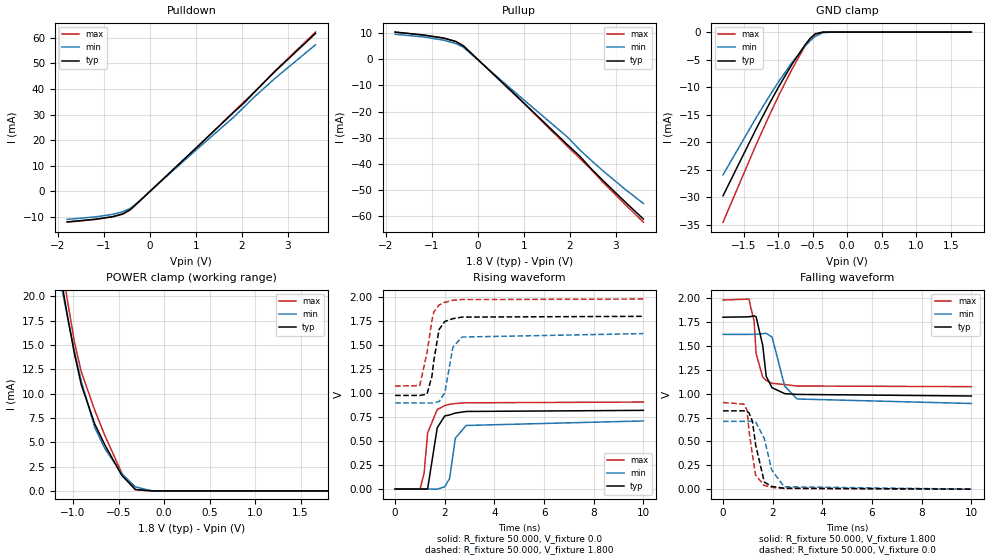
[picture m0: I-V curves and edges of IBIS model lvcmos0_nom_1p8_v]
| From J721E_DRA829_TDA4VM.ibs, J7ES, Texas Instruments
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|   nom_1p8_v
[Model]   lvcmos0_nom_1p8_v
Model_type I/O
Polarity   Non-Inverting
Enable   Active-High
Vinl = 0
Vinh = 0.8
Vmeas = 0.9
Vref = 1.8
Cref = 2pF
Rref = 100000
|   typ   min   max
C_comp   2.559pF   2.311pF   2.804pF
[Voltage Range]   1.8   1.62   1.98
[Temperature Range]   27   150   -40
[Pullup Reference]   1.8   1.62   1.98
[Pulldown Reference]   0   0   0
[Power Clamp Reference]   1.8   1.62   1.98
[GND Clamp Reference]   0   0   0
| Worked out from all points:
|   slope of the pulldown table from 0 to 0.27 V, typ, clamps not added: 59.3 ohm
|   slope of the pullup table from 0 to 0.27 V, typ, clamps not added: 60 ohm
|   GND clamp passes 1 mA (typ) near -0.52 V on its own axis
|   POWER clamp passes 1 mA (typ) near -0.42 V on its own axis
|   rising waveform, R_fixture 50.000, V_fixture 0.0: 20-80 % time 268ps typ, 262ps min, 259ps max; typ from 0 V to 0.82 V
|   rising waveform, R_fixture 50.000, V_fixture 1.800: 20-80 % time 301ps typ, 282ps min, 348ps max; typ from 0.975 V to 1.8 V
|   falling waveform, R_fixture 50.000, V_fixture 1.800: 20-80 % time 298ps typ, 353ps min, 223ps max; typ from 1.8 V to 0.975 V
|   falling waveform, R_fixture 50.000, V_fixture 0.0: 20-80 % time 335ps typ, 434ps min, 272ps max; typ from 0.82 V to 0 V
[Pulldown]
|Voltage   I(typ)   I(min)   I(max)
-1.8V     -11.92mA   -10.93mA   -12.03mA
-1.194V   -10.89mA   -9.969mA   -10.95mA
-808mV    -9.857mA   -8.96mA    -9.935mA
-588mV    -8.778mA   -7.939mA   -8.877mA
-422mV    -7.06mA    -6.521mA   -7.099mA
-257mV    -4.345mA   -4.14mA    -4.333mA
955mV     16.15mA    15.41mA    16.09mA
1.837V    31.15mA    29.26mA    31.44mA
2.057V    34.72mA    33.17mA    35.2mA
2.278V    38.94mA    37.03mA    38.86mA
2.718V    46.83mA    44.15mA    47.05mA
3.6V      61.7mA     57.28mA    62.23mA
[Pullup]
|Voltage   I(typ)   I(min)   I(max)
-1.8V     10.47mA    9.652mA    10.48mA
-1.194V   9.383mA    8.634mA    9.35mA
-753mV    8.204mA    7.418mA    8.202mA
-478mV    6.836mA    6.068mA    6.907mA
-312mV    5.131mA    4.611mA    5.211mA
900mV     -15.03mA   -14.03mA   -15.13mA
1.947V    -32.72mA   -29.76mA   -33.34mA
2.222V    -37.22mA   -34.8mA    -38.07mA
2.443V    -41.56mA   -38.39mA   -41.85mA
2.718V    -46.41mA   -42.7mA    -47.08mA
3.214V    -54.86mA   -50mA      -55.8mA
3.6V      -61.24mA   -55.26mA   -62.44mA
[GND_clamp]
|Voltage   I(typ)   I(min)   I(max)
-1.8V     -29.72mA   -25.92mA   -34.52mA
-1.318V   -17.54mA   -15.51mA   -20.38mA
-1.132V   -13.09mA   -11.7mA    -15.22mA
-984mV    -9.729mA   -8.822mA   -11.3mA
-798mV    -5.797mA   -5.489mA   -6.696mA
-612mV    -2.352mA   -2.576mA   -2.564mA
-538mV    -1.179mA   -1.584mA   -1.166mA
-464mV    -369.8uA   -774.2uA   -275.4uA
-353mV    -16.01uA   -131.2uA   -4.376uA
-241mV    -388.4nA   -11.03uA   -119.1nA
1.8V      0A         0A         0A
[POWER_clamp]
|Voltage   I(typ)   I(min)   I(max)
-1.8V     63.47mA    56.87mA    71.37mA
-1.132V   21.93mA    21.28mA    24mA
-1.095V   19.86mA    19.49mA    21.65mA
-1.058V   17.85mA    17.74mA    19.39mA
-984mV    14.09mA    14.38mA    15.31mA
-909mV    10.91mA    11.3mA     12.26mA
-761mV    6.888mA    6.523mA    8.298mA
-649mV    4.716mA    4.333mA    5.678mA
-464mV    1.593mA    1.774mA    1.827mA
-315mV    150.2uA    416.6uA    111.8uA
-130mV    308.5nA    7.699uA    149nA
1.8V      0A         0A         0A
[Ramp]
| variable   typ   min   max
dV/dt_r   0.492/0.267n   0.426/0.263n   0.544/0.259n
dV/dt_f   0.495/0.298n   0.434/0.353n   0.544/0.223n
R_load = 50.000
[Rising Waveform]
R_fixture= 50.000
V_fixture= 0.0
|time   V(typ)   V(min)   V(max)
0s        815nV      17.91uV    1.383uV
1.005ns   106uV      16.08uV    1.636mV
1.171ns   -1.124mV   24.24uV    170.7mV
1.309ns   855.6uV    18.1uV     584.8mV
1.696ns   637.9mV    -1.709mV   828.1mV
2ns       761.7mV    24.35mV    869.8mV
2.195ns   772.2mV    109.5mV    883.1mV
2.427ns   791.7mV    530mV      891.3mV
2.86ns    808.2mV    662.3mV    898.7mV
10ns      819.8mV    709.6mV    906.4mV
[Rising Waveform]
R_fixture= 50.000
V_fixture= 1.800
V_fixture_min= 1.620
V_fixture_max= 1.980
|time   V(typ)   V(min)   V(max)
0s        975.3mV    896.8mV    1.073V
991ps     975.3mV    896.8mV    1.078V
1.283ns   988.9mV    896.7mV    1.417V
1.482ns   1.174V     896.7mV    1.757V
1.56ns    1.337V     896.7mV    1.845V
1.769ns   1.662V     911.5mV    1.918V
2.001ns   1.746V     1.003V     1.946V
2.328ns   1.776V     1.479V     1.968V
2.694ns   1.792V     1.584V     1.975V
10ns      1.8V       1.62V      1.98V
[Falling Waveform]
R_fixture= 50.000
V_fixture= 1.800
V_fixture_min= 1.620
V_fixture_max= 1.980
|time   V(typ)   V(min)   V(max)
0s        1.8V       1.62V      1.98V
1.041ns   1.804V     1.62V      1.99V
1.253ns   1.814V     1.621V     1.756V
1.331ns   1.805V     1.622V     1.421V
1.599ns   1.505V     1.628V     1.173V
1.738ns   1.182V     1.631V     1.139V
1.975ns   1.062V     1.592V     1.108V
2.483ns   1V         1.079V     1.095V
2.981ns   991.9mV    943.9mV    1.08V
10ns      975.3mV    896.8mV    1.073V
[Falling Waveform]
R_fixture= 50.000
V_fixture= 0.0
V_fixture_min= 0.0
V_fixture_max= 0.0
|time   V(typ)   V(min)   V(max)
0s        819.8mV    709.6mV    906.4mV
837ps     819.8mV    709.6mV    890.7mV
968ps     815.9mV    709.6mV    827.7mV
1.051ns   796.4mV    709.6mV    599.9mV
1.185ns   709.5mV    709.7mV    356.3mV
1.313ns   465.1mV    704.2mV    145.5mV
1.662ns   74.28mV    530.1mV    38.6mV
1.961ns   28.16mV    202.4mV    19.29mV
2.459ns   10.02mV    25.31mV    7.547mV
10ns      42.39uV    105uV      26.07uV
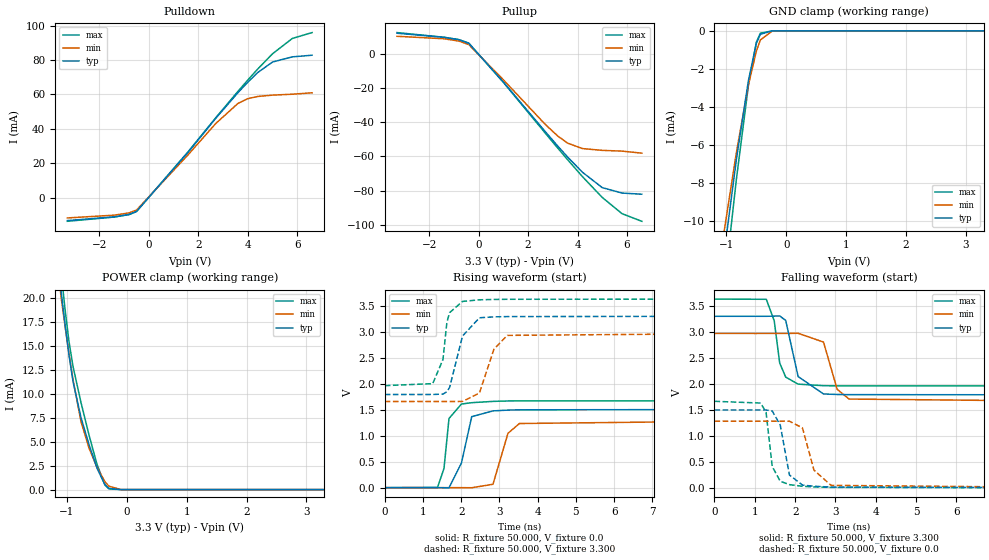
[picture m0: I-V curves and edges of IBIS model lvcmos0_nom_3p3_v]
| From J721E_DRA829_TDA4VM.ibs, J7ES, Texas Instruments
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|   nom_3p3_v
[Model]   lvcmos0_nom_3p3_v
Model_type I/O
Polarity   Non-Inverting
Enable   Active-High
Vinl = 0
Vinh = 0.8
Vmeas = 1.65
Vref = 3.3
Cref = 2pF
Rref = 100000
|   typ   min   max
C_comp   1.372pF   1.338pF   1.409pF
[Voltage Range]   3.3   2.97   3.63
[Temperature Range]   27   150   -40
[Pullup Reference]   3.3   2.97   3.63
[Pulldown Reference]   0   0   0
[Power Clamp Reference]   3.3   2.97   3.63
[GND Clamp Reference]   0   0   0
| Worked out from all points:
|   slope of the pulldown table from 0 to 0.495 V, typ, clamps not added: 59.8 ohm
|   slope of the pullup table from 0 to 0.495 V, typ, clamps not added: 60.7 ohm
|   GND clamp passes 1 mA (typ) near -0.53 V on its own axis
|   POWER clamp passes 1 mA (typ) near -0.41 V on its own axis
|   rising waveform, R_fixture 50.000, V_fixture 0.0: 20-80 % time 204ps typ, 212ps min, 146ps max; typ from 0 V to 1.5 V
|   rising waveform, R_fixture 50.000, V_fixture 3.300: 20-80 % time 256ps typ, 350ps min, 194ps max; typ from 1.79 V to 3.3 V
|   falling waveform, R_fixture 50.000, V_fixture 3.300: 20-80 % time 250ps typ, 265ps min, 213ps max; typ from 3.3 V to 1.79 V
|   falling waveform, R_fixture 50.000, V_fixture 0.0: 20-80 % time 195ps typ, 293ps min, 178ps max; typ from 1.5 V to 0 V
[Pulldown]
|Voltage   I(typ)   I(min)   I(max)
-3.3V     -13.29mA   -11.75mA   -13.7mA
-1.4V     -11.12mA   -10.13mA   -11.23mA
-800mV    -9.721mA   -8.785mA   -9.805mA
-500mV    -7.931mA   -7.165mA   -8.018mA
1.6V      26.66mA    25.2mA     27mA
2.7V      46.1mA     43.08mA    46.41mA
3.6V      61.04mA    54.81mA    61.79mA
4V        67.16mA    57.58mA    68.4mA
4.4V      72.74mA    58.84mA    74.78mA
5V        78.87mA    59.63mA    83.67mA
5.8V      81.87mA    60.16mA    92.56mA
6.6V      82.83mA    60.99mA    95.99mA
[Pullup]
|Voltage   I(typ)   I(min)   I(max)
-3.3V     12mA       10.2mA     12.38mA
-1.4V     9.607mA    8.77mA     9.636mA
-800mV    8.234mA    7.423mA    8.249mA
-400mV    6.133mA    5.372mA    6.247mA
1V        -16.5mA    -15.2mA    -16.69mA
2.7V      -45.57mA   -41.35mA   -46.43mA
3.2V      -53.91mA   -48.06mA   -55.09mA
3.6V      -60.34mA   -52.22mA   -61.89mA
4.2V      -69.22mA   -55.4mA    -71.8mA
5V        -78.21mA   -56.44mA   -83.93mA
5.8V      -81.38mA   -56.87mA   -93.42mA
6.6V      -82.06mA   -58.07mA   -97.88mA
[GND_clamp]
|Voltage   I(typ)   I(min)   I(max)
-3.3V     -91.93mA   -62.08mA   -135.9mA
-1.3V     -18.16mA   -15.85mA   -21.32mA
-1.233V   -16.57mA   -14.51mA   -19.39mA
-1.167V   -14.92mA   -13.18mA   -17.39mA
-1.1V     -13.23mA   -11.81mA   -15.39mA
-1.033V   -11.55mA   -10.42mA   -13.42mA
-833mV    -6.742mA   -6.383mA   -7.774mA
-633mV    -2.616mA   -2.841mA   -2.875mA
-500mV    -654.1uA   -1.067mA   -592.9uA
-433mV    -179.7uA   -478.2uA   -124uA
-233mV    -333.7nA   -8.022uA   -209.7nA
3.3V      0A         0A         0A
[POWER_clamp]
|Voltage   I(typ)   I(min)   I(max)
-3.3V     163.7mA    143.3mA    185.7mA
-1.1V     20.75mA    20.14mA    22.78mA
-1.033V   17.24mA    17.07mA    18.82mA
-967mV    14.04mA    14.16mA    15.45mA
-900mV    11.29mA    11.5mA     12.86mA
-767mV    7.523mA    7.112mA    9.104mA
-633mV    4.713mA    4.344mA    5.707mA
-500mV    2.255mA    2.334mA    2.657mA
-367mV    510.2uA    822.4uA    470.8uA
-300mV    125.7uA    354.2uA    72.09uA
-100mV    199nA      4.751uA    105.3nA
3.3V      0A         0A         0A
[Ramp]
| variable   typ   min   max
dV/dt_r   0.903/0.203n   0.772/0.212n   1.003/0.146n
dV/dt_f   0.907/0.249n   0.787/0.264n   1.002/0.210n
R_load = 50.000
[Rising Waveform]
R_fixture= 50.000
V_fixture= 0.0
|time   V(typ)   V(min)   V(max)
0s        1.895uV    19.8uV     2.572uV
1.38ns    -155.4uV   24.41uV    4.525mV
1.549ns   -1.989mV   -115.2uV   369.3mV
1.68ns    -4.024mV   -24.52uV   1.332V
2.006ns   475.5mV    -280.6uV   1.61V
2.274ns   1.367V     -1.817mV   1.636V
2.831ns   1.478V     65.01mV    1.661V
3.222ns   1.493V     1.046V     1.669V
3.522ns   1.499V     1.235V     1.67V
10ns      1.504V     1.287V     1.672V
[Rising Waveform]
R_fixture= 50.000
V_fixture= 3.300
V_fixture_min= 2.970
V_fixture_max= 3.630
|time   V(typ)   V(min)   V(max)
0s        1.794V     1.659V     1.964V
1.254ns   1.794V     1.659V     2.003V
1.522ns   1.802V     1.659V     2.467V
1.624ns   1.847V     1.659V     3.178V
1.695ns   1.928V     1.659V     3.369V
2.034ns   2.92V      1.66V      3.586V
2.477ns   3.271V     1.824V     3.617V
2.857ns   3.288V     2.669V     3.624V
3.207ns   3.294V     2.932V     3.627V
10ns      3.3V       2.97V      3.63V
[Falling Waveform]
R_fixture= 50.000
V_fixture= 3.300
V_fixture_min= 2.970
V_fixture_max= 3.630
|time   V(typ)   V(min)   V(max)
0s        3.3V       2.97V      3.63V
1.284ns   3.3V       2.97V      3.627V
1.481ns   3.303V     2.97V      3.214V
1.617ns   3.307V     2.97V      2.4V
1.766ns   3.22V      2.97V      2.13V
2.074ns   2.14V      2.973V     1.995V
2.703ns   1.806V     2.804V     1.965V
3.041ns   1.796V     1.896V     1.962V
3.338ns   1.793V     1.708V     1.961V
10ns      1.789V     1.658V     1.96V
[Falling Waveform]
R_fixture= 50.000
V_fixture= 0.0
V_fixture_min= 0.0
V_fixture_max= 0.0
|time   V(typ)   V(min)   V(max)
0s        1.498V     1.283V     1.665V
1.144ns   1.498V     1.283V     1.631V
1.278ns   1.498V     1.283V     1.456V
1.432ns   1.479V     1.283V     410.2mV
1.63ns    1.209V     1.283V     127.7mV
1.858ns   247.9mV    1.282V     61.71mV
2.181ns   53.72mV    1.153V     30.18mV
2.467ns   30.54mV    339.9mV    17.76mV
2.89ns    15.12mV    48.25mV    9.097mV
10ns      66.8uV     145.2uV    36.97uV
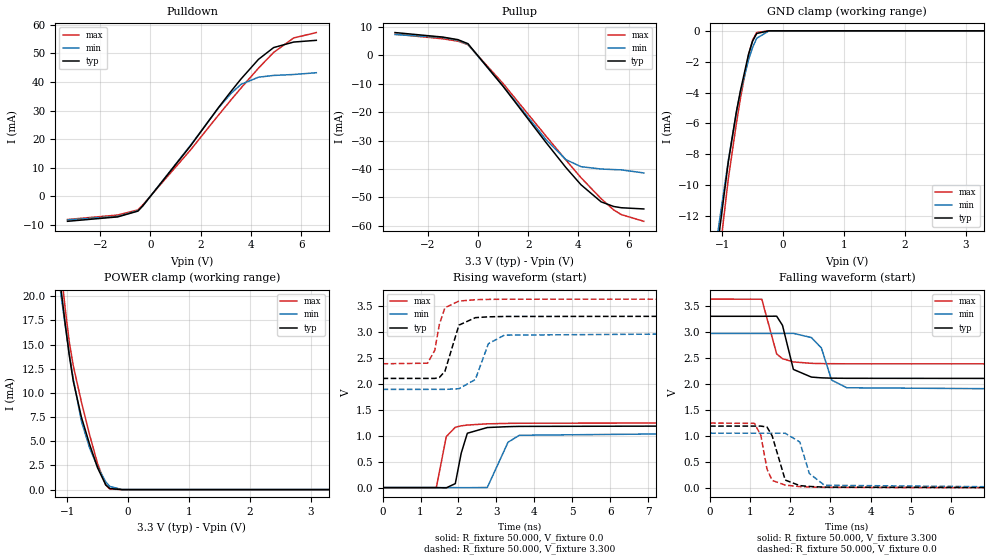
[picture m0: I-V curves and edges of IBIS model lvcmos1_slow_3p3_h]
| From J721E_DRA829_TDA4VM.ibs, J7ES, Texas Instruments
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|   slow_3p3_h
[Model]   lvcmos1_slow_3p3_h
Model_type I/O
Polarity   Non-Inverting
Enable   Active-High
Vinl = 0
Vinh = 0.8
Vmeas = 1.65
Vref = 3.3
Cref = 2pF
Rref = 100000
|   typ   min   max
C_comp   1.414pF   1.380pF   1.447pF
[Voltage Range]   3.3   2.97   3.63
[Temperature Range]   27   150   -40
[Pullup Reference]   3.3   2.97   3.63
[Pulldown Reference]   0   0   0
[Power Clamp Reference]   3.3   2.97   3.63
[GND Clamp Reference]   0   0   0
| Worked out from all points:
|   slope of the pulldown table from 0 to 0.495 V, typ, clamps not added: 90.3 ohm
|   slope of the pullup table from 0 to 0.495 V, typ, clamps not added: 91.7 ohm
|   GND clamp passes 1 mA (typ) near -0.53 V on its own axis
|   POWER clamp passes 1 mA (typ) near -0.41 V on its own axis
|   rising waveform, R_fixture 50.000, V_fixture 0.0: 20-80 % time 183ps typ, 292ps min, 182ps max; typ from 0 V to 1.19 V
|   rising waveform, R_fixture 50.000, V_fixture 3.300: 20-80 % time 266ps typ, 306ps min, 208ps max; typ from 2.1 V to 3.3 V
|   falling waveform, R_fixture 50.000, V_fixture 3.300: 20-80 % time 198ps typ, 329ps min, 206ps max; typ from 3.3 V to 2.1 V
|   falling waveform, R_fixture 50.000, V_fixture 0.0: 20-80 % time 245ps typ, 257ps min, 194ps max; typ from 1.19 V to 0 V
[Pulldown]
|Voltage   I(typ)   I(min)   I(max)
-3.3V     -8.786mA   -8.326mA   -8.158mA
-1.3V     -7.238mA   -7.068mA   -6.584mA
-500mV    -5.218mA   -5.082mA   -4.783mA
-300mV    -3.329mA   -3.373mA   -2.999mA
1.6V      17.7mA     17.93mA    16.27mA
2.7V      30.97mA    30.86mA    28.33mA
3.2V      36.66mA    35.95mA    33.67mA
3.6V      41.04mA    39.17mA    37.86mA
4.3V      47.96mA    41.7mA     44.88mA
4.9V      52.07mA    42.31mA    50.35mA
5.7V      54.01mA    42.64mA    55.45mA
6.6V      54.61mA    43.26mA    57.33mA
[Pullup]
|Voltage   I(typ)   I(min)   I(max)
-3.3V     7.94mA     7.245mA    7.375mA
-1.4V     6.356mA    6.223mA    5.749mA
-800mV    5.458mA    5.239mA    4.924mA
-400mV    4.045mA    3.827mA    3.712mA
1V        -10.95mA   -10.84mA   -9.98mA
2.7V      -30.6mA    -29.63mA   -28.35mA
3.5V      -39.5mA    -36.72mA   -36.87mA
4.1V      -45.55mA   -39.2mA    -43.06mA
4.9V      -51.56mA   -40.02mA   -50.44mA
5.4V      -53.19mA   -40.22mA   -54.38mA
5.7V      -53.63mA   -40.32mA   -56.03mA
6.6V      -54.06mA   -41.4mA    -58.4mA
[GND_clamp]
|Voltage   I(typ)   I(min)   I(max)
-3.3V     -113.8mA   -82.24mA   -159mA
-1.167V   -17.01mA   -15.72mA   -19.19mA
-1.1V     -14.77mA   -13.85mA   -16.62mA
-1.033V   -12.58mA   -11.98mA   -14.1mA
-900mV    -8.5mA     -8.403mA   -9.586mA
-767mV    -5.246mA   -5.262mA   -5.996mA
-700mV    -3.866mA   -3.96mA    -4.363mA
-567mV    -1.506mA   -1.869mA   -1.555mA
-500mV    -657.8uA   -1.066mA   -589.2uA
-433mV    -173.4uA   -482uA     -106.1uA
-233mV    -388.4nA   -7.967uA   -203.5nA
3.3V      0A         0A         0A
[POWER_clamp]
|Voltage   I(typ)   I(min)   I(max)
-3.3V     168.5mA    143.2mA    197.8mA
-1.1V     20.63mA    20.01mA    22.62mA
-1.033V   17.13mA    16.96mA    18.7mA
-967mV    13.91mA    14.09mA    15.3mA
-900mV    11.2mA     11.42mA    12.8mA
-767mV    7.499mA    7.079mA    9.068mA
-633mV    4.696mA    4.33mA     5.685mA
-500mV    2.241mA    2.319mA    2.654mA
-367mV    495uA      804.4uA    468.5uA
-300mV    111.9uA    329.7uA    65.22uA
-100mV    170.1nA    4.018uA    96.08nA
3.3V      0A         0A         0A
[Ramp]
| variable   typ   min   max
dV/dt_r   0.713/0.182n   0.631/0.292n   0.747/0.181n
dV/dt_f   0.718/0.197n   0.647/0.329n   0.747/0.207n
R_load = 50.000
[Rising Waveform]
R_fixture= 50.000
V_fixture= 0.0
V_fixture_min= 0.0
V_fixture_max= 0.0
|time   V(typ)   V(min)   V(max)
0s        2.269uV    23.11uV    3.249uV
1.417ns   -521.6uV   104.5uV    1.015mV
1.679ns   -4.773mV   -51.5uV    981.7mV
1.917ns   77.09mV    -332.5uV   1.163V
2.073ns   664mV      -1.539mV   1.19V
2.234ns   1.047V     -1.716mV   1.205V
2.761ns   1.157V     3.043mV    1.228V
3.307ns   1.174V     874.2mV    1.237V
3.607ns   1.179V     1.008V     1.24V
10ns      1.188V     1.052V     1.246V
[Rising Waveform]
R_fixture= 50.000
V_fixture= 3.300
V_fixture_min= 2.970
V_fixture_max= 3.630
|time   V(typ)   V(min)   V(max)
0s        2.103V     1.892V     2.385V
1.184ns   2.103V     1.892V     2.396V
1.376ns   2.103V     1.893V     2.644V
1.497ns   2.121V     1.892V     3.143V
1.644ns   2.24V      1.892V     3.465V
2.012ns   3.129V     1.904V     3.592V
2.445ns   3.273V     2.081V     3.619V
2.79ns    3.289V     2.772V     3.625V
3.21ns    3.296V     2.936V     3.628V
10ns      3.3V       2.97V      3.63V
[Falling Waveform]
R_fixture= 50.000
V_fixture= 3.300
V_fixture_min= 2.970
V_fixture_max= 3.630
|time   V(typ)   V(min)   V(max)
0s        3.3V       2.97V      3.63V
1.289ns   3.3V       2.97V      3.629V
1.66ns    3.302V     2.97V      2.576V
1.805ns   3.126V     2.97V      2.485V
2.077ns   2.278V     2.972V     2.422V
2.524ns   2.131V     2.891V     2.395V
2.774ns   2.116V     2.692V     2.39V
3.029ns   2.11V      2.073V     2.388V
3.411ns   2.107V     1.925V     2.386V
10ns      2.103V     1.892V     2.385V
[Falling Waveform]
R_fixture= 50.000
V_fixture= 0.0
V_fixture_min= 0.0
V_fixture_max= 0.0
|time   V(typ)   V(min)   V(max)
0s        1.188V     1.052V     1.246V
1.106ns   1.188V     1.052V     1.241V
1.265ns   1.188V     1.052V     1.011V
1.418ns   1.171V     1.052V     364.5mV
1.547ns   1.002V     1.052V     143.1mV
1.873ns   150.2mV    1.05V      52.67mV
2.237ns   43.23mV    881.6mV    24.44mV
2.474ns   26.95mV    277.4mV    16.29mV
2.851ns   14.17mV    50.22mV    9.394mV
10ns      63.6uV     132.8uV    38.55uV
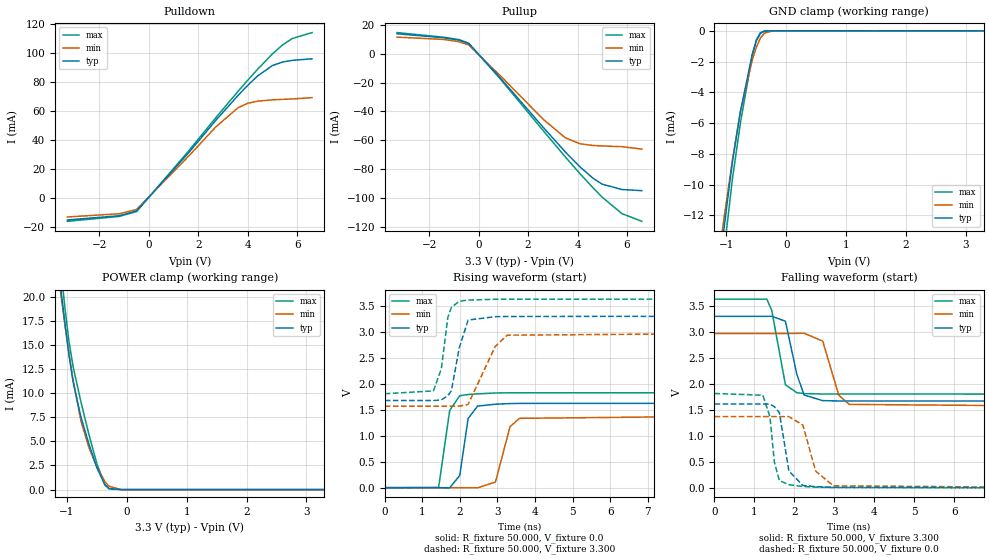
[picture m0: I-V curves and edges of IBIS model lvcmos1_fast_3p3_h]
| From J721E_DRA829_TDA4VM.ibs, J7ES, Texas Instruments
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|   fast_3p3_h
[Model]   lvcmos1_fast_3p3_h
Model_type I/O
Polarity   Non-Inverting
Enable   Active-High
Vinl = 0
Vinh = 0.8
Vmeas = 1.65
Vref = 3.3
Cref = 2pF
Rref = 100000
|   typ   min   max
C_comp   1.362pF   1.327pF   1.397pF
[Voltage Range]   3.3   2.97   3.63
[Temperature Range]   27   150   -40
[Pullup Reference]   3.3   2.97   3.63
[Pulldown Reference]   0   0   0
[Power Clamp Reference]   3.3   2.97   3.63
[GND Clamp Reference]   0   0   0
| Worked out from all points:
|   slope of the pulldown table from 0 to 0.495 V, typ, clamps not added: 51.6 ohm
|   slope of the pullup table from 0 to 0.495 V, typ, clamps not added: 52.3 ohm
|   GND clamp passes 1 mA (typ) near -0.53 V on its own axis
|   POWER clamp passes 1 mA (typ) near -0.41 V on its own axis
|   rising waveform, R_fixture 50.000, V_fixture 0.0: 20-80 % time 158ps typ, 269ps min, 184ps max; typ from 0 V to 1.62 V
|   rising waveform, R_fixture 50.000, V_fixture 3.300: 20-80 % time 255ps typ, 375ps min, 216ps max; typ from 1.68 V to 3.3 V
|   falling waveform, R_fixture 50.000, V_fixture 3.300: 20-80 % time 211ps typ, 294ps min, 223ps max; typ from 3.3 V to 1.67 V
|   falling waveform, R_fixture 50.000, V_fixture 0.0: 20-80 % time 189ps typ, 291ps min, 171ps max; typ from 1.61 V to 0 V
[Pulldown]
|Voltage   I(typ)   I(min)   I(max)
-3.3V     -15.39mA   -13.32mA   -16.31mA
-1.2V     -12.47mA   -11.1mA    -12.94mA
-500mV    -9.172mA   -8.138mA   -9.6mA
1.6V      30.91mA    28.58mA    32.15mA
2.7V      53.34mA    48.8mA     55.15mA
3.6V      70.58mA    62.12mA    73.39mA
4V        77.71mA    65.27mA    81.22mA
4.4V      84.18mA    66.7mA     88.81mA
5V        91.35mA    67.61mA    99.41mA
5.4V      93.72mA    67.94mA    105.5mA
5.8V      94.91mA    68.22mA    110mA
6.6V      95.98mA    69.15mA    114.1mA
[Pullup]
|Voltage   I(typ)   I(min)   I(max)
-3.3V     13.92mA    11.59mA    14.75mA
-1.4V     11.14mA    9.957mA    11.49mA
-800mV    9.572mA    8.415mA    9.866mA
-400mV    7.09mA     6.102mA    7.413mA
900mV     -17.21mA   -15.55mA   -17.88mA
2.6V      -50.75mA   -45.22mA   -53.02mA
3.5V      -67.96mA   -58.18mA   -71.41mA
4.1V      -78.42mA   -62.41mA   -83.18mA
4.6V      -85.96mA   -63.54mA   -92.45mA
5V        -90.46mA   -63.93mA   -99.52mA
5.8V      -94.17mA   -64.43mA   -110.9mA
6.6V      -94.93mA   -66.09mA   -116.2mA
[GND_clamp]
|Voltage   I(typ)   I(min)   I(max)
-3.3V     -113.8mA   -82.24mA   -159mA
-1.167V   -17.01mA   -15.72mA   -19.2mA
-1.1V     -14.77mA   -13.85mA   -16.61mA
-1.033V   -12.58mA   -11.98mA   -14.1mA
-900mV    -8.5mA     -8.402mA   -9.615mA
-767mV    -5.246mA   -5.261mA   -6.001mA
-567mV    -1.506mA   -1.867mA   -1.552mA
-500mV    -657.8uA   -1.062mA   -588.9uA
-433mV    -173.4uA   -477.6uA   -123.4uA
-367mV    -24.15uA   -156.5uA   -9.386uA
-233mV    -388.4nA   -8.093uA   -215nA
3.3V      0A         0A         0A
[POWER_clamp]
|Voltage   I(typ)   I(min)   I(max)
-3.3V     168.5mA    143.2mA    197.8mA
-1.1V     20.63mA    20.02mA    22.62mA
-1.033V   17.13mA    16.97mA    18.69mA
-967mV    13.91mA    14.07mA    15.32mA
-900mV    11.2mA     11.41mA    12.78mA
-767mV    7.499mA    7.086mA    9.065mA
-633mV    4.696mA    4.33mA     5.68mA
-500mV    2.241mA    2.328mA    2.652mA
-367mV    494.4uA    819.9uA    490.6uA
-300mV    111.5uA    353.3uA    87.6uA
-100mV    169.5nA    4.694uA    107.5nA
3.3V      0A         0A         0A
[Ramp]
| variable   typ   min   max
dV/dt_r   0.975/0.158n   0.829/0.269n   1.096/0.184n
dV/dt_f   0.978/0.210n   0.843/0.294n   1.095/0.223n
R_load = 50.000
[Rising Waveform]
R_fixture= 50.000
V_fixture= 0.0
V_fixture_min= 0.0
V_fixture_max= 0.0
|time   V(typ)   V(min)   V(max)
0s        1.789uV    19uV       2.438uV
1.433ns   -523.6uV   87.95uV    3.462mV
1.729ns   -3.136mV   35.56uV    1.487V
1.997ns   237.2mV    -208.9uV   1.771V
2.219ns   1.331V     -1.478mV   1.794V
2.469ns   1.57V      -3.455mV   1.806V
2.947ns   1.607V     108.6mV    1.823V
3.335ns   1.619V     1.174V     1.827V
3.585ns   1.622V     1.335V     1.827V
10ns      1.625V     1.381V     1.827V
[Rising Waveform]
R_fixture= 50.000
V_fixture= 3.300
V_fixture_min= 2.970
V_fixture_max= 3.630
|time   V(typ)   V(min)   V(max)
0s        1.678V     1.57V      1.809V
1.296ns   1.678V     1.57V      1.863V
1.506ns   1.69V      1.57V      2.29V
1.679ns   1.773V     1.57V      3.277V
1.773ns   1.863V     1.57V      3.469V
1.983ns   2.692V     1.57V      3.589V
2.22ns    3.228V     1.604V     3.612V
2.94ns    3.292V     2.718V     3.627V
3.26ns    3.296V     2.936V     3.628V
10ns      3.3V       2.97V      3.63V
[Falling Waveform]
R_fixture= 50.000
V_fixture= 3.300
V_fixture_min= 2.970
V_fixture_max= 3.630
|time   V(typ)   V(min)   V(max)
0s        3.3V       2.97V      3.63V
1.31ns    3.3V       2.97V      3.631V
1.433ns   3.302V     2.97V      3.416V
1.776ns   3.206V     2.97V      1.984V
2.061ns   2.186V     2.972V     1.831V
2.244ns   1.786V     2.975V     1.813V
2.71ns    1.678V     2.823V     1.806V
3.111ns   1.672V     1.785V     1.805V
3.371ns   1.671V     1.606V     1.805V
10ns      1.669V     1.565V     1.804V
[Falling Waveform]
R_fixture= 50.000
V_fixture= 0.0
V_fixture_min= 0.0
V_fixture_max= 0.0
|time   V(typ)   V(min)   V(max)
0s        1.614V     1.371V     1.816V
1.211ns   1.614V     1.371V     1.782V
1.389ns   1.612V     1.371V     1.367V
1.499ns   1.562V     1.371V     496.9mV
1.625ns   1.447V     1.371V     140mV
1.863ns   327.4mV    1.371V     61.18mV
2.212ns   45.58mV    1.209V     25.89mV
2.533ns   23.69mV    322.1mV    13.2mV
2.977ns   10.39mV    39.21mV    6.392mV
10ns      58.09uV    126.4uV    35.71uV
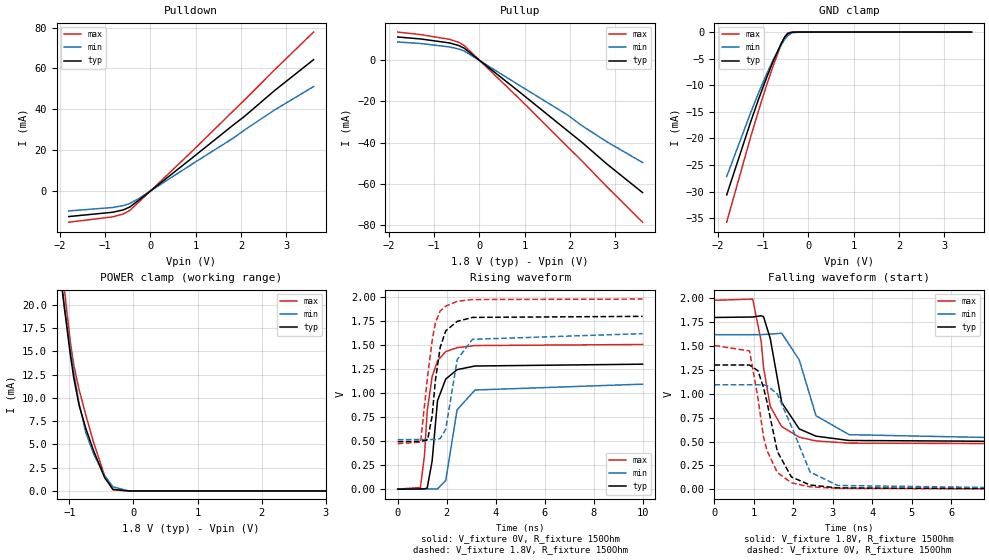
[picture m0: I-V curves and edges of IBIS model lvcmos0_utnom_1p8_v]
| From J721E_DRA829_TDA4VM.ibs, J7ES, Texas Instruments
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|   utnom_1p8_v
[Model]   lvcmos0_utnom_1p8_v
Model_type   I/O
Polarity   Non-Inverting
Enable   Active-High
Vinl = 0
Vinh = 0.8
Vmeas = 0.9
Vref = 1.8
Cref = 2pF
Rref = 100000
|   typ   min   max
C_comp   2.521pF   2.296pF   2.733pF
[Voltage Range]   1.8   1.62   1.98
[Temperature Range]   27   150   -40
[Pullup Reference]   1.8   1.62   1.98
[Pulldown Reference]   0   0   0
[Power Clamp Reference]   1.8   1.62   1.98
[GND Clamp Reference]   0   0   0
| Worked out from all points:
|   slope of the pulldown table from 0 to 0.27 V, typ, clamps not added: 57 ohm
|   slope of the pullup table from 0 to 0.27 V, typ, clamps not added: 57.3 ohm
|   GND clamp passes 1 mA (typ) near -0.52 V on its own axis
|   POWER clamp passes 1 mA (typ) near -0.42 V on its own axis
|   falling waveform, V_fixture 1.8V, R_fixture 150Ohm: 20-80 % time 418ps typ, 526ps min, 366ps max; typ from 1.8 V to 0.495 V
|   rising waveform, V_fixture 0V, R_fixture 150Ohm: 20-80 % time 359ps typ, 442ps min, 372ps max; typ from 0.001 V to 1.3 V
|   rising waveform, V_fixture 1.8V, R_fixture 150Ohm: 20-80 % time 391ps typ, 439ps min, 401ps max; typ from 0.495 V to 1.8 V
|   falling waveform, V_fixture 0V, R_fixture 150Ohm: 20-80 % time 470ps typ, 639ps min, 417ps max; typ from 1.3 V to 0.001 V
[Pulldown]
|   Voltage   I(typ)   I(min)   I(max)
-1.8V     -12.49mA   -9.745mA   -15.24mA
-833.4mV  -10.38mA   -8.049mA   -12.64mA
-595.8mV  -9.207mA   -7.098mA   -11.24mA
-450mV    -7.754mA   -6.062mA   -9.423mA
-271.8mV  -4.773mA   -3.875mA   -5.749mA
921.6mV   16.2mA     13.2mA     19.49mA
1.834V    32.42mA    25.98mA    39.34mA
2.066V    36.36mA    29.7mA     44.31mA
2.736V    49.1mA     39.62mA    59.22mA
3.6V      64.28mA    51.14mA    77.77mA
[GND Clamp]
|   Voltage   I(typ)   I(min)   I(max)
-1.8V     -30.61mA   -27.15mA   -35.74mA
-1.271V   -16.88mA   -15.15mA   -19.71mA
-1.109V   -12.91mA   -11.68mA   -15.1mA
-930.6mV  -8.806mA   -8.105mA   -10.26mA
-774mV    -5.456mA   -5.214mA   -6.322mA
-595.8mV  -2.105mA   -2.381mA   -2.266mA
-520.2mV  -945.6uA   -1.379mA   -889uA
-450mV    -262.5uA   -649.2uA   -165.7uA
-358.2mV  -16.82uA   -139.3uA   -4.154uA
-223.2mV  -201.3nA   -6.783uA   -97.92nA
3.6V      0A         0A         0A
[Pullup]
|   Voltage   I(typ)   I(min)   I(max)
-1.8V     11.11mA    8.694mA    13.49mA
-1.292V   10.16mA    7.95mA     12.28mA
-660.6mV  8.244mA    6.316mA    10mA
-450mV    6.96mA     5.257mA    8.528mA
-336.6mV  5.734mA    4.366mA    7.041mA
900mV     -15.74mA   -12.52mA   -19.14mA
1.958V    -34.51mA   -26.82mA   -42.3mA
2.266V    -39.94mA   -31.86mA   -48.95mA
2.812V    -50.35mA   -39.58mA   -61.37mA
3.6V      -64.22mA   -49.66mA   -78.55mA
[POWER Clamp]
|   Voltage   I(typ)   I(min)   I(max)
-1.8V     66.46mA    62.68mA    76.48mA
-1.114V   21.78mA    21.94mA    24.12mA
-1.082V   19.91mA    20.21mA    21.93mA
-984.6mV  14.65mA    15.28mA    16.02mA
-930.6mV  12.13mA    12.76mA    13.52mA
-849.6mV  9.251mA    9.447mA    10.93mA
-741.6mV  6.689mA    6.229mA    8.125mA
-622.8mV  4.34mA     3.998mA    5.244mA
-450mV    1.426mA    1.638mA    1.617mA
-320.4mV  169.4uA    443uA      117uA
-72mV     66.15nA    1.802uA    96.53nA
3.6V      0A         0A         0A
[Ramp]
R_load = 150
|   typ   min   max
dV/dt_r   0.781005/3.54248e-10   0.655956/4.34779e-10   0.903654/3.69784e-10
dV/dt_f   0.782737/4.17005e-10   0.66237/5.22162e-10   0.903303/3.66596e-10
[Falling Waveform]
V_fixture = 1.8V
V_fixture_min = 1.62V
V_fixture_max = 1.98V
R_fixture = 150Ohm
C_fixture = 0F
|   Time   V(typ)   V(min)   V(max)
0s        1.8V       1.62V      1.98V
970ps     1.805V     1.62V      1.993V
1.185ns   1.818V     1.62V      1.55V
1.245ns   1.808V     1.622V     1.275V
1.415ns   1.58V      1.626V     867.5mV
1.705ns   909.6mV    1.635V     656.3mV
2.15ns    632.2mV    1.356V     545.6mV
2.575ns   556.1mV    770.9mV    506.1mV
3.415ns   510.9mV    571.7mV    483.1mV
10ns      495.4mV    516mV      474.5mV
[Rising Waveform]
V_fixture = 0V
V_fixture_min = 0V
V_fixture_max = 0V
R_fixture = 150Ohm
C_fixture = 0F
|   Time   V(typ)   V(min)   V(max)
0s        663.7uV    667.6uV    1.226mV
925ps     2.89mV     1.96mV     18.09mV
1.09ns    4.316mV    2.382mV    346mV
1.205ns   12.78mV    2.384mV    815.9mV
1.405ns   293.8mV    2.137mV    1.172V
1.625ns   921.6mV    2.461mV    1.338V
1.96ns    1.147V     90.55mV    1.433V
2.425ns   1.245V     826.5mV    1.474V
3.155ns   1.283V     1.033V     1.496V
10ns      1.302V     1.094V     1.507V
[Rising Waveform]
V_fixture = 1.8V
V_fixture_min = 1.62V
V_fixture_max = 1.98V
R_fixture = 150Ohm
C_fixture = 0F
|   Time   V(typ)   V(min)   V(max)
0s        495.4mV    516mV      474.5mV
935ps     497.6mV    517.4mV    490.3mV
1.22ns    513.6mV    518.1mV    1.174V
1.405ns   761.8mV    517.7mV    1.545V
1.54ns    1.137V     518.1mV    1.736V
1.735ns   1.478V     527.4mV    1.855V
1.96ns    1.649V     625.1mV    1.906V
2.43ns    1.748V     1.35V      1.957V
3.055ns   1.789V     1.561V     1.975V
10ns      1.8V       1.62V      1.98V
[Falling Waveform]
|Gnd
V_fixture = 0V
V_fixture_min = 0V
V_fixture_max = 0V
R_fixture = 150Ohm
C_fixture = 0F
|   Time   V(typ)   V(min)   V(max)
0s        1.302V     1.094V     1.507V
890ps     1.302V     1.094V     1.449V
1.105ns   1.241V     1.094V     951.2mV
1.245ns   1.063V     1.093V     547.9mV
1.33ns    919mV      1.087V     407.3mV
1.595ns   395.7mV    998.2mV    175.5mV
1.95ns    129.1mV    660.7mV    67.52mV
2.425ns   44.38mV    180.4mV    25.47mV
3.125ns   13.82mV    39.45mV    9.369mV
10ns      663.6uV    667.5uV    1.226mV
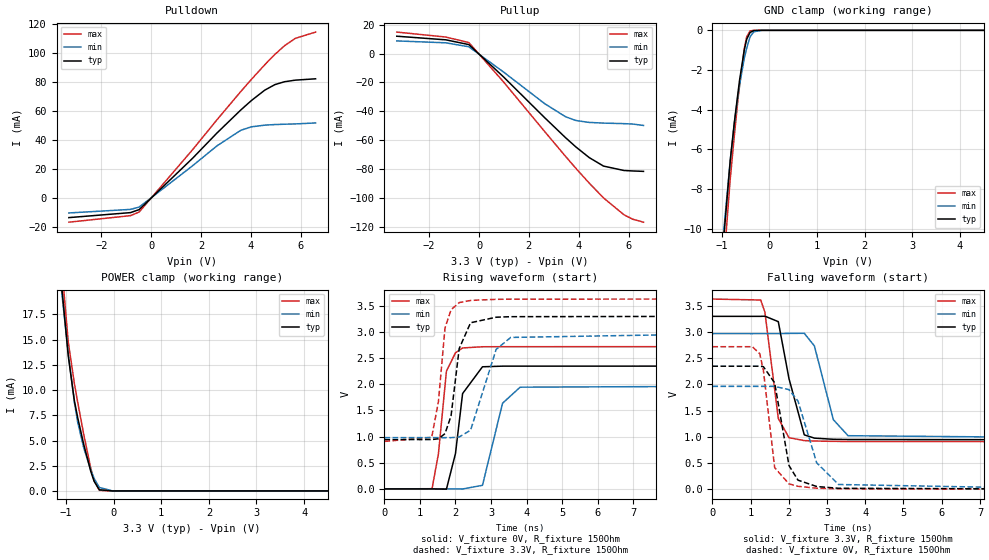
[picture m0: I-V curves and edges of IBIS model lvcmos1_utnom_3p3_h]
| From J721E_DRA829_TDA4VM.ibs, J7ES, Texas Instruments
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|   utnom_3p3_h
[Model]   lvcmos1_utnom_3p3_h
Model_type   I/O
Polarity   Non-Inverting
Enable   Active-High
Vinl = 0
Vinh = 0.8
Vmeas = 1.65
Vref = 3.3
Cref = 2pF
Rref = 100000
|   typ   min   max
C_comp   1.381pF   1.346pF   1.415pF
[Voltage Range]   3.3   2.97   3.63
[Temperature Range]   27   150   -40
[Pullup Reference]   3.3   2.97   3.63
[Pulldown Reference]   0   0   0
[Power Clamp Reference]   3.3   2.97   3.63
[GND Clamp Reference]   0   0   0
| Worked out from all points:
|   slope of the pulldown table from 0 to 0.495 V, typ, clamps not added: 60 ohm
|   slope of the pullup table from 0 to 0.495 V, typ, clamps not added: 60.9 ohm
|   GND clamp passes 1 mA (typ) near -0.53 V on its own axis
|   POWER clamp passes 1 mA (typ) near -0.41 V on its own axis
|   falling waveform, V_fixture 3.3V, R_fixture 150Ohm: 20-80 % time 312ps typ, 397ps min, 265ps max; typ from 3.3 V to 0.943 V
|   rising waveform, V_fixture 0V, R_fixture 150Ohm: 20-80 % time 278ps typ, 375ps min, 236ps max; typ from 0 V to 2.35 V
|   rising waveform, V_fixture 3.3V, R_fixture 150Ohm: 20-80 % time 269ps typ, 452ps min, 241ps max; typ from 0.943 V to 3.3 V
|   falling waveform, V_fixture 0V, R_fixture 150Ohm: 20-80 % time 331ps typ, 550ps min, 246ps max; typ from 2.35 V to 0 V
[Pulldown]
|   Voltage   I(typ)   I(min)   I(max)
-3.3V     -13.22mA   -10.01mA   -16.37mA
-825mV    -9.773mA   -7.569mA   -11.86mA
-478.5mV  -7.701mA   -5.952mA   -9.364mA
1.67V     27.73mA    22.55mA    33.64mA
2.64V     44.98mA    36.14mA    54.07mA
3.6V      60.89mA    46.9mA     73.61mA
4.026V    67.4mA     49.29mA    81.96mA
4.561V    74.53mA    50.44mA    92.01mA
4.966V    78.33mA    50.84mA    99.12mA
5.353V    80.32mA    51.08mA    105.1mA
5.788V    81.42mA    51.27mA    110.2mA
6.6V      82.34mA    51.96mA    114.5mA
[GND Clamp]
|   Voltage   I(typ)   I(min)   I(max)
-3.3V     -115mA     -82.92mA   -162mA
-1.013V   -11.97mA   -11.46mA   -13.42mA
-825mV    -6.58mA    -6.573mA   -7.512mA
-735.9mV  -4.599mA   -4.642mA   -5.244mA
-656.7mV  -3.049mA   -3.217mA   -3.363mA
-627mV    -2.488mA   -2.737mA   -2.772mA
-528mV    -971.8uA   -1.387mA   -897uA
-478.5mV  -448.1uA   -900.5uA   -330.2uA
-409.2mV  -110.7uA   -334.4uA   -32.93uA
-330mV    -9.798uA   -70.26uA   -1.753uA
-161.7mV  -77.56nA   -2.012uA   -109nA
6.6V      0A         0A         0A
[Pullup]
|   Voltage   I(typ)   I(min)   I(max)
-3.3V     11.96mA    8.712mA    14.81mA
-1.33V    9.454mA    7.39mA     11.38mA
-409.2mV  6.171mA    4.659mA    7.568mA
976.8mV   -16.07mA   -12.71mA   -19.5mA
2.64V     -44.46mA   -34.72mA   -54.05mA
3.472V    -58.18mA   -43.72mA   -71.1mA
3.887V    -64.59mA   -46.3mA    -79.38mA
4.422V    -71.95mA   -47.63mA   -89.58mA
4.996V    -77.82mA   -48.1mA    -99.82mA
5.818V    -80.87mA   -48.48mA   -111.5mA
6.164V    -81.18mA   -48.75mA   -114.5mA
6.6V      -81.48mA   -49.72mA   -116.6mA
[POWER Clamp]
|   Voltage   I(typ)   I(min)   I(max)
-3.3V     170.4mA    144.6mA    202.9mA
-1.132V   22.5mA     21.65mA    24.88mA
-1.092V   20.32mA    19.77mA    22.37mA
-953.7mV  13.39mA    13.61mA    14.77mA
-825mV    8.945mA    8.794mA    10.65mA
-755.7mV  7.268mA    6.816mA    8.801mA
-627mV    4.579mA    4.228mA    5.562mA
-478.5mV  1.903mA    2.067mA    2.21mA
-409.2mV  950.9uA    1.225mA    996.3uA
-300.3mV  113.4uA    342.8uA    57.15uA
-23.1mV   24.51nA    848.7nA    21nA
6.6V      0A         0A         0A
[Ramp]
R_load = 150
|   typ   min   max
dV/dt_r   1.40871/2.77196e-10   1.17787/3.72528e-10   1.63214/2.36862e-10
dV/dt_f   1.41415/3.11832e-10   1.19365/3.97592e-10   1.63335/2.64705e-10
[Falling Waveform]
V_fixture = 3.3V
V_fixture_min = 2.97V
V_fixture_max = 3.63V
R_fixture = 150Ohm
C_fixture = 0F
|   Time   V(typ)   V(min)   V(max)
0s        3.3V       2.97V      3.63V
1.265ns   3.3V       2.97V      3.612V
1.375ns   3.303V     2.97V      3.378V
1.725ns   3.199V     2.97V      1.35V
2.005ns   2.109V     2.974V     982.9mV
2.405ns   1.037V     2.976V     927.6mV
2.67ns    974.5mV    2.734V     919.5mV
3.165ns   952.5mV    1.327V     912.7mV
3.55ns    948.2mV    1.021V     910.6mV
10ns      942.9mV    980.3mV    907.7mV
[Rising Waveform]
V_fixture = 0V
V_fixture_min = 0V
V_fixture_max = 0V
R_fixture = 150Ohm
C_fixture = 0F
|   Time   V(typ)   V(min)   V(max)
0s        99.74uV    253uV      47.62uV
1.34ns    -12.15uV   221.8uV    3.353mV
1.52ns    -2.386mV   90.88uV    671.5mV
1.745ns   -5.323mV   157uV      2.253V
2ns       677mV      -474.8uV   2.602V
2.2ns     1.823V     -2.025mV   2.695V
2.76ns    2.335V     68.71mV    2.718V
3.325ns   2.347V     1.638V     2.719V
3.82ns    2.347V     1.945V     2.719V
10ns      2.348V     1.963V     2.72V
[Rising Waveform]
V_fixture = 3.3V
V_fixture_min = 2.97V
V_fixture_max = 3.63V
R_fixture = 150Ohm
C_fixture = 0F
|   Time   V(typ)   V(min)   V(max)
0s        942.9mV    980.3mV    907.7mV
1.33ns    942.9mV    980.3mV    986.2mV
1.52ns    958.1mV    980.2mV    1.67V
1.705ns   1.057V     980.2mV    3.078V
1.875ns   1.396V     980.1mV    3.427V
2.105ns   2.685V     992.8mV    3.562V
2.425ns   3.177V     1.122V     3.604V
3.145ns   3.283V     2.668V     3.625V
3.555ns   3.293V     2.896V     3.628V
10ns      3.3V       2.97V      3.63V
[Falling Waveform]
|Gnd
V_fixture = 0V
V_fixture_min = 0V
V_fixture_max = 0V
R_fixture = 150Ohm
C_fixture = 0F
|   Time   V(typ)   V(min)   V(max)
0s        2.348V     1.963V     2.72V
1.045ns   2.348V     1.963V     2.72V
1.24ns    2.348V     1.963V     2.587V
1.335ns   2.339V     1.963V     2.267V
1.63ns    2.03V      1.963V     411mV
2.005ns   451.2mV    1.9V       100.5mV
2.24ns    172mV      1.683V     54.23mV
2.73ns    50.76mV    503.5mV    18.24mV
3.3ns     17.02mV    89.24mV    7.295mV
10ns      99.77uV    253uV      47.64uV
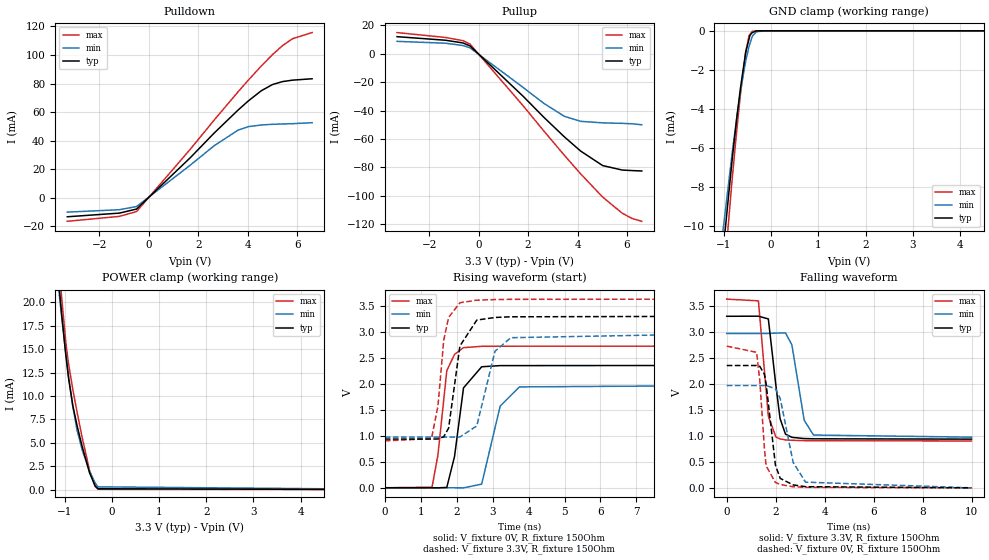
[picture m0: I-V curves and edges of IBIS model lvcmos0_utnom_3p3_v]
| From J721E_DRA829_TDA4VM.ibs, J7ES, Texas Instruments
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|   utnom_3p3_v
[Model]   lvcmos0_utnom_3p3_v
Model_type   I/O
Polarity   Non-Inverting
Enable   Active-High
Vinl = 0
Vinh = 0.8
Vmeas = 1.65
Vref = 3.3
Cref = 2pF
Rref = 100000
|   typ   min   max
C_comp   1.372pF   1.338pF   1.409pF
[Voltage Range]   3.3   2.97   3.63
[Temperature Range]   27   150   -40
[Pullup Reference]   3.3   2.97   3.63
[Pulldown Reference]   0   0   0
[Power Clamp Reference]   3.3   2.97   3.63
[GND Clamp Reference]   0   0   0
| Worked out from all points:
|   slope of the pulldown table from 0 to 0.495 V, typ, clamps not added: 59.5 ohm
|   slope of the pullup table from 0 to 0.495 V, typ, clamps not added: 60.4 ohm
|   GND clamp passes 1 mA (typ) near -0.53 V on its own axis
|   POWER clamp passes 1 mA (typ) near -0.41 V on its own axis
|   falling waveform, V_fixture 3.3V, R_fixture 150Ohm: 20-80 % time 302ps typ, 385ps min, 255ps max; typ from 3.3 V to 0.937 V
|   rising waveform, V_fixture 0V, R_fixture 150Ohm: 20-80 % time 272ps typ, 363ps min, 246ps max; typ from 0 V to 2.35 V
|   rising waveform, V_fixture 3.3V, R_fixture 150Ohm: 20-80 % time 265ps typ, 392ps min, 246ps max; typ from 0.937 V to 3.3 V
|   falling waveform, V_fixture 0V, R_fixture 150Ohm: 20-80 % time 336ps typ, 550ps min, 250ps max; typ from 2.35 V to 0 V
[Pulldown]
|   Voltage   I(typ)   I(min)   I(max)
-3.3V     -13.37mA   -10.11mA   -16.54mA
-1.191V   -10.8mA    -8.417mA   -13.08mA
-498.3mV  -7.942mA   -6.185mA   -9.7mA
1.67V     27.96mA    22.75mA    33.88mA
2.64V     45.3mA     36.41mA    54.42mA
3.61V     61.47mA    47.39mA    74.26mA
4.026V    67.88mA    49.78mA    82.46mA
4.541V    74.88mA    50.96mA    92.2mA
4.996V    79.27mA    51.42mA    100.2mA
5.402V    81.34mA    51.66mA    106.5mA
5.808V    82.36mA    51.85mA    111.4mA
6.6V      83.33mA    52.54mA    115.7mA
[GND Clamp]
|   Voltage   I(typ)   I(min)   I(max)
-3.3V     -92.62mA   -62.37mA   -137.3mA
-1.558V   -24.44mA   -21.27mA   -28.6mA
-825mV    -6.576mA   -6.239mA   -7.571mA
-726mV    -4.419mA   -4.397mA   -5.03mA
-646.8mV  -2.873mA   -3.062mA   -3.168mA
-537.9mV  -1.081mA   -1.53mA    -1.069mA
-468.6mV  -411.5uA   -799.9uA   -249.5uA
-448.8mV  -222uA     -649.4uA   -177.8uA
-399.3mV  -88.26uA   -273.2uA   -22.86uA
-310.2mV  -2.831uA   -44.92uA   -952.2nA
-132mV    -55.98nA   -1.517uA   -88.26nA
6.6V      0A         0A         0A
[Pullup]
|   Voltage   I(typ)   I(min)   I(max)
-3.3V     12.08mA    8.775mA    14.97mA
-1.34V    9.56mA     7.468mA    11.51mA
-636.9mV  7.668mA    5.851mA    9.274mA
-349.8mV  5.581mA    4.223mA    6.858mA
1.808V    -30.08mA   -23.85mA   -36.8mA
2.64V     -44.8mA    -34.98mA   -54.47mA
3.472V    -58.63mA   -44.09mA   -71.64mA
4.125V    -68.55mA   -47.61mA   -84.62mA
5.016V    -78.81mA   -48.69mA   -101mA
5.808V    -81.96mA   -49.05mA   -112.4mA
6.204V    -82.33mA   -49.33mA   -116.1mA
6.6V      -82.63mA   -50.05mA   -118.1mA
[POWER Clamp]
|   Voltage   I(typ)   I(min)   I(max)
-3.3V     165.9mA    145.4mA    188.3mA
-1.112V   21.57mA    20.89mA    23.69mA
-1.063V   18.87mA    18.55mA    20.64mA
-973.5mV  14.41mA    14.56mA    15.79mA
-914.1mV  11.87mA    12.11mA    13.39mA
-825mV    8.991mA    8.884mA    10.71mA
-735.9mV  6.868mA    6.368mA    8.325mA
-627mV    4.603mA    4.244mA    5.577mA
-468.6mV  1.77mA     1.94mA     2.021mA
-349.8mV  384.3uA    698.9uA    308.4uA
-290.4mV  90.02uA    296uA      37.21uA
6.6V      0A         0A         0A
[Ramp]
R_load = 150
|   typ   min   max
dV/dt_r   1.4119/2.71592e-10   1.18081/3.62845e-10   1.63544/2.46128e-10
dV/dt_f   1.41742/3.03093e-10   1.19685/3.86158e-10   1.63641/2.55541e-10
[Falling Waveform]
V_fixture = 3.3V
V_fixture_min = 2.97V
V_fixture_max = 3.63V
R_fixture = 150Ohm
C_fixture = 0F
|   Time   V(typ)   V(min)   V(max)
0s        3.3V       2.97V      3.63V
1.295ns   3.302V     2.97V      3.597V
1.7ns     3.249V     2.97V      1.377V
2.01ns    1.962V     2.976V     976.2mV
2.18ns    1.33V      2.979V     941.7mV
2.4ns     1.034V     2.98V      922.7mV
2.66ns    972.3mV    2.754V     915.2mV
3.165ns   948.1mV    1.3V       908.4mV
3.545ns   943.5mV    1.016V     906.1mV
10ns      937.5mV    974.9mV    902.6mV
[Rising Waveform]
V_fixture = 0V
V_fixture_min = 0V
V_fixture_max = 0V
R_fixture = 150Ohm
C_fixture = 0F
|   Time   V(typ)   V(min)   V(max)
0s        111.7uV    272.2uV    57.55uV
1.315ns   68.75uV    249.6uV    11.1mV
1.48ns    -1.26mV    114.4uV    638.9mV
1.725ns   6.096mV    161.1uV    2.254V
1.94ns    601.3mV    -6.586uV   2.567V
2.19ns    1.922V     -1.898mV   2.696V
2.695ns   2.328V     70.07mV    2.722V
3.21ns    2.351V     1.572V     2.723V
3.745ns   2.351V     1.941V     2.724V
10ns      2.353V     1.968V     2.726V
[Rising Waveform]
V_fixture = 3.3V
V_fixture_min = 2.97V
V_fixture_max = 3.63V
R_fixture = 150Ohm
C_fixture = 0F
|   Time   V(typ)   V(min)   V(max)
0s        937.5mV    974.9mV    902.6mV
1.3ns     937.5mV    974.9mV    945.1mV
1.48ns    938.6mV    974.8mV    1.578V
1.64ns    982mV      974.8mV    2.839V
1.775ns   1.147V     974.9mV    3.279V
2.09ns    2.729V     976.8mV    3.56V
2.56ns    3.227V     1.191V     3.61V
3.065ns   3.277V     2.626V     3.622V
3.505ns   3.29V      2.888V     3.626V
10ns      3.3V       2.97V      3.63V
[Falling Waveform]
|Gnd
V_fixture = 0V
V_fixture_min = 0V
V_fixture_max = 0V
R_fixture = 150Ohm
C_fixture = 0F
|   Time   V(typ)   V(min)   V(max)
0s        2.353V     1.968V     2.726V
1.22ns    2.353V     1.968V     2.607V
1.35ns    2.339V     1.968V     2.07V
1.54ns    2.183V     1.968V     755.8mV
1.61ns    1.995V     1.968V     421.8mV
1.99ns    435.2mV    1.908V     103.8mV
2.185ns   182.3mV    1.719V     64.4mV
2.715ns   56.82mV    488mV      21.45mV
3.22ns    22.64mV    110mV      9.56mV
10ns      111.6uV    272.2uV    57.54uV
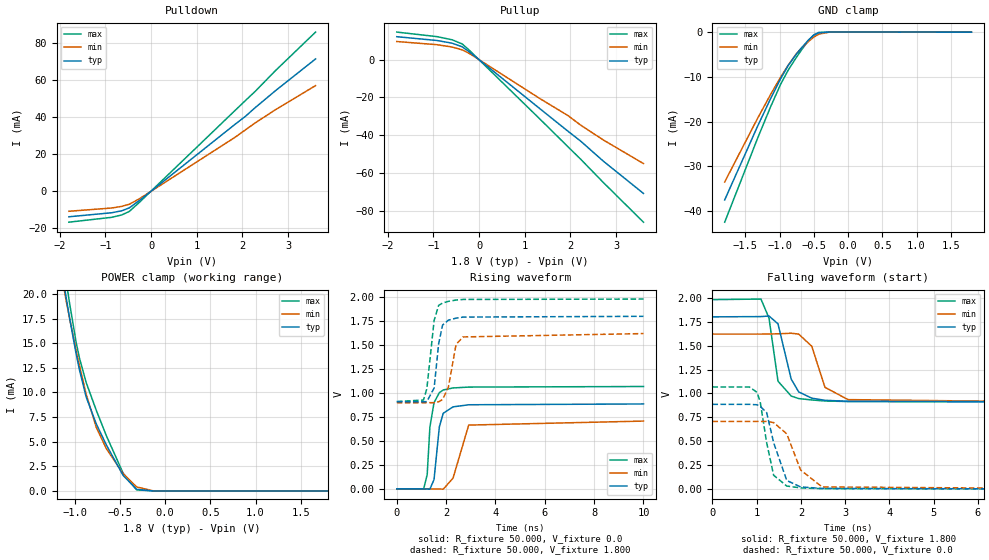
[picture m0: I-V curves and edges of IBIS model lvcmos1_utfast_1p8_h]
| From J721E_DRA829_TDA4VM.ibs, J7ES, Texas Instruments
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|   utfast_1p8_h
[Model]   lvcmos1_utfast_1p8_h
Model_type I/O
Polarity   Non-Inverting
Enable   Active-High
Vinl = 0
Vinh = 0.8
Vmeas = 0.9
Vref = 1.8
Cref = 2pF
Rref = 100000
|   typ   min   max
C_comp   2.386pF   2.296pF   2.449pF
[Voltage Range]   1.8   1.62   1.98
[Temperature Range]   27   150   -40
[Pullup Reference]   1.8   1.62   1.98
[Pulldown Reference]   0   0   0
[Power Clamp Reference]   1.8   1.62   1.98
[GND Clamp Reference]   0   0   0
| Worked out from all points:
|   slope of the pulldown table from 0 to 0.27 V, typ, clamps not added: 51.1 ohm
|   slope of the pullup table from 0 to 0.27 V, typ, clamps not added: 51.6 ohm
|   GND clamp passes 1 mA (typ) near -0.52 V on its own axis
|   POWER clamp passes 1 mA (typ) near -0.42 V on its own axis
|   rising waveform, R_fixture 50.000, V_fixture 0.0: 20-80 % time 186ps typ, 244ps min, 230ps max; typ from 0 V to 0.886 V
|   rising waveform, R_fixture 50.000, V_fixture 1.800: 20-80 % time 219ps typ, 299ps min, 272ps max; typ from 0.909 V to 1.8 V
|   falling waveform, R_fixture 50.000, V_fixture 1.800: 20-80 % time 237ps typ, 316ps min, 200ps max; typ from 1.8 V to 0.909 V
|   falling waveform, R_fixture 50.000, V_fixture 0.0: 20-80 % time 320ps typ, 399ps min, 247ps max; typ from 0.886 V to 0 V
[Pulldown]
|Voltage   I(typ)   I(min)   I(max)
-1.8V     -13.81mA   -10.84mA   -16.73mA
-863mV    -11.64mA   -9.074mA   -14.1mA
-643mV    -10.58mA   -8.195mA   -12.83mA
-478mV    -9.019mA   -7.058mA   -10.94mA
-257mV    -5.042mA   -4.115mA   -6.035mA
1.837V    36.09mA    29.08mA    43.55mA
2.057V    40.24mA    32.96mA    48.74mA
2.278V    45.07mA    36.83mA    53.85mA
2.718V    54.15mA    43.91mA    64.96mA
3.6V      71.37mA    56.98mA    85.85mA
[Pullup]
|Voltage   I(typ)   I(min)   I(max)
-1.8V     12.14mA    9.589mA    14.58mA
-918mV    10.13mA    7.907mA    12.17mA
-588mV    8.699mA    6.67mA     10.49mA
-367mV    6.789mA    5.164mA    8.295mA
-202mV    3.919mA    3.122mA    4.735mA
1.341V    -26.13mA   -20.74mA   -31.64mA
1.947V    -37.88mA   -29.6mA    -46.11mA
2.222V    -43.07mA   -34.61mA   -52.61mA
2.718V    -53.66mA   -42.47mA   -64.94mA
3.6V      -70.82mA   -55.01mA   -86.02mA
[GND_clamp]
|Voltage   I(typ)   I(min)   I(max)
-1.8V     -37.5mA    -33.49mA   -42.48mA
-1.318V   -20.97mA   -19.21mA   -23.65mA
-1.132V   -14.92mA   -13.99mA   -16.76mA
-984mV    -10.42mA   -10.06mA   -11.66mA
-872mV    -7.442mA   -7.36mA    -8.464mA
-761mV    -5.052mA   -4.998mA   -5.817mA
-687mV    -3.663mA   -3.691mA   -4.162mA
-575mV    -1.728mA   -2.058mA   -1.807mA
-501mV    -716.8uA   -1.141mA   -632.9uA
-427mV    -157.5uA   -468.3uA   -83.58uA
-278mV    -1.328uA   -23.76uA   -249.6nA
1.8V      0A         0A         0A
[POWER_clamp]
|Voltage   I(typ)   I(min)   I(max)
-1.8V     63.27mA    56.65mA    71.18mA
-1.095V   19.71mA    19.39mA    21.45mA
-1.058V   17.7mA     17.64mA    19.19mA
-984mV    13.96mA    14.29mA    15.13mA
-946mV    12.28mA    12.71mA    13.48mA
-872mV    9.531mA    9.825mA    11mA
-761mV    6.815mA    6.464mA    8.201mA
-649mV    4.665mA    4.293mA    5.607mA
-464mV    1.58mA     1.753mA    1.805mA
-315mV    158.8uA    405.7uA    109uA
-130mV    309.5nA    7.673uA    148.4nA
1.8V      0A         0A         0A
[Ramp]
| variable   typ   min   max
dV/dt_r   0.532/0.186n   0.424/0.242n   0.641/0.229n
dV/dt_f   0.535/0.237n   0.432/0.315n   0.641/0.199n
R_load = 50.000
[Rising Waveform]
R_fixture= 50.000
V_fixture= 0.0
V_fixture_min= 0.0
V_fixture_max= 0.0
|time   V(typ)   V(min)   V(max)
0s        765.5nV    18.05uV    1.182uV
1.09ns    99.63uV    18.63uV    -285.8uV
1.233ns   -1.772mV   21.21uV    150mV
1.342ns   -2.702mV   -49.38uV   644.2mV
1.51ns    97.37mV    -109.5uV   899.9mV
1.726ns   648.3mV    -1.615mV   1.004V
1.884ns   789.1mV    -2.425mV   1.032V
2.28ns    855.6mV    111.9mV    1.053V
2.914ns   877.6mV    665.6mV    1.062V
10ns      886mV      707.4mV    1.068V
[Rising Waveform]
R_fixture= 50.000
V_fixture= 1.800
V_fixture_min= 1.620
V_fixture_max= 1.980
|time   V(typ)   V(min)   V(max)
0s        909.1mV    899.3mV    911.4mV
1.083ns   909.2mV    899.3mV    926.9mV
1.219ns   911.1mV    899.3mV    1.045V
1.514ns   1.052V     899.3mV    1.758V
1.697ns   1.514V     908.8mV    1.914V
1.856ns   1.709V     932.1mV    1.938V
2.091ns   1.76V      1.06V      1.956V
2.403ns   1.781V     1.507V     1.97V
2.686ns   1.792V     1.585V     1.976V
10ns      1.8V       1.62V      1.98V
[Falling Waveform]
R_fixture= 50.000
V_fixture= 1.800
V_fixture_min= 1.620
V_fixture_max= 1.980
|time   V(typ)   V(min)   V(max)
0s        1.8V       1.62V      1.98V
1.098ns   1.803V     1.62V      1.986V
1.28ns    1.809V     1.621V     1.787V
1.483ns   1.727V     1.623V     1.128V
1.781ns   1.15V      1.629V     972.9mV
1.951ns   1.016V     1.62V      946.5mV
2.246ns   950.6mV    1.493V     931.9mV
2.544ns   928.6mV    1.064V     921.2mV
3.066ns   917.7mV    935.6mV    915.5mV
10ns      909.1mV    899.4mV    911.4mV
[Falling Waveform]
R_fixture= 50.000
V_fixture= 0.0
V_fixture_min= 0.0
V_fixture_max= 0.0
|time   V(typ)   V(min)   V(max)
0s        886mV      707.5mV    1.068V
834ps     885.9mV    707.5mV    1.068V
1.008ns   881.9mV    707.4mV    1.012V
1.08ns    866.4mV    707.5mV    914.5mV
1.227ns   799.9mV    707.6mV    485.9mV
1.384ns   486.9mV    695.9mV    145.8mV
1.681ns   90.56mV    578.4mV    32.75mV
1.994ns   23.53mV    200.2mV    13.2mV
2.479ns   7.554mV    23.44mV    5.148mV
10ns      30.93uV    87.62uV    13.05uV
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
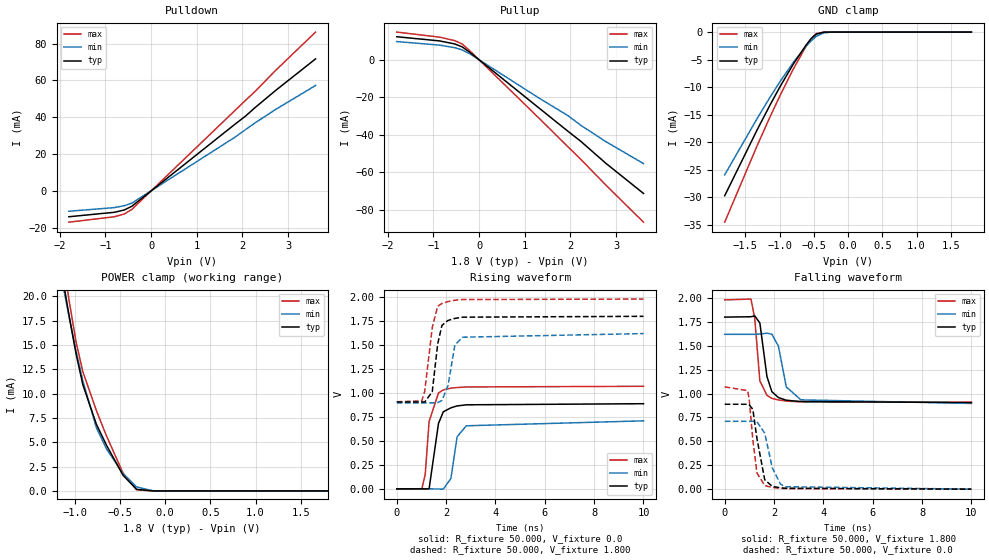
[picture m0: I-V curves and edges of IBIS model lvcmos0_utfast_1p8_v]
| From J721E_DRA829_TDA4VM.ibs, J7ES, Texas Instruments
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|   utfast_1p8_v
[Model]   lvcmos0_utfast_1p8_v
Model_type I/O
Polarity   Non-Inverting
Enable   Active-High
Vinl = 0
Vinh = 0.8
Vmeas = 0.9
Vref = 1.8
Cref = 2pF
Rref = 100000
|   typ   min   max
C_comp   2.420pF   2.311pF   2.500pF
[Voltage Range]   1.8   1.62   1.98
[Temperature Range]   27   150   -40
[Pullup Reference]   1.8   1.62   1.98
[Pulldown Reference]   0   0   0
[Power Clamp Reference]   1.8   1.62   1.98
[GND Clamp Reference]   0   0   0
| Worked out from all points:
|   slope of the pulldown table from 0 to 0.27 V, typ, clamps not added: 50.8 ohm
|   slope of the pullup table from 0 to 0.27 V, typ, clamps not added: 51.4 ohm
|   GND clamp passes 1 mA (typ) near -0.52 V on its own axis
|   POWER clamp passes 1 mA (typ) near -0.42 V on its own axis
|   rising waveform, R_fixture 50.000, V_fixture 0.0: 20-80 % time 214ps typ, 265ps min, 264ps max; typ from 0 V to 0.888 V
|   rising waveform, R_fixture 50.000, V_fixture 1.800: 20-80 % time 251ps typ, 282ps min, 317ps max; typ from 0.906 V to 1.8 V
|   falling waveform, R_fixture 50.000, V_fixture 1.800: 20-80 % time 258ps typ, 353ps min, 209ps max; typ from 1.8 V to 0.906 V
|   falling waveform, R_fixture 50.000, V_fixture 0.0: 20-80 % time 332ps typ, 435ps min, 260ps max; typ from 0.888 V to 0 V
[Pulldown]
|Voltage   I(typ)   I(min)   I(max)
-1.8V     -13.91mA   -10.93mA   -16.86mA
-808mV    -11.5mA    -8.96mA    -13.92mA
-588mV    -10.25mA   -7.939mA   -12.44mA
-422mV    -8.232mA   -6.523mA   -9.936mA
1.837V    36.29mA    29.26mA    43.77mA
2.057V    40.47mA    33.16mA    48.98mA
2.278V    45.32mA    37.03mA    54.11mA
2.718V    54.42mA    44.15mA    65.27mA
3.6V      71.7mA     57.28mA    86.22mA
[Pullup]
|Voltage   I(typ)   I(min)   I(max)
-1.8V     12.22mA    9.652mA    14.69mA
-863mV    9.996mA    7.764mA    12mA
-533mV    8.393mA    6.408mA    10.16mA
-367mV    6.813mA    5.187mA    8.342mA
-202mV    3.939mA    3.136mA    4.761mA
1.286V    -25.18mA   -20.01mA   -30.47mA
1.947V    -38.08mA   -29.76mA   -46.35mA
2.222V    -43.3mA    -34.8mA    -52.88mA
2.773V    -55.04mA   -43.54mA   -66.62mA
3.6V      -71.15mA   -55.26mA   -86.44mA
[GND_clamp]
|Voltage   I(typ)   I(min)   I(max)
-1.8V     -29.72mA   -25.92mA   -34.52mA
-1.318V   -17.54mA   -15.51mA   -20.38mA
-1.132V   -13.09mA   -11.7mA    -15.22mA
-984mV    -9.729mA   -8.821mA   -11.3mA
-798mV    -5.796mA   -5.487mA   -6.696mA
-612mV    -2.352mA   -2.574mA   -2.564mA
-538mV    -1.178mA   -1.583mA   -1.166mA
-464mV    -371.7uA   -772.4uA   -275.5uA
-353mV    -16.33uA   -130uA     -4.379uA
-241mV    -394.3nA   -10.93uA   -119.1nA
1.8V      0A         0A         0A
[POWER_clamp]
|Voltage   I(typ)   I(min)   I(max)
-1.8V     63.47mA    56.87mA    71.37mA
-1.132V   21.93mA    21.29mA    24mA
-1.095V   19.85mA    19.49mA    21.65mA
-1.058V   17.84mA    17.74mA    19.39mA
-984mV    14.08mA    14.39mA    15.3mA
-909mV    10.91mA    11.31mA    12.25mA
-761mV    6.887mA    6.531mA    8.298mA
-649mV    4.716mA    4.334mA    5.678mA
-464mV    1.599mA    1.771mA    1.827mA
-315mV    160.9uA    409.8uA    112.2uA
-130mV    304.4nA    7.74uA     148.3nA
1.8V      0A         0A         0A
[Ramp]
| variable   typ   min   max
dV/dt_r   0.533/0.214n   0.426/0.263n   0.642/0.265n
dV/dt_f   0.536/0.258n   0.434/0.353n   0.643/0.210n
R_load = 50.000
[Rising Waveform]
R_fixture= 50.000
V_fixture= 0.0
|time   V(typ)   V(min)   V(max)
0s        757nV      17.91uV    1.169uV
1.016ns   121.7uV    15.26uV    1.026mV
1.152ns   -787.7uV   31.01uV    147.7mV
1.31ns    855uV      19.68uV    703.1mV
1.691ns   682.7mV    -1.648mV   1.001V
1.886ns   803.8mV    -3.215mV   1.032V
2.195ns   845.7mV    109.5mV    1.051V
2.445ns   865.1mV    544.3mV    1.057V
2.82ns    876.8mV    658mV      1.063V
10ns      888.3mV    709.6mV    1.07V
[Rising Waveform]
R_fixture= 50.000
V_fixture= 1.800
V_fixture_min= 1.620
V_fixture_max= 1.980
|time   V(typ)   V(min)   V(max)
0s        906.5mV    896.8mV    908.6mV
1.016ns   906.5mV    896.8mV    917.9mV
1.134ns   906.2mV    896.8mV    1.021V
1.438ns   1.013V     896.8mV    1.682V
1.658ns   1.512V     899.5mV    1.906V
1.831ns   1.706V     921.9mV    1.934V
2.075ns   1.757V     1.074V     1.954V
2.354ns   1.778V     1.5V       1.968V
2.665ns   1.791V     1.582V     1.975V
10ns      1.8V       1.62V      1.98V
[Falling Waveform]
R_fixture= 50.000
V_fixture= 1.800
V_fixture_min= 1.620
V_fixture_max= 1.980
|time   V(typ)   V(min)   V(max)
0s        1.8V       1.62V      1.98V
1.065ns   1.804V     1.62V      1.989V
1.218ns   1.813V     1.62V      1.787V
1.425ns   1.739V     1.623V     1.133V
1.713ns   1.178V     1.632V     982.2mV
1.912ns   1.02V      1.621V     949.3mV
2.177ns   958.6mV    1.497V     934mV
2.496ns   930.6mV    1.07V      921.8mV
3.088ns   916.5mV    934.5mV    913.3mV
10ns      906.5mV    896.8mV    908.6mV
[Falling Waveform]
R_fixture= 50.000
V_fixture= 0.0
V_fixture_min= 0.0
V_fixture_max= 0.0
|time   V(typ)   V(min)   V(max)
0s        888.3mV    709.6mV    1.07V
929ps     888.3mV    709.6mV    1.031V
990ps     882.2mV    709.6mV    949.6mV
1.141ns   835.3mV    709.6mV    515.7mV
1.307ns   530.3mV    704.8mV    169.6mV
1.622ns   98.61mV    587.1mV    37.62mV
1.928ns   29.32mV    224.5mV    18.31mV
2.265ns   13.93mV    52.29mV    8.618mV
2.452ns   9.649mV    25.77mV    6.263mV
10ns      39.84uV    105uV      22.22uV
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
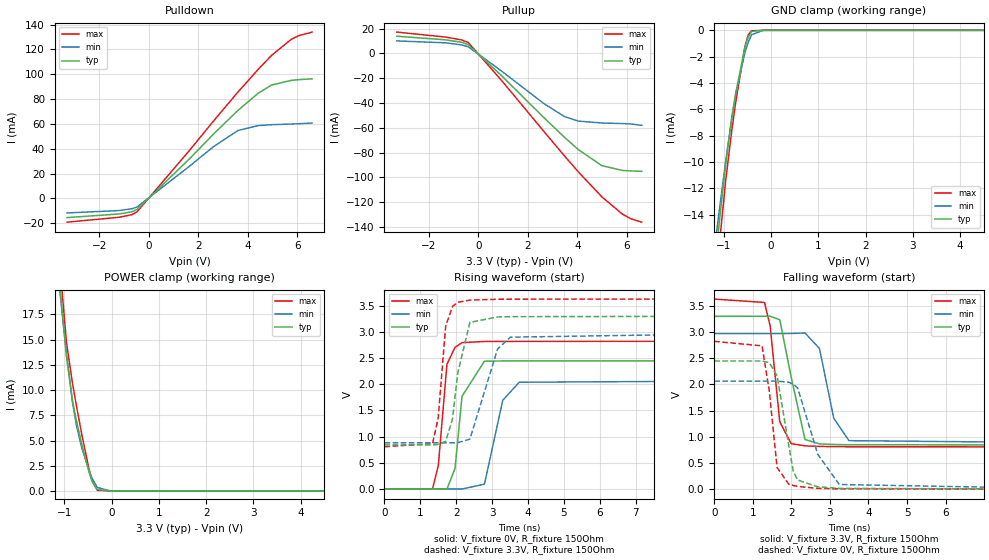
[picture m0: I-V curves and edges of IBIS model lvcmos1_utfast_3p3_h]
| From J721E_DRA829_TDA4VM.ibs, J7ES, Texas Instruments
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|   utfast_3p3_h
[Model]   lvcmos1_utfast_3p3_h
Model_type   I/O
Polarity   Non-Inverting
Enable   Active-High
Vinl = 0
Vinh = 0.8
Vmeas = 1.65
Vref = 3.3
Cref = 2pF
Rref = 100000
|   typ   min   max
C_comp   1.362pF	1.327pF   1.397pF
[Voltage Range]   3.3   2.97   3.63
[Temperature Range]   27   150   -40
[Pullup Reference]   3.3   2.97   3.63
[Pulldown Reference]   0   0   0
[Power Clamp Reference]   3.3   2.97   3.63
[GND Clamp Reference]   0   0   0
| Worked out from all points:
|   slope of the pulldown table from 0 to 0.495 V, typ, clamps not added: 51.4 ohm
|   slope of the pullup table from 0 to 0.495 V, typ, clamps not added: 52.2 ohm
|   GND clamp passes 1 mA (typ) near -0.53 V on its own axis
|   POWER clamp passes 1 mA (typ) near -0.42 V on its own axis
|   falling waveform, V_fixture 3.3V, R_fixture 150Ohm: 20-80 % time 261ps typ, 335ps min, 222ps max; typ from 3.3 V to 0.843 V
|   rising waveform, V_fixture 0V, R_fixture 150Ohm: 20-80 % time 221ps typ, 294ps min, 192ps max; typ from 0 V to 2.45 V
|   rising waveform, V_fixture 3.3V, R_fixture 150Ohm: 20-80 % time 250ps typ, 432ps min, 196ps max; typ from 0.843 V to 3.3 V
|   falling waveform, V_fixture 0V, R_fixture 150Ohm: 20-80 % time 325ps typ, 525ps min, 238ps max; typ from 2.45 V to 0 V
[Pulldown]
|   Voltage   I(typ)   I(min)   I(max)
-3.3V     -15.43mA   -11.68mA   -19.11mA
-1.191V   -12.48mA   -9.724mA   -15.13mA
-686.4mV  -10.75mA   -8.303mA   -13.07mA
-478.5mV  -8.949mA   -6.944mA   -10.93mA
1.67V     32.33mA    26.29mA    39.19mA
2.64V     52.28mA    42.02mA    62.85mA
3.61V     70.93mA    54.7mA     85.74mA
4.422V    84.72mA    58.64mA    103.9mA
4.966V    91.3mA     59.36mA    115.2mA
5.768V    95.08mA    59.89mA    128.2mA
6.056V    95.6mA     60.14mA    131mA
6.6V      96.27mA    60.7mA     133.9mA
[GND Clamp]
|   Voltage   I(typ)   I(min)   I(max)
-3.3V     -115mA     -82.92mA   -162mA
-1.439V   -26.2mA    -23.54mA   -29.78mA
-1.073V   -13.92mA   -13.13mA   -15.6mA
-1.023V   -12.29mA   -11.74mA   -13.78mA
-953.7mV  -10.1mA    -9.845mA   -11.3mA
-825mV    -6.567mA   -6.573mA   -7.512mA
-745.8mV  -4.803mA   -4.841mA   -5.48mA
-547.8mV  -1.238mA   -1.641mA   -1.201mA
-478.5mV  -500.7uA   -900.6uA   -330.8uA
-409.2mV  -82.91uA   -334.6uA   -33.01uA
-161.7mV  -81.29nA   -2.013uA   -109nA
6.6V      0A         0A         0A
[Pullup]
|   Voltage   I(typ)   I(min)   I(max)
-3.3V     13.97mA    10.17mA    17.3mA
-1.33V    11.04mA    8.628mA    13.29mA
-686.4mV  9.112mA    6.981mA    11mA
-409.2mV  7.224mA    5.438mA    8.837mA
937.2mV   -17.98mA   -14.22mA   -21.82mA
2.64V     -51.69mA   -40.39mA   -62.84mA
3.472V    -67.63mA   -50.91mA   -82.63mA
4.036V    -77.61mA   -54.63mA   -95.6mA
4.986V    -90.61mA   -56.15mA   -115.8mA
5.818V    -94.48mA   -56.6mA    -129.8mA
6.154V    -94.85mA   -56.93mA   -133.5mA
6.6V      -95.23mA   -58.04mA   -136.3mA
[POWER Clamp]
|   Voltage   I(typ)   I(min)   I(max)
-3.3V     170.4mA    144.6mA    202.9mA
-1.132V   22.5mA     21.65mA    24.88mA
-1.092V   20.32mA    19.77mA    22.37mA
-953.7mV  13.38mA    13.61mA    14.77mA
-825mV    8.921mA    8.794mA    10.65mA
-745.8mV  7.05mA     6.572mA    8.54mA
-627mV    4.601mA    4.228mA    5.562mA
-478.5mV  1.923mA    2.067mA    2.21mA
-409.2mV  923.3uA    1.226mA    996.6uA
-300.3mV  125.6uA    342.8uA    56.71uA
-23.1mV   2.367nA    847.8nA    21nA
6.6V      0A         0A         0A
[Ramp]
R_load = 150
|   typ   min   max
dV/dt_r   1.46891/2.19993e-10   1.23783/2.9256e-10   1.69297/1.91724e-10
dV/dt_f   1.47406/2.60386e-10   1.25249/3.32414e-10   1.69406/2.21517e-10
[Falling Waveform]
V_fixture = 3.3V
V_fixture_min = 2.97V
V_fixture_max = 3.63V
R_fixture = 150Ohm
C_fixture = 0F
|   Time   V(typ)   V(min)   V(max)
0s        3.3V       2.97V      3.63V
1.305ns   3.301V     2.97V      3.565V
1.45ns    3.304V     2.97V      3.12V
1.7ns     3.236V     2.97V      1.288V
1.995ns   2.144V     2.973V     869.6mV
2.355ns   948.4mV    2.982V     826.3mV
2.73ns    864.5mV    2.686V     816.5mV
3.1ns     853.1mV    1.357V     811.9mV
3.495ns   848.4mV    926.3mV    809.7mV
10ns      843.1mV    882.3mV    806.5mV
[Rising Waveform]
V_fixture = 0V
V_fixture_min = 0V
V_fixture_max = 0V
R_fixture = 150Ohm
C_fixture = 0F
|   Time   V(typ)   V(min)   V(max)
0s        87.27uV    239uV      42.26uV
1.34ns    -6.131uV   207uV      3.124mV
1.5ns     -1.91mV    94.45uV    450.6mV
1.74ns    -4.595mV   145.4uV    2.383V
1.965ns   393mV      -201.9uV   2.707V
2.16ns    1.771V     -1.713mV   2.797V
2.785ns   2.442V     90.94mV    2.819V
3.295ns   2.447V     1.694V     2.82V
3.755ns   2.447V     2.04V      2.821V
10ns      2.448V     2.063V     2.822V
[Rising Waveform]
V_fixture = 3.3V
V_fixture_min = 2.97V
V_fixture_max = 3.63V
R_fixture = 150Ohm
C_fixture = 0F
|   Time   V(typ)   V(min)   V(max)
0s        843.1mV    882.3mV    806.5mV
1.34ns    843mV      882.2mV    867.5mV
1.495ns   850.1mV    882.1mV    1.35V
1.705ns   911.4mV    882.1mV    3.112V
1.895ns   1.336V     882mV      3.489V
2.04ns    2.213V     883.9mV    3.568V
2.38ns    3.185V     951.6mV    3.61V
3.15ns    3.287V     2.673V     3.626V
3.505ns   3.294V     2.901V     3.628V
10ns      3.3V       2.97V      3.63V
[Falling Waveform]
|Gnd
V_fixture = 0V
V_fixture_min = 0V
V_fixture_max = 0V
R_fixture = 150Ohm
C_fixture = 0F
|   Time   V(typ)   V(min)   V(max)
0s        2.448V     2.063V     2.822V
1.24ns    2.448V     2.063V     2.737V
1.43ns    2.414V     2.063V     1.87V
1.63ns    2.165V     2.063V     414.2mV
1.93ns    852.8mV    2.042V     97.87mV
2.05ns    341.3mV    2.006V     70.95mV
2.165ns   175.1mV    1.932V     52.24mV
2.685ns   45.91mV    664.9mV    15.12mV
3.245ns   14.73mV    89mV       5.958mV
10ns      87.64uV    239uV      42.25uV
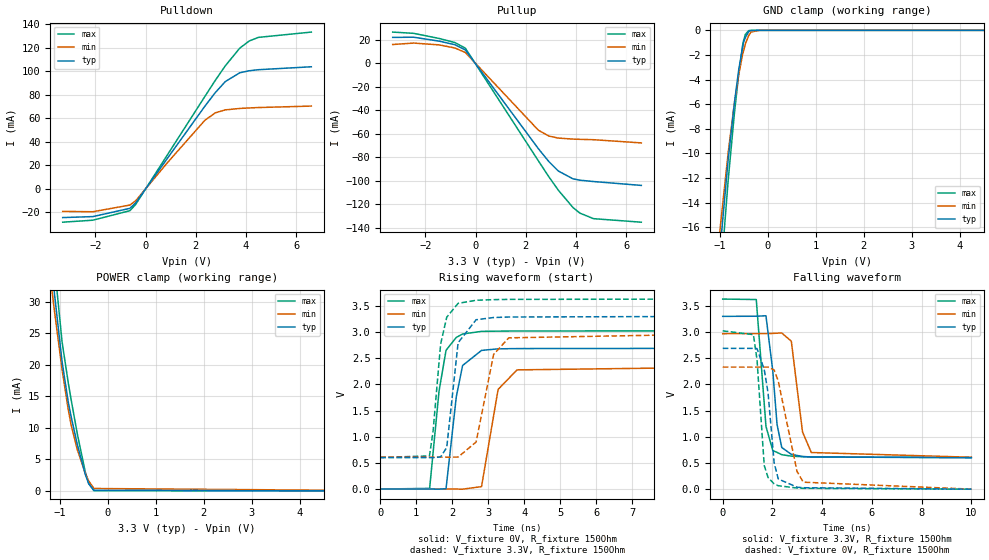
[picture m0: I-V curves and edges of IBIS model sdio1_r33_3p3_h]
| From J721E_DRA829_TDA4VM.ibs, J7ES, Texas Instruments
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|   r33_3p3_h
[Model]   sdio1_r33_3p3_h
Model_type   I/O
Polarity   Non-Inverting
Enable   Active-High
Vinl = 0
Vinh = 0.8
Vmeas = 1.65
Vref = 3.3
Cref = 2pF
Rref = 100000
|   typ   min   max
C_comp   2.627pF   2.35pF   2.844pF
[Voltage Range]   3.3   2.97   3.63
[Temperature Range]   27   150   -40
[Pullup Reference]   3.3   2.97   3.63
[Pulldown Reference]   0   0   0
[Power Clamp Reference]   3.3   2.97   3.63
[GND Clamp Reference]   0   0   0
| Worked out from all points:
|   slope of the pulldown table from 0 to 0.495 V, typ, clamps not added: 33.3 ohm
|   slope of the pullup table from 0 to 0.495 V, typ, clamps not added: 34 ohm
|   GND clamp passes 1 mA (typ) near -0.51 V on its own axis
|   POWER clamp passes 1 mA (typ) near -0.39 V on its own axis
|   falling waveform, V_fixture 3.3V, R_fixture 150Ohm: 20-80 % time 275ps typ, 339ps min, 246ps max; typ from 3.3 V to 0.6 V
|   rising waveform, V_fixture 0V, R_fixture 150Ohm: 20-80 % time 240ps typ, 308ps min, 254ps max; typ from 0 V to 2.69 V
|   rising waveform, V_fixture 3.3V, R_fixture 150Ohm: 20-80 % time 238ps typ, 360ps min, 252ps max; typ from 0.6 V to 3.3 V
|   falling waveform, V_fixture 0V, R_fixture 150Ohm: 20-80 % time 336ps typ, 593ps min, 245ps max; typ from 2.69 V to 0 V
[Pulldown]
|   Voltage   I(typ)   I(min)   I(max)
-3.3V     -24.38mA   -19.12mA   -28.31mA
-2.102V   -23.55mA   -19.43mA   -26.62mA
-627mV    -16.54mA   -13.74mA   -18.54mA
-399.3mV  -12.02mA   -10.22mA   -13.37mA
838.2mV   25.12mA    21.55mA    27.93mA
2.363V    70.39mA    58.42mA    78.7mA
2.779V    82mA       64.74mA    92.43mA
3.175V    91.31mA    67.23mA    104.7mA
3.749V    98.78mA    68.44mA    119.7mA
4.125V    100.5mA    68.87mA    125.8mA
4.491V    101.4mA    69.21mA    128.9mA
6.6V      103.9mA    70.46mA    133.4mA
[GND Clamp]
|   Voltage   I(typ)   I(min)   I(max)
-3.3V     -160mA     -119.4mA   -217mA
-1.043V   -19.85mA   -17.9mA    -22.95mA
-825mV    -10.42mA   -9.877mA   -12.11mA
-696.3mV  -5.885mA   -5.888mA   -6.718mA
-607.2mV  -3.208mA   -3.602mA   -3.571mA
-528mV    -1.443mA   -2.001mA   -1.27mA
-508.2mV  -1.005mA   -1.701mA   -874.2uA
-468.6mV  -582.9uA   -1.101mA   -330.4uA
-399.3mV  -98.27uA   -431.3uA   -25.92uA
-349.8mV  -13.17uA   -132.1uA   -5.149uA
-171.6mV  -86.92nA   -2.806uA   -107.4nA
6.6V      0A         0A         0A
[Pullup]
|   Voltage   I(typ)   I(min)   I(max)
-3.3V     21.97mA    15.92mA    26.49mA
-2.468V   22.13mA    17.15mA    25.43mA
-1.449V   18.78mA    15.59mA    21.05mA
-825mV    15.76mA    12.98mA    17.59mA
-409.2mV  11.34mA    9.13mA     12.85mA
2.501V    -72.75mA   -57.03mA   -83.11mA
2.917V    -83.68mA   -61.97mA   -96.61mA
3.293V    -91.72mA   -63.71mA   -108mA
3.877V    -98.38mA   -64.58mA   -122.8mA
4.155V    -99.56mA   -64.79mA   -127.6mA
4.699V    -100.7mA   -65.1mA    -132.3mA
6.6V      -104mA     -67.83mA   -135.3mA
[POWER Clamp]
|   Voltage   I(typ)   I(min)   I(max)
-3.3V     224.5mA    191.3mA    262.6mA
-1.211V   38.57mA    34.7mA     44.22mA
-1.191V   37.06mA    33.44mA    42.47mA
-1.122V   31.9mA     29.08mA    36.46mA
-953.7mV  20.46mA    19.22mA    23.62mA
-825mV    14.07mA    12.89mA    17.14mA
-765.6mV  11.79mA    10.49mA    14.49mA
-636.9mV  7.377mA    6.549mA    9.056mA
-468.6mV  2.574mA    2.754mA    2.952mA
-399.3mV  1.162mA    1.587mA    1.17mA
-290.4mV  101.1uA    385.8uA    43.49uA
6.6V      0A         0A         0A
[Ramp]
R_load = 150
|   typ   min   max
dV/dt_r   1.61316/2.39024e-10   1.39818/3.0659e-10   1.81343/2.53741e-10
dV/dt_f   1.61988/2.74389e-10   1.41587/3.38839e-10   1.81501/2.45626e-10
[Falling Waveform]
V_fixture = 3.3V
V_fixture_min = 2.97V
V_fixture_max = 3.63V
R_fixture = 150Ohm
C_fixture = 0F
|   Time   V(typ)   V(min)   V(max)
0s        3.3V       2.969V     3.63V
1.35ns    3.302V     2.97V      3.621V
1.74ns    3.311V     2.97V      1.199V
2.015ns   2.254V     2.974V     736.5mV
2.185ns   1.239V     2.979V     702.4mV
2.375ns   795.7mV    2.982V     658.5mV
2.76ns    664.8mV    2.825V     630.8mV
3.21ns    624mV      1.093V     620.1mV
3.565ns   615.5mV    700mV      615.5mV
10ns      599.9mV    609.6mV    604.7mV
[Rising Waveform]
V_fixture = 0V
V_fixture_min = 0V
V_fixture_max = 0V
R_fixture = 150Ohm
C_fixture = 0F
|   Time   V(typ)   V(min)   V(max)
0s        356.1uV    864.9uV    228.3uV
1.37ns    221.6uV    569.7uV    13.01mV
1.63ns    -2.024mV   413.3uV    1.866V
1.825ns   6.295mV    450.6uV    2.651V
2.11ns    1.763V     -322.6uV   2.897V
2.285ns   2.361V     -1.532mV   2.963V
2.81ns    2.649V     46.35mV    3.013V
3.27ns    2.679V     1.903V     3.017V
3.795ns   2.684V     2.277V     3.02V
10ns      2.689V     2.331V     3.023V
[Rising Waveform]
V_fixture = 3.3V
V_fixture_min = 2.97V
V_fixture_max = 3.63V
R_fixture = 150Ohm
C_fixture = 0F
|   Time   V(typ)   V(min)   V(max)
0s        599.9mV    609.6mV    604.7mV
1.365ns   599.8mV    609.4mV    632.8mV
1.465ns   599.7mV    609.3mV    1.101V
1.675ns   613.9mV    609.2mV    2.772V
1.845ns   795.6mV    609.3mV    3.284V
2.16ns    2.796V     610.7mV    3.548V
2.66ns    3.235V     899.2mV    3.607V
3.145ns   3.277V     2.571V     3.619V
3.565ns   3.287V     2.889V     3.624V
10ns      3.3V       2.969V     3.63V
[Falling Waveform]
|Gnd
V_fixture = 0V
V_fixture_min = 0V
V_fixture_max = 0V
R_fixture = 150Ohm
C_fixture = 0F
|   Time   V(typ)   V(min)   V(max)
0s        2.689V     2.331V     3.023V
1.235ns   2.689V     2.331V     2.951V
1.38ns    2.685V     2.331V     2.474V
1.67ns    2.285V     2.331V     452mV
1.825ns   1.835V     2.331V     222mV
2.07ns    500mV      2.275V     100.1mV
2.235ns   195.5mV    2.065V     65.98mV
2.99ns    37.64mV    339.2mV    21.84mV
3.24ns    27.71mV    133.4mV    16.44mV
10ns      353.7uV    865uV      228.7uV
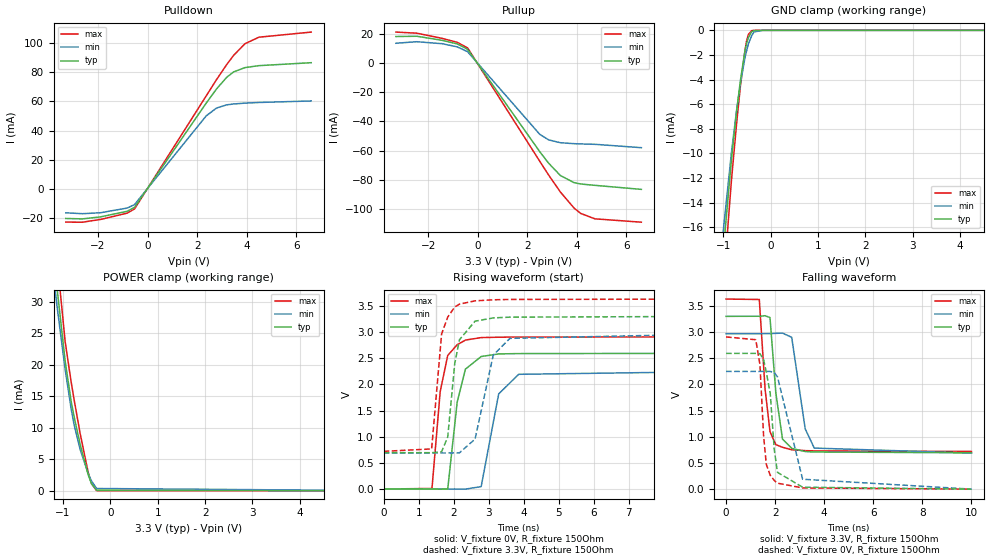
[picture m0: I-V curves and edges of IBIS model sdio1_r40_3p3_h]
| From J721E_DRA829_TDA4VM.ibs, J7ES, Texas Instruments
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|   r40_3p3_h
[Model]   sdio1_r40_3p3_h
Model_type   I/O
Polarity   Non-Inverting
Enable   Active-High
Vinl = 0
Vinh = 0.8
Vmeas = 1.65
Vref = 3.3
Cref = 2pF
Rref = 100000
|   typ   min   max
C_comp   2.766pF   2.508pF   2.963pF
[Voltage Range]   3.3   2.97   3.63
[Temperature Range]   27   150   -40
[Pullup Reference]   3.3   2.97   3.63
[Pulldown Reference]   0   0   0
[Power Clamp Reference]   3.3   2.97   3.63
[GND Clamp Reference]   0   0   0
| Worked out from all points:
|   slope of the pulldown table from 0 to 0.495 V, typ, clamps not added: 39.9 ohm
|   slope of the pullup table from 0 to 0.495 V, typ, clamps not added: 40.8 ohm
|   GND clamp passes 1 mA (typ) near -0.50 V on its own axis
|   POWER clamp passes 1 mA (typ) near -0.39 V on its own axis
|   falling waveform, V_fixture 3.3V, R_fixture 150Ohm: 20-80 % time 284ps typ, 374ps min, 260ps max; typ from 3.3 V to 0.694 V
|   rising waveform, V_fixture 0V, R_fixture 150Ohm: 20-80 % time 267ps typ, 339ps min, 247ps max; typ from 0 V to 2.59 V
|   rising waveform, V_fixture 3.3V, R_fixture 150Ohm: 20-80 % time 252ps typ, 399ps min, 234ps max; typ from 0.694 V to 3.3 V
|   falling waveform, V_fixture 0V, R_fixture 150Ohm: 20-80 % time 309ps typ, 599ps min, 219ps max; typ from 2.59 V to 0 V
[Pulldown]
|   Voltage   I(typ)   I(min)   I(max)
-3.3V     -20.24mA   -16.35mA   -22.74mA
-2.627V   -20.51mA   -16.96mA   -22.78mA
-1.904V   -19.15mA   -16.31mA   -20.92mA
-825mV    -15.32mA   -13.09mA   -16.58mA
-528mV    -12.6mA    -10.73mA   -13.68mA
2.363V    58.81mA    50.06mA    63.75mA
2.779V    68.52mA    55.45mA    74.91mA
3.194V    76.56mA    57.64mA    85.33mA
3.472V    80.24mA    58.25mA    91.59mA
3.927V    83.16mA    58.8mA     99.52mA
4.491V    84.51mA    59.27mA    104mA
6.6V      86.52mA    60.3mA     107.5mA
[GND Clamp]
|   Voltage   I(typ)   I(min)   I(max)
-3.3V     -160mA     -119.4mA   -217mA
-1.033V   -19.39mA   -17.52mA   -22.42mA
-825mV    -10.43mA   -9.877mA   -12.11mA
-716.1mV  -6.541mA   -6.437mA   -7.501mA
-636.9mV  -4.054mA   -4.313mA   -4.508mA
-537.9mV  -1.566mA   -2.15mA    -1.56mA
-508.2mV  -1.102mA   -1.701mA   -874.9uA
-468.6mV  -579.2uA   -1.102mA   -331.5uA
-399.3mV  -111.6uA   -431.1uA   -25.79uA
-349.8mV  -18.86uA   -131.8uA   -5.146uA
-171.6mV  -88.3nA    -2.804uA   -107.4nA
6.6V      0A         0A         0A
[Pullup]
|   Voltage   I(typ)   I(min)   I(max)
-3.3V     18.22mA    13.61mA    21.27mA
-2.458V   18.42mA    14.67mA    20.52mA
-1.429V   15.6mA     13.29mA    16.94mA
-825mV    13.14mA    11.11mA    14.22mA
-409.2mV  9.448mA    7.817mA    10.39mA
2.501V    -60.79mA   -48.88mA   -67.37mA
2.858V    -68.68mA   -52.68mA   -76.8mA
3.333V    -77.15mA   -54.66mA   -88.46mA
3.887V    -82.07mA   -55.31mA   -99.54mA
4.155V    -82.98mA   -55.48mA   -103.2mA
4.729V    -83.92mA   -55.76mA   -106.9mA
6.6V      -86.67mA   -58.06mA   -109.2mA
[POWER Clamp]
|   Voltage   I(typ)   I(min)   I(max)
-3.3V     224.5mA    191.3mA    262.6mA
-1.211V   38.57mA    34.7mA     44.22mA
-1.132V   32.63mA    29.7mA     37.31mA
-1.122V   31.9mA     29.08mA    36.46mA
-953.7mV  20.54mA    19.22mA    23.62mA
-825mV    14.09mA    12.89mA    17.14mA
-765.6mV  11.78mA    10.49mA    14.49mA
-636.9mV  7.357mA    6.549mA    9.056mA
-468.6mV  2.565mA    2.754mA    2.952mA
-399.3mV  1.162mA    1.587mA    1.169mA
-290.4mV  108.4uA    386uA      43.42uA
6.6V      0A         0A         0A
[Ramp]
R_load = 150
|   typ   min   max
dV/dt_r   1.55545/2.66804e-10   1.3484/3.38592e-10   1.74402/2.46044e-10
dV/dt_f   1.56311/2.81324e-10   1.36817/3.74112e-10   1.74583/2.59491e-10
[Falling Waveform]
V_fixture = 3.3V
V_fixture_min = 2.97V
V_fixture_max = 3.63V
R_fixture = 150Ohm
C_fixture = 0F
|   Time   V(typ)   V(min)   V(max)
0s        3.3V       2.969V     3.63V
1.355ns   3.302V     2.969V     3.622V
1.59ns    3.312V     2.97V      1.915V
1.79ns    3.277V     2.971V     1.099V
2.03ns    1.832V     2.975V     849.7mV
2.3ns     957.7mV    2.98V      799.9mV
2.675ns   779.8mV    2.9V       752.4mV
3.225ns   719mV      1.152V     735.9mV
3.595ns   709.7mV    784.6mV    731.3mV
10ns      694.5mV    689mV      720mV
[Rising Waveform]
V_fixture = 0V
V_fixture_min = 0V
V_fixture_max = 0V
R_fixture = 150Ohm
C_fixture = 0F
|   Time   V(typ)   V(min)   V(max)
0s        414.8uV    957.9uV    279.3uV
1.38ns    231.3uV    629.3uV    10.69mV
1.615ns   -2.694mV   458.4uV    1.862V
1.83ns    1.683mV    493.2uV    2.553V
2.1ns     1.66V      -393.4uV   2.757V
2.335ns   2.291V     -2.229mV   2.846V
2.785ns   2.532V     46.6mV     2.894V
3.285ns   2.582V     1.817V     2.901V
3.855ns   2.588V     2.192V     2.904V
10ns      2.593V     2.248V     2.907V
[Rising Waveform]
V_fixture = 3.3V
V_fixture_min = 2.97V
V_fixture_max = 3.63V
R_fixture = 150Ohm
C_fixture = 0F
|   Time   V(typ)   V(min)   V(max)
0s        694.5mV    689mV      720mV
1.37ns    694.3mV    688.8mV    766.3mV
1.655ns   711.6mV    688.7mV    2.963V
1.83ns    995.3mV    688.7mV    3.285V
2.03ns    2.396V     688.8mV    3.479V
2.165ns   2.853V     692mV      3.533V
2.61ns    3.207V     954.1mV    3.596V
3.13ns    3.27V      2.559V     3.616V
3.605ns   3.284V     2.879V     3.623V
10ns      3.3V       2.969V     3.63V
[Falling Waveform]
|Gnd
V_fixture = 0V
V_fixture_min = 0V
V_fixture_max = 0V
R_fixture = 150Ohm
C_fixture = 0F
|   Time   V(typ)   V(min)   V(max)
0s        2.593V     2.248V     2.907V
1.21ns    2.593V     2.248V     2.854V
1.38ns    2.588V     2.248V     2.386V
1.53ns    2.474V     2.248V     1.017V
1.64ns    2.233V     2.248V     472.8mV
1.8ns     1.829V     2.248V     265.6mV
1.965ns   754.5mV    2.228V     166.2mV
2.095ns   321.3mV    2.145V     114.8mV
3.12ns    37.93mV    189.8mV    23.51mV
10ns      412.9uV    958uV      279.6uV
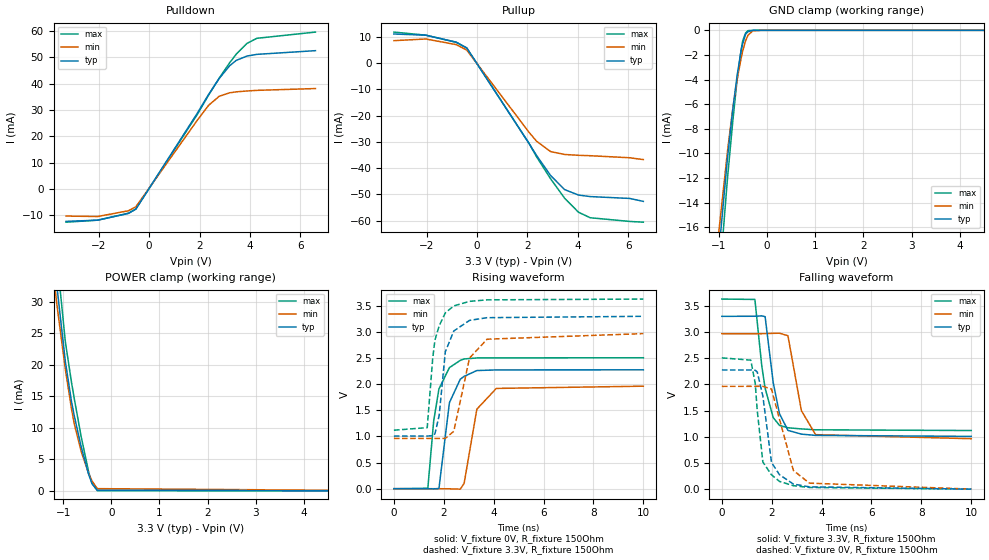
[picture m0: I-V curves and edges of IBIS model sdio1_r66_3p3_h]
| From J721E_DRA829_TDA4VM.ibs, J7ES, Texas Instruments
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|   r66_3p3_h
[Model]   sdio1_r66_3p3_h
Model_type   I/O
Polarity   Non-Inverting
Enable   Active-High
Vinl = 0
Vinh = 0.8
Vmeas = 1.65
Vref = 3.3
Cref = 2pF
Rref = 100000
|   typ   min   max
C_comp   3.072pF   2.784pF   3.276pF
[Voltage Range]   3.3   2.97   3.63
[Temperature Range]   27   150   -40
[Pullup Reference]   3.3   2.97   3.63
[Pulldown Reference]   0   0   0
[Power Clamp Reference]   3.3   2.97   3.63
[GND Clamp Reference]   0   0   0
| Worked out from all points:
|   slope of the pulldown table from 0 to 0.495 V, typ, clamps not added: 65.6 ohm
|   slope of the pullup table from 0 to 0.495 V, typ, clamps not added: 67.1 ohm
|   GND clamp passes 1 mA (typ) near -0.50 V on its own axis
|   POWER clamp passes 1 mA (typ) near -0.39 V on its own axis
|   falling waveform, V_fixture 3.3V, R_fixture 150Ohm: 20-80 % time 422ps typ, 482ps min, 425ps max; typ from 3.3 V to 1.01 V
|   rising waveform, V_fixture 0V, R_fixture 150Ohm: 20-80 % time 400ps typ, 463ps min, 402ps max; typ from 0.001 V to 2.28 V
|   rising waveform, V_fixture 3.3V, R_fixture 150Ohm: 20-80 % time 387ps typ, 572ps min, 392ps max; typ from 1.01 V to 3.3 V
|   falling waveform, V_fixture 0V, R_fixture 150Ohm: 20-80 % time 392ps typ, 646ps min, 317ps max; typ from 2.28 V to 0.001 V
[Pulldown]
|   Voltage   I(typ)   I(min)   I(max)
-3.3V     -12.31mA   -10.29mA   -12.62mA
-2.043V   -11.85mA   -10.47mA   -11.85mA
-825mV    -9.307mA   -8.287mA   -9.206mA
-528mV    -7.654mA   -6.783mA   -7.589mA
1.907V    28.69mA    26.04mA    28.23mA
2.363V    35.95mA    31.79mA    35.7mA
2.779V    41.93mA    35.18mA    42.05mA
3.194V    46.78mA    36.52mA    47.91mA
3.462V    48.86mA    36.88mA    51.25mA
3.887V    50.48mA    37.21mA    55.29mA
4.274V    51.11mA    37.44mA    57.21mA
6.6V      52.52mA    38.13mA    59.57mA
[GND Clamp]
|   Voltage   I(typ)   I(min)   I(max)
-3.3V     -160mA     -119.4mA   -217mA
-1.013V   -18.47mA   -16.75mA   -21.37mA
-825mV    -10.43mA   -9.89mA    -12.11mA
-716.1mV  -6.532mA   -6.434mA   -7.501mA
-627mV    -3.775mA   -4.073mA   -4.142mA
-537.9mV  -1.565mA   -2.22mA    -1.565mA
-508.2mV  -1.103mA   -1.688mA   -876.2uA
-448.8mV  -317.7uA   -866.7uA   -227.1uA
-399.3mV  -111.5uA   -410.6uA   -25.47uA
-300.3mV  -2.826uA   -47.28uA   -741.7nA
-132mV    -44.77nA   -1.775uA   -83.62nA
6.6V      0A         0A         0A
[Pullup]
|   Voltage   I(typ)   I(min)   I(max)
-3.3V     11.09mA    8.547mA    11.81mA
-2.033V   10.62mA    9.184mA    10.64mA
-825mV    7.986mA    7.034mA    7.893mA
-409.2mV  5.742mA    4.952mA    5.767mA
2.056V    -30.5mA    -26.26mA   -30.44mA
2.363V    -35.19mA   -29.75mA   -35.68mA
2.917V    -42.78mA   -33.67mA   -44.01mA
3.472V    -48.14mA   -34.78mA   -51.39mA
4.026V    -50.23mA   -35.1mA    -56.77mA
4.491V    -50.81mA   -35.25mA   -58.87mA
6.056V    -51.52mA   -36.03mA   -60.27mA
6.6V      -52.64mA   -36.73mA   -60.56mA
[POWER Clamp]
|   Voltage   I(typ)   I(min)   I(max)
-3.3V     224.5mA    191.3mA    262.6mA
-1.191V   37.07mA    33.44mA    42.47mA
-1.132V   32.63mA    29.7mA     37.31mA
-1.122V   31.9mA     29.08mA    36.46mA
-953.7mV  20.48mA    19.24mA    23.62mA
-825mV    14.08mA    12.93mA    17.14mA
-765.6mV  11.79mA    10.51mA    14.49mA
-627mV    7.039mA    6.292mA    8.648mA
-468.6mV  2.565mA    2.728mA    2.954mA
-399.3mV  1.162mA    1.563mA    1.166mA
-290.4mV  108.6uA    361.9uA    43.24uA
6.6V      0A         0A         0A
[Ramp]
R_load = 150
|   typ   min   max
dV/dt_r   1.36524/3.98873e-10   1.17722/4.62538e-10   1.50402/4.01319e-10
dV/dt_f   1.37491/4.21688e-10   1.20325/4.81427e-10   1.50573/4.25408e-10
[Falling Waveform]
V_fixture = 3.3V
V_fixture_min = 2.97V
V_fixture_max = 3.63V
R_fixture = 150Ohm
C_fixture = 0F
|   Time   V(typ)   V(min)   V(max)
0s        3.3V       2.969V     3.63V
1.325ns   3.302V     2.969V     3.623V
1.6ns     3.309V     2.969V     2.359V
1.735ns   3.295V     2.97V      1.929V
2.06ns    2.033V     2.976V     1.367V
2.31ns    1.443V     2.978V     1.218V
2.65ns    1.123V     2.931V     1.173V
3.19ns    1.051V     1.499V     1.151V
3.76ns    1.027V     1.041V     1.134V
10ns      1.008V     963.6mV    1.12V
[Rising Waveform]
V_fixture = 0V
V_fixture_min = 0V
V_fixture_max = 0V
R_fixture = 150Ohm
C_fixture = 0F
|   Time   V(typ)   V(min)   V(max)
0s        610.1uV    1.364mV    475.9uV
1.36ns    317.2uV    852uV      8.857mV
1.595ns   -2.069mV   655.3uV    1.3V
1.805ns   3.817mV    647.5uV    1.91V
2.225ns   1.648V     -1.559mV   2.318V
2.66ns    2.096V     -7.904mV   2.457V
2.815ns   2.151V     104.6mV    2.484V
3.325ns   2.262V     1.523V     2.503V
4.105ns   2.274V     1.92V      2.505V
10ns      2.276V     1.963V     2.507V
[Rising Waveform]
V_fixture = 3.3V
V_fixture_min = 2.97V
V_fixture_max = 3.63V
R_fixture = 150Ohm
C_fixture = 0F
|   Time   V(typ)   V(min)   V(max)
0s        1.008V     963.6mV    1.12V
1.335ns   1.008V     963.4mV    1.17V
1.555ns   1.017V     963.2mV    2.493V
1.645ns   1.052V     963.2mV    2.848V
1.815ns   1.404V     963.2mV    3.119V
2.06ns    2.62V      964.1mV    3.365V
2.4ns     3.019V     1.099V     3.499V
3.03ns    3.222V     2.5V       3.586V
3.735ns   3.274V     2.862V     3.615V
10ns      3.3V       2.969V     3.63V
[Falling Waveform]
|Gnd
V_fixture = 0V
V_fixture_min = 0V
V_fixture_max = 0V
R_fixture = 150Ohm
C_fixture = 0F
|   Time   V(typ)   V(min)   V(max)
0s        2.276V     1.963V     2.507V
1.16ns    2.276V     1.964V     2.464V
1.34ns    2.27V      1.964V     2.017V
1.42ns    2.238V     1.964V     1.5V
1.645ns   1.777V     1.964V     518.2mV
1.99ns    512.2mV    1.912V     275mV
2.31ns    277.3mV    1.341V     148.5mV
2.87ns    97.54mV    357.4mV    66.65mV
3.51ns    44.83mV    115.4mV    33.36mV
10ns      618.8uV    1.365mV    475.9uV
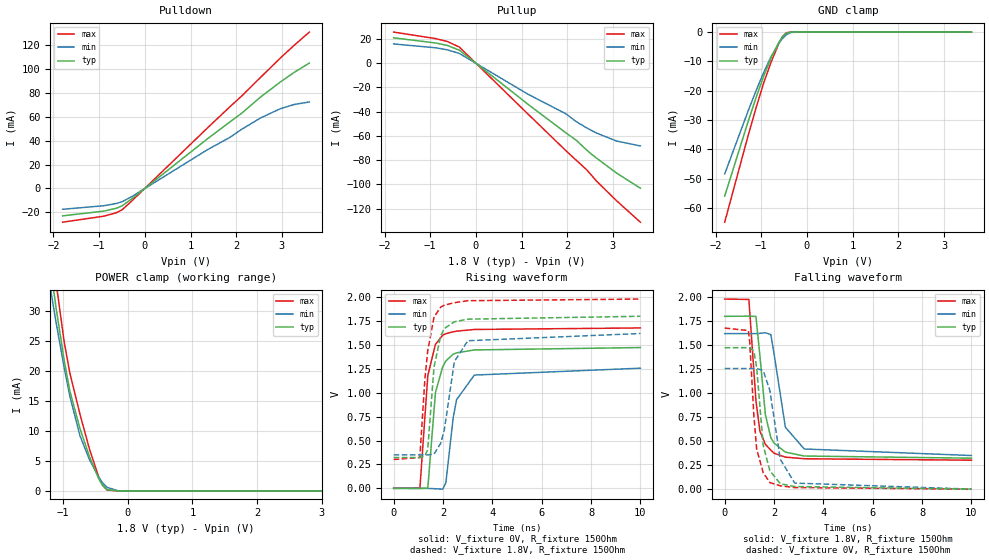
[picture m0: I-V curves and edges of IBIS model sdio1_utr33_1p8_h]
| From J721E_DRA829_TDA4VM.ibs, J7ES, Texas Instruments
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|   utr33_1p8_h
[Model]   sdio1_utr33_1p8_h
Model_type   I/O
Polarity   Non-Inverting
Enable   Active-High
Vinl = 0
Vinh = 0.8
Vmeas = 0.9
Vref = 1.8
Cref = 2pF
Rref = 100000
|   typ   min   max
C_comp   4.069pF   3.743pF   4.31pF
[Voltage Range]   1.8   1.62   1.98
[Temperature Range]   27   150   -40
[Pullup Reference]   1.8   1.62   1.98
[Pulldown Reference]   0   0   0
[Power Clamp Reference]   1.8   1.62   1.98
[GND Clamp Reference]   0   0   0
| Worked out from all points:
|   slope of the pulldown table from 0 to 0.27 V, typ, clamps not added: 32.7 ohm
|   slope of the pullup table from 0 to 0.27 V, typ, clamps not added: 33.3 ohm
|   GND clamp passes 1 mA (typ) near -0.50 V on its own axis
|   POWER clamp passes 1 mA (typ) near -0.39 V on its own axis
|   falling waveform, V_fixture 1.8V, R_fixture 150Ohm: 20-80 % time 378ps typ, 490ps min, 317ps max; typ from 1.8 V to 0.323 V
|   rising waveform, V_fixture 0V, R_fixture 150Ohm: 20-80 % time 336ps typ, 450ps min, 333ps max; typ from 0 V to 1.47 V
|   rising waveform, V_fixture 1.8V, R_fixture 150Ohm: 20-80 % time 354ps typ, 461ps min, 349ps max; typ from 0.323 V to 1.8 V
|   falling waveform, V_fixture 0V, R_fixture 150Ohm: 20-80 % time 357ps typ, 487ps min, 300ps max; typ from 1.47 V to 0 V
[Pulldown]
|   Voltage   I(typ)   I(min)   I(max)
-1.8V     -23.11mA   -17.62mA   -28.44mA
-892.8mV  -19.11mA   -14.59mA   -23.36mA
-622.8mV  -16.73mA   -12.72mA   -20.51mA
-498.6mV  -14.73mA   -11.24mA   -18.04mA
-298.8mV  -9.158mA   -7.264mA   -11.1mA
1.364V    41.41mA    32.3mA     50.49mA
1.856V    55.57mA    42.68mA    68.3mA
2.12V     63.09mA    49.57mA    77.54mA
2.531V    76.61mA    59.06mA    93.1mA
2.968V    89.36mA    66.91mA    109.5mA
3.271V    97.43mA    70.42mA    120.2mA
3.6V      105.2mA    72.5mA     131.2mA
[GND Clamp]
|   Voltage   I(typ)   I(min)   I(max)
-1.8V     -55.9mA    -48.35mA   -64.79mA
-1.287V   -30.48mA   -26.87mA   -35.27mA
-1.109V   -22.12mA   -19.8mA    -25.59mA
-946.8mV  -15.01mA   -13.77mA   -17.35mA
-790.2mV  -8.997mA   -8.533mA   -10.48mA
-622.8mV  -3.762mA   -4.011mA   -4.148mA
-541.8mV  -1.721mA   -2.298mA   -1.693mA
-450mV    -362.9uA   -857.5uA   -221.3uA
-347.4mV  -20.24uA   -138.5uA   -4.051uA
-234mV    -328.9nA   -10.21uA   -105.1nA
3.6V      0A         0A         0A
[Pullup]
|   Voltage   I(typ)   I(min)   I(max)
-1.8V     20.73mA    15.7mA     25.46mA
-887.4mV  16.51mA    12.54mA    20.13mA
-628.2mV  14.5mA     10.87mA    17.75mA
-363.6mV  10.6mA     7.89mA     13.16mA
1.138V    -33.96mA   -25.7mA    -42.01mA
1.969V    -57.56mA   -41.85mA   -72.23mA
2.201V    -63.78mA   -48.44mA   -80.3mA
2.417V    -71.5mA    -53.33mA   -87.73mA
2.542V    -75.51mA   -55.84mA   -93.06mA
2.639V    -78.39mA   -57.69mA   -97.29mA
3.076V    -90.65mA   -64.32mA   -113.4mA
3.6V      -103.2mA   -68.36mA   -131.2mA
[POWER Clamp]
|   Voltage   I(typ)   I(min)   I(max)
-1.8V     86.44mA    75.43mA    99.9mA
-1.287V   44.12mA    39.56mA    50.59mA
-1.109V   30.39mA    27.98mA    34.62mA
-984.6mV  21.72mA    20.51mA    24.79mA
-898.2mV  16.68mA    15.82mA    19.69mA
-741.6mV  10.42mA    9.224mA    12.8mA
-595.8mV  5.776mA    5.267mA    7.057mA
-450mV    2.018mA    2.285mA    2.308mA
-390.6mV  933uA      1.359mA    950uA
-320.4mV  226.3uA    591.6uA    147.1uA
-147.6mV  917.3nA    14.06uA    198nA
3.6V      0A         0A         0A
[Ramp]
R_load = 150
|   typ   min   max
dV/dt_r   0.883531/3.34876e-10   0.753546/4.50218e-10   1.0065/3.32826e-10
dV/dt_f   0.886304/3.77292e-10   0.761434/4.88087e-10   1.00685/3.16778e-10
[Falling Waveform]
V_fixture = 1.8V
V_fixture_min = 1.62V
V_fixture_max = 1.98V
R_fixture = 150Ohm
C_fixture = 0F
|   Time   V(typ)   V(min)   V(max)
0s        1.8V       1.62V      1.98V
980ps     1.802V     1.62V      1.976V
1.265ns   1.799V     1.62V      926.4mV
1.425ns   1.397V     1.623V     606mV
1.65ns    775.2mV    1.629V     466.7mV
1.87ns    535.7mV    1.611V     406.2mV
2.005ns   479mV      1.403V     373.9mV
2.46ns    386mV      644.4mV    333.9mV
3.225ns   345.3mV    418.7mV    316.8mV
10ns      322.7mV    350.5mV    301.8mV
[Rising Waveform]
V_fixture = 0V
V_fixture_min = 0V
V_fixture_max = 0V
R_fixture = 150Ohm
C_fixture = 0F
|   Time   V(typ)   V(min)   V(max)
0s        229.9uV    631.9uV    133.6uV
1.065ns   -1.338mV   446uV      4.301mV
1.385ns   3.598mV    -546.1uV   1.182V
1.695ns   1.004V     -4.041mV   1.506V
1.985ns   1.269V     -8.262mV   1.602V
2.115ns   1.333V     57.56mV    1.618V
2.415ns   1.404V     741.3mV    1.638V
2.55ns    1.417V     927.3mV    1.644V
3.27ns    1.448V     1.185V     1.662V
10ns      1.473V     1.257V     1.678V
[Rising Waveform]
V_fixture = 1.8V
V_fixture_min = 1.62V
V_fixture_max = 1.98V
R_fixture = 150Ohm
C_fixture = 0F
|   Time   V(typ)   V(min)   V(max)
0s        322.7mV    350.5mV    301.8mV
1.06ns    322.1mV    350.3mV    323.3mV
1.265ns   338.5mV    350.2mV    1.138V
1.38ns    405.2mV    349.8mV    1.437V
1.635ns   1.268V     359mV      1.791V
1.905ns   1.594V     469.8mV    1.896V
2.055ns   1.672V     612.2mV    1.916V
2.46ns    1.742V     1.325V     1.942V
3.005ns   1.77V      1.544V     1.963V
10ns      1.8V       1.62V      1.98V
[Falling Waveform]
|Gnd
V_fixture = 0V
V_fixture_min = 0V
V_fixture_max = 0V
R_fixture = 150Ohm
C_fixture = 0F
|   Time   V(typ)   V(min)   V(max)
0s        1.473V     1.257V     1.678V
960ps     1.474V     1.257V     1.652V
1.015ns   1.473V     1.257V     1.531V
1.18ns    1.439V     1.257V     776.1mV
1.295ns   1.269V     1.257V     419.7mV
1.56ns    458.3mV    1.236V     172.3mV
1.83ns    192.2mV    1.028V     68.75mV
2.255ns   56.19mV    309.8mV    35.29mV
2.84ns    27.51mV    63.29mV    16.96mV
10ns      229.9uV    633.8uV    133.6uV
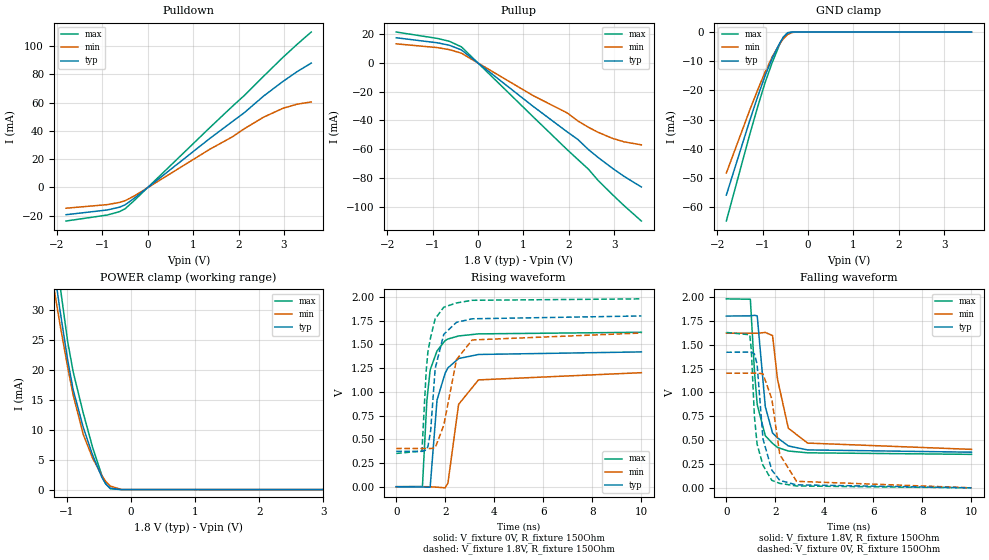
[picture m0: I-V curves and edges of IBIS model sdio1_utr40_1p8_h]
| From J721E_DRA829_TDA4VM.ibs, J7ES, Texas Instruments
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|   utr40_1p8_h
[Model]   sdio1_utr40_1p8_h
Model_type   I/O
Polarity   Non-Inverting
Enable   Active-High
Vinl = 0
Vinh = 0.8
Vmeas = 0.9
Vref = 1.8
Cref = 2pF
Rref = 100000
|   typ   min   max
C_comp   4.211pF   3.873pF   4.46pF
[Voltage Range]   1.8   1.62   1.98
[Temperature Range]   27   150   -40
[Pullup Reference]   1.8   1.62   1.98
[Pulldown Reference]   0   0   0
[Power Clamp Reference]   1.8   1.62   1.98
[GND Clamp Reference]   0   0   0
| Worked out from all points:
|   slope of the pulldown table from 0 to 0.27 V, typ, clamps not added: 39.2 ohm
|   slope of the pullup table from 0 to 0.27 V, typ, clamps not added: 39.9 ohm
|   GND clamp passes 1 mA (typ) near -0.50 V on its own axis
|   POWER clamp passes 1 mA (typ) near -0.39 V on its own axis
|   falling waveform, V_fixture 1.8V, R_fixture 150Ohm: 20-80 % time 380ps typ, 495ps min, 317ps max; typ from 1.8 V to 0.374 V
|   rising waveform, V_fixture 0V, R_fixture 150Ohm: 20-80 % time 394ps typ, 514ps min, 333ps max; typ from 0 V to 1.42 V
|   rising waveform, V_fixture 1.8V, R_fixture 150Ohm: 20-80 % time 390ps typ, 575ps min, 334ps max; typ from 0.374 V to 1.8 V
|   falling waveform, V_fixture 0V, R_fixture 150Ohm: 20-80 % time 395ps typ, 500ps min, 332ps max; typ from 1.42 V to 0 V
[Pulldown]
|   Voltage   I(typ)   I(min)   I(max)
-1.8V     -19.28mA   -14.69mA   -23.74mA
-892.8mV  -15.94mA   -12.16mA   -19.5mA
-622.8mV  -13.96mA   -10.6mA    -17.12mA
-498.6mV  -12.28mA   -9.371mA   -15.06mA
-298.8mV  -7.64mA    -6.056mA   -9.266mA
1.364V    34.57mA    26.94mA    42.19mA
1.861V    46.5mA     35.7mA     57.24mA
2.12V     52.65mA    41.34mA    64.79mA
2.552V    64.58mA    49.66mA    78.59mA
2.974V    74.82mA    55.88mA    91.83mA
3.292V    81.89mA    58.85mA    101.2mA
3.6V      87.86mA    60.4mA     109.8mA
[GND Clamp]
|   Voltage   I(typ)   I(min)   I(max)
-1.8V     -55.9mA    -48.35mA   -64.79mA
-1.287V   -30.48mA   -26.87mA   -35.27mA
-1.109V   -22.12mA   -19.8mA    -25.59mA
-946.8mV  -15.01mA   -13.77mA   -17.35mA
-790.2mV  -8.997mA   -8.533mA   -10.48mA
-622.8mV  -3.762mA   -4.011mA   -4.148mA
-541.8mV  -1.721mA   -2.298mA   -1.693mA
-450mV    -363uA     -857.5uA   -221.5uA
-347.4mV  -20.25uA   -138.5uA   -4.049uA
-234mV    -328.7nA   -10.21uA   -105.1nA
3.6V      0A         0A         0A
[Pullup]
|   Voltage   I(typ)   I(min)   I(max)
-1.8V     17.29mA    13.07mA    21.26mA
-887.4mV  13.77mA    10.45mA    16.8mA
-628.2mV  12.1mA     9.061mA    14.82mA
-363.6mV  8.839mA    6.578mA    10.98mA
1.213V    -30.22mA   -22.79mA   -37.43mA
1.969V    -48.05mA   -34.9mA    -60.41mA
2.201V    -53.23mA   -40.42mA   -67.14mA
2.434V    -60.24mA   -44.79mA   -73.85mA
2.639V    -65.53mA   -48.15mA   -81.41mA
2.963V    -73.24mA   -52.47mA   -91.5mA
3.222V    -78.9mA    -54.91mA   -99.22mA
3.6V      -86.2mA    -56.98mA   -109.8mA
[POWER Clamp]
|   Voltage   I(typ)   I(min)   I(max)
-1.8V     86.44mA    75.43mA    99.9mA
-1.287V   44.12mA    39.56mA    50.59mA
-1.109V   30.39mA    27.98mA    34.62mA
-984.6mV  21.72mA    20.51mA    24.79mA
-898.2mV  16.68mA    15.82mA    19.69mA
-741.6mV  10.42mA    9.224mA    12.8mA
-595.8mV  5.776mA    5.267mA    7.057mA
-450mV    2.018mA    2.285mA    2.308mA
-390.6mV  933uA      1.359mA    950.1uA
-320.4mV  226.3uA    591.6uA    147uA
-147.6mV  917.5nA    14.06uA    197.9nA
3.6V      0A         0A         0A
[Ramp]
R_load = 150
|   typ   min   max
dV/dt_r   0.852598/3.91919e-10   0.720862/5.14112e-10   0.976916/3.32542e-10
dV/dt_f   0.855747/3.79521e-10   0.729752/4.9291e-10   0.977324/3.1533e-10
[Falling Waveform]
V_fixture = 1.8V
V_fixture_min = 1.62V
V_fixture_max = 1.98V
R_fixture = 150Ohm
C_fixture = 0F
|   Time   V(typ)   V(min)   V(max)
0s        1.8V       1.62V      1.98V
980ps     1.802V     1.62V      1.976V
1.15ns    1.808V     1.62V      1.21V
1.26ns    1.802V     1.62V      871.7mV
1.59ns    849.9mV    1.628V     545.6mV
1.885ns   574.8mV    1.596V     466.1mV
2.09ns    523.3mV    1.135V     422.9mV
2.53ns    439mV      624.5mV    386.1mV
3.315ns   397.7mV    469.1mV    367.1mV
10ns      373.6mV    403.3mV    351mV
[Rising Waveform]
V_fixture = 0V
V_fixture_min = 0V
V_fixture_max = 0V
R_fixture = 150Ohm
C_fixture = 0F
|   Time   V(typ)   V(min)   V(max)
0s        269.3uV    727.1uV    156.7uV
1.07ns    -2.049mV   510.6uV    2.702mV
1.25ns    -5.339mV   512.5uV    904.7mV
1.385ns   -4.684mV   -681uV     1.231V
1.665ns   912.9mV    -4.771mV   1.432V
1.995ns   1.196V     -11.63mV   1.54V
2.11ns    1.253V     37.91mV    1.557V
2.545ns   1.351V     868.2mV    1.589V
3.355ns   1.394V     1.126V     1.611V
10ns      1.421V     1.202V     1.628V
[Rising Waveform]
V_fixture = 1.8V
V_fixture_min = 1.62V
V_fixture_max = 1.98V
R_fixture = 150Ohm
C_fixture = 0F
|   Time   V(typ)   V(min)   V(max)
0s        373.6mV    403.3mV    351mV
1.05ns    372.7mV    403mV      375.7mV
1.225ns   386.5mV    403mV      1.229V
1.295ns   425.3mV    402.7mV    1.426V
1.405ns   592mV      402.6mV    1.575V
1.59ns    1.246V     410.3mV    1.771V
1.94ns    1.607V     647.7mV    1.892V
2.46ns    1.733V     1.34V      1.937V
3.1ns     1.77V      1.547V     1.965V
10ns      1.8V       1.62V      1.98V
[Falling Waveform]
|Gnd
V_fixture = 0V
V_fixture_min = 0V
V_fixture_max = 0V
R_fixture = 150Ohm
C_fixture = 0F
|   Time   V(typ)   V(min)   V(max)
0s        1.421V     1.202V     1.628V
955ps     1.422V     1.202V     1.604V
1.02ns    1.422V     1.202V     1.443V
1.145ns   1.403V     1.202V     750.2mV
1.255ns   1.296V     1.203V     458.4mV
1.495ns   513mV      1.194V     236.5mV
1.855ns   186.1mV    932.7mV    78.69mV
2.18ns    77.58mV    349mV      46.9mV
2.865ns   31.64mV    68.41mV    19.87mV
10ns      269.3uV    728.8uV    156.3uV
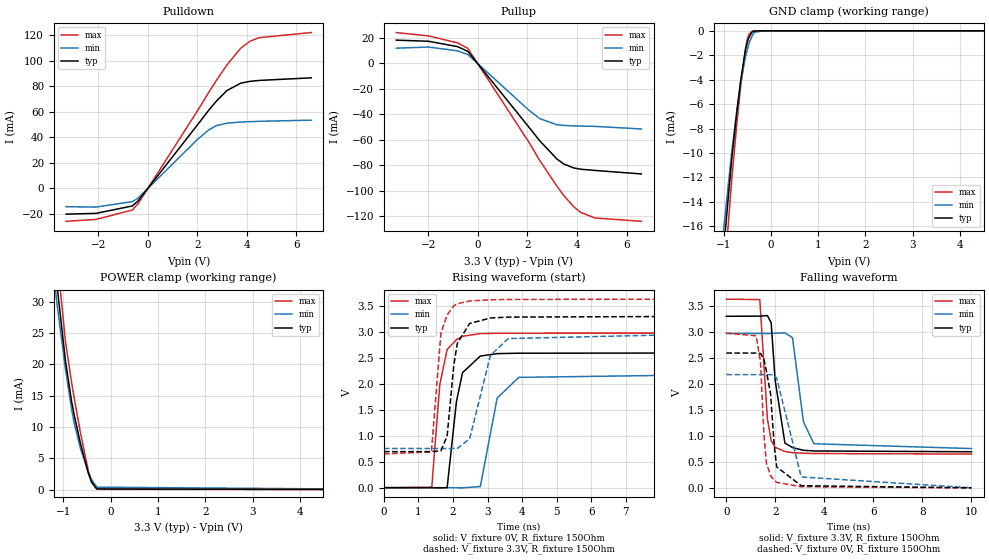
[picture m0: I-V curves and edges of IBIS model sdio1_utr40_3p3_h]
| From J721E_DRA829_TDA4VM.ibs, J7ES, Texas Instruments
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|   utr40_3p3_h
[Model]   sdio1_utr40_3p3_h
Model_type   I/O
Polarity   Non-Inverting
Enable   Active-High
Vinl = 0
Vinh = 0.8
Vmeas = 1.65
Vref = 3.3
Cref = 2pF
Rref = 100000
|   typ   min   max
C_comp   2.766pF   2.579pF   2.89pF
[Voltage Range]   3.3   2.97   3.63
[Temperature Range]   27   150   -40
[Pullup Reference]   3.3   2.97   3.63
[Pulldown Reference]   0   0   0
[Power Clamp Reference]   3.3   2.97   3.63
[GND Clamp Reference]   0   0   0
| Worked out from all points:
|   slope of the pulldown table from 0 to 0.495 V, typ, clamps not added: 39.9 ohm
|   slope of the pullup table from 0 to 0.495 V, typ, clamps not added: 40.8 ohm
|   GND clamp passes 1 mA (typ) near -0.50 V on its own axis
|   POWER clamp passes 1 mA (typ) near -0.39 V on its own axis
|   falling waveform, V_fixture 3.3V, R_fixture 150Ohm: 20-80 % time 284ps typ, 377ps min, 233ps max; typ from 3.3 V to 0.694 V
|   rising waveform, V_fixture 0V, R_fixture 150Ohm: 20-80 % time 267ps typ, 364ps min, 222ps max; typ from 0 V to 2.59 V
|   rising waveform, V_fixture 3.3V, R_fixture 150Ohm: 20-80 % time 251ps typ, 467ps min, 207ps max; typ from 0.694 V to 3.3 V
|   falling waveform, V_fixture 0V, R_fixture 150Ohm: 20-80 % time 309ps typ, 577ps min, 205ps max; typ from 2.59 V to 0 V
[Pulldown]
|   Voltage   I(typ)   I(min)   I(max)
-3.3V     -20.24mA   -14.38mA   -25.83mA
-2.092V   -19.62mA   -14.7mA    -24.36mA
-627mV    -13.81mA   -10.42mA   -16.99mA
-399.3mV  -10.02mA   -7.758mA   -12.25mA
2.006V    49.72mA    38.28mA    60.76mA
2.472V    61.46mA    45.94mA    75.55mA
2.779V    68.52mA    49.14mA    84.8mA
3.194V    76.56mA    51.05mA    96.6mA
3.749V    82.34mA    51.91mA    109.7mA
4.125V    83.78mA    52.24mA    115.2mA
4.491V    84.51mA    52.49mA    118mA
6.6V      86.52mA    53.39mA    122mA
[GND Clamp]
|   Voltage   I(typ)   I(min)   I(max)
-3.3V     -160mA     -119.4mA   -217mA
-1.033V   -19.39mA   -17.52mA   -22.42mA
-825mV    -10.43mA   -9.877mA   -12.11mA
-716.1mV  -6.541mA   -6.437mA   -7.501mA
-636.9mV  -4.054mA   -4.313mA   -4.508mA
-537.9mV  -1.566mA   -2.15mA    -1.558mA
-508.2mV  -1.102mA   -1.701mA   -874.3uA
-468.6mV  -579.2uA   -1.102mA   -330.6uA
-399.3mV  -111.6uA   -431.1uA   -25.9uA
-349.8mV  -18.86uA   -131.8uA   -5.149uA
-171.6mV  -88.3nA    -2.803uA   -107.4nA
6.6V      0A         0A         0A
[Pullup]
|   Voltage   I(typ)   I(min)   I(max)
-3.3V     18.22mA    11.94mA    24.17mA
-1.993V   17.36mA    12.81mA    21.56mA
-825mV    13.14mA    9.846mA    16.12mA
-409.2mV  9.448mA    6.928mA    11.78mA
2.066V    -50.18mA   -36.82mA   -62.04mA
2.501V    -60.79mA   -43.34mA   -76.25mA
3.194V    -75.02mA   -48.12mA   -96.43mA
3.472V    -78.92mA   -48.62mA   -103.7mA
3.868V    -81.98mA   -48.98mA   -112.4mA
4.155V    -82.98mA   -49.15mA   -116.9mA
4.729V    -83.92mA   -49.39mA   -121.2mA
6.6V      -86.67mA   -51.42mA   -123.8mA
[POWER Clamp]
|   Voltage   I(typ)   I(min)   I(max)
-3.3V     224.5mA    191.3mA    262.6mA
-1.211V   38.57mA    34.7mA     44.22mA
-1.132V   32.63mA    29.7mA     37.31mA
-1.122V   31.9mA     29.08mA    36.46mA
-953.7mV  20.54mA    19.22mA    23.62mA
-825mV    14.09mA    12.89mA    17.14mA
-765.6mV  11.78mA    10.49mA    14.49mA
-636.9mV  7.357mA    6.549mA    9.056mA
-468.6mV  2.565mA    2.754mA    2.952mA
-399.3mV  1.162mA    1.587mA    1.169mA
-290.4mV  108.4uA    386.1uA    43.48uA
6.6V      0A         0A         0A
[Ramp]
R_load = 150
|   typ   min   max
dV/dt_r   1.55545/2.66804e-10   1.3067/3.6362e-10   1.78611/2.21306e-10
dV/dt_f   1.56311/2.81324e-10   1.32816/3.75938e-10   1.78778/2.32368e-10
[Falling Waveform]
V_fixture = 3.3V
V_fixture_min = 2.97V
V_fixture_max = 3.63V
R_fixture = 150Ohm
C_fixture = 0F
|   Time   V(typ)   V(min)   V(max)
0s        3.3V       2.969V     3.63V
1.365ns   3.303V     2.969V     3.621V
1.675ns   3.314V     2.969V     1.33V
1.83ns    3.173V     2.971V     909.9mV
1.99ns    2.074V     2.974V     779.7mV
2.39ns    860.7mV    2.981V     699.9mV
2.7ns     775.3mV    2.886V     677.3mV
3.145ns   722.5mV    1.272V     666.3mV
3.57ns    710.1mV    848.3mV    660.7mV
10ns      694.5mV    755.7mV    650.1mV
[Rising Waveform]
V_fixture = 0V
V_fixture_min = 0V
V_fixture_max = 0V
R_fixture = 150Ohm
C_fixture = 0F
|   Time   V(typ)   V(min)   V(max)
0s        414.8uV    1.03mV     246.7uV
1.385ns   209uV      675.2uV    10.15mV
1.615ns   -2.694mV   494.9uV    1.974V
1.83ns    1.683mV    531.2uV    2.663V
2.1ns     1.66V      -459.3uV   2.849V
2.275ns   2.214V     -2.249mV   2.915V
2.79ns    2.534V     21.76mV    2.966V
3.28ns    2.581V     1.726V     2.972V
3.905ns   2.589V     2.124V     2.974V
10ns      2.593V     2.179V     2.977V
[Rising Waveform]
V_fixture = 3.3V
V_fixture_min = 2.97V
V_fixture_max = 3.63V
R_fixture = 150Ohm
C_fixture = 0F
|   Time   V(typ)   V(min)   V(max)
0s        694.5mV    755.7mV    650.1mV
1.375ns   694.3mV    755.5mV    689.8mV
1.65ns    710.2mV    755.4mV    2.981V
1.83ns    995.3mV    755.4mV    3.325V
2.025ns   2.367V     755.4mV    3.502V
2.125ns   2.778V     757mV      3.54V
2.48ns    3.161V     939.7mV    3.595V
3.085ns   3.267V     2.549V     3.617V
3.6ns     3.284V     2.871V     3.624V
10ns      3.3V       2.969V     3.63V
[Falling Waveform]
|Gnd
V_fixture = 0V
V_fixture_min = 0V
V_fixture_max = 0V
R_fixture = 150Ohm
C_fixture = 0F
|   Time   V(typ)   V(min)   V(max)
0s        2.593V     2.179V     2.977V
1.22ns    2.593V     2.179V     2.924V
1.395ns   2.585V     2.179V     2.406V
1.535ns   2.465V     2.179V     1.015V
1.635ns   2.245V     2.179V     474.8mV
1.805ns   1.808V     2.179V     234.4mV
1.955ns   808.7mV    2.162V     144.5mV
2.055ns   403.2mV    2.11V      105.5mV
3.055ns   41.17mV    209.8mV    21.64mV
10ns      412.9uV    1.03mV     246.6uV
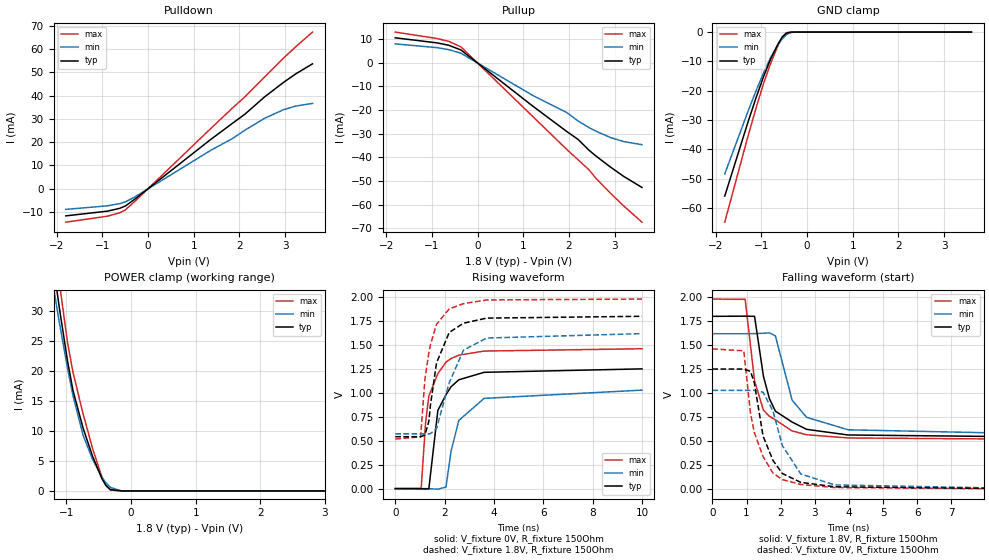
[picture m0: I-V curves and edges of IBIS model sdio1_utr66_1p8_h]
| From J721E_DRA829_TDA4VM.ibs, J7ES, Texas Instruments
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|   utr66_1p8_h
[Model]   sdio1_utr66_1p8_h
Model_type   I/O
Polarity   Non-Inverting
Enable   Active-High
Vinl = 0
Vinh = 0.8
Vmeas = 0.9
Vref = 1.8
Cref = 2pF
Rref = 100000
|   typ   min   max
C_comp   4.536pF   4.161pF   4.805pF
[Voltage Range]   1.8   1.62   1.98
[Temperature Range]   27   150   -40
[Pullup Reference]   1.8   1.62   1.98
[Pulldown Reference]   0   0   0
[Power Clamp Reference]   1.8   1.62   1.98
[GND Clamp Reference]   0   0   0
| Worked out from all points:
|   slope of the pulldown table from 0 to 0.27 V, typ, clamps not added: 64.5 ohm
|   slope of the pullup table from 0 to 0.27 V, typ, clamps not added: 65.6 ohm
|   GND clamp passes 1 mA (typ) near -0.50 V on its own axis
|   POWER clamp passes 1 mA (typ) near -0.39 V on its own axis
|   falling waveform, V_fixture 1.8V, R_fixture 150Ohm: 20-80 % time 535ps typ, 676ps min, 464ps max; typ from 1.8 V to 0.542 V
|   rising waveform, V_fixture 0V, R_fixture 150Ohm: 20-80 % time 634ps typ, 794ps min, 536ps max; typ from 0 V to 1.25 V
|   rising waveform, V_fixture 1.8V, R_fixture 150Ohm: 20-80 % time 576ps typ, 782ps min, 513ps max; typ from 0.542 V to 1.8 V
|   falling waveform, V_fixture 0V, R_fixture 150Ohm: 20-80 % time 581ps typ, 690ps min, 529ps max; typ from 1.25 V to 0 V
[Pulldown]
|   Voltage   I(typ)   I(min)   I(max)
-1.8V     -11.71mA   -8.923mA   -14.43mA
-892.8mV  -9.684mA   -7.39mA    -11.85mA
-622.8mV  -8.481mA   -6.44mA    -10.41mA
-498.6mV  -7.464mA   -5.693mA   -9.153mA
-298.8mV  -4.643mA   -3.679mA   -5.633mA
1.364V    21.07mA    16.4mA     25.73mA
1.85V     28.16mA    21.59mA    34.75mA
2.12V     32.05mA    25.17mA    39.51mA
2.547V    39.43mA    30.24mA    47.98mA
2.968V    45.77mA    34.01mA    56.25mA
3.238V    49.46mA    35.56mA    61.16mA
3.6V      53.72mA    36.68mA    67.37mA
[GND Clamp]
|   Voltage   I(typ)   I(min)   I(max)
-1.8V     -55.9mA    -48.35mA   -64.79mA
-1.287V   -30.48mA   -26.87mA   -35.27mA
-1.109V   -22.12mA   -19.8mA    -25.59mA
-946.8mV  -15.01mA   -13.77mA   -17.35mA
-790.2mV  -8.997mA   -8.533mA   -10.48mA
-622.8mV  -3.762mA   -4.011mA   -4.148mA
-541.8mV  -1.721mA   -2.298mA   -1.693mA
-450mV    -363.1uA   -857.5uA   -221.9uA
-347.4mV  -20.25uA   -138.5uA   -4.044uA
-234mV    -328.4nA   -10.21uA   -105.1nA
3.6V      0A         0A         0A
[Pullup]
|   Voltage   I(typ)   I(min)   I(max)
-1.8V     10.51mA    7.944mA    12.93mA
-887.4mV  8.37mA     6.349mA    10.21mA
-628.2mV  7.35mA     5.504mA    9.006mA
-363.6mV  5.371mA    3.996mA    6.677mA
1.213V    -18.42mA   -13.9mA    -22.82mA
1.958V    -29.16mA   -21.14mA   -36.76mA
2.201V    -32.44mA   -24.66mA   -41.04mA
2.444V    -37.07mA   -27.47mA   -45.35mA
2.585V    -39.33mA   -28.89mA   -48.74mA
2.914V    -44.2mA    -31.67mA   -55.28mA
3.206V    -48.14mA   -33.38mA   -60.65mA
3.6V      -52.75mA   -34.66mA   -67.43mA
[POWER Clamp]
|   Voltage   I(typ)   I(min)   I(max)
-1.8V     86.44mA    75.43mA    99.9mA
-1.287V   44.12mA    39.56mA    50.59mA
-1.109V   30.39mA    27.98mA    34.62mA
-984.6mV  21.72mA    20.51mA    24.79mA
-898.2mV  16.68mA    15.82mA    19.69mA
-741.6mV  10.42mA    9.224mA    12.8mA
-595.8mV  5.776mA    5.267mA    7.057mA
-450mV    2.018mA    2.285mA    2.309mA
-390.6mV  933.2uA    1.359mA    950.1uA
-320.4mV  226.2uA    591.6uA    146.6uA
-147.6mV  918nA      14.06uA    197.7nA
3.6V      0A         0A         0A
[Ramp]
R_load = 150
|   typ   min   max
dV/dt_r   0.750105/6.3357e-10   0.616526/7.95296e-10   0.876246/5.36217e-10
dV/dt_f   0.754398/5.35096e-10   0.627992/6.64894e-10   0.876894/4.62545e-10
[Falling Waveform]
V_fixture = 1.8V
V_fixture_min = 1.62V
V_fixture_max = 1.98V
R_fixture = 150Ohm
C_fixture = 0F
|   Time   V(typ)   V(min)   V(max)
0s        1.8V       1.619V     1.98V
960ps     1.802V     1.619V     1.977V
1.235ns   1.8V       1.62V      1.128V
1.495ns   1.176V     1.624V     822.8mV
1.67ns    943.1mV    1.628V     759.7mV
1.845ns   812.6mV    1.597V     722.5mV
2.335ns   699mV      927.4mV    606.4mV
2.76ns    623.2mV    748.4mV    567.3mV
3.975ns   564.5mV    618.5mV    533.6mV
10ns      542.5mV    572.7mV    518.4mV
[Rising Waveform]
V_fixture = 0V
V_fixture_min = 0V
V_fixture_max = 0V
R_fixture = 150Ohm
C_fixture = 0F
|   Time   V(typ)   V(min)   V(max)
0s        411.4uV    1.032mV    249.5uV
1.05ns    -1.557mV   724.5uV    2.67mV
1.225ns   -3.521mV   758.3uV    680.5mV
1.36ns    -1.362mV   -508.2uV   966.9mV
1.725ns   816.7mV    -5.37mV    1.201V
2.055ns   981.7mV    16.62mV    1.321V
2.26ns    1.064V     391mV      1.359V
2.575ns   1.137V     712.7mV    1.394V
3.6ns     1.215V     942.7mV    1.437V
10ns      1.251V     1.029V     1.461V
[Rising Waveform]
V_fixture = 1.8V
V_fixture_min = 1.62V
V_fixture_max = 1.98V
R_fixture = 150Ohm
C_fixture = 0F
|   Time   V(typ)   V(min)   V(max)
0s        542.5mV    572.7mV    518.4mV
1.025ns   542.2mV    572.3mV    541mV
1.2ns     559.3mV    572.3mV    1.141V
1.36ns    702.9mV    572.2mV    1.42V
1.425ns   873.1mV    573.6mV    1.503V
1.67ns    1.312V     627.7mV    1.716V
2.185ns   1.631V     1.105V     1.877V
2.765ns   1.728V     1.447V     1.932V
3.705ns   1.781V     1.573V     1.971V
10ns      1.8V       1.619V     1.98V
[Falling Waveform]
|Gnd
V_fixture = 0V
V_fixture_min = 0V
V_fixture_max = 0V
R_fixture = 150Ohm
C_fixture = 0F
|   Time   V(typ)   V(min)   V(max)
0s        1.251V     1.029V     1.461V
920ps     1.251V     1.029V     1.441V
1.115ns   1.227V     1.029V     794.6mV
1.225ns   1.113V     1.029V     594.2mV
1.485ns   552.5mV    1.01V      339.6mV
1.775ns   299.4mV    813.6mV    167.8mV
2.05ns    163mV      453mV      100.2mV
2.59ns    70.93mV    158.4mV    48.95mV
3.58ns    25.35mV    44.8mV     16.92mV
10ns      411.4uV    1.026mV    249.6uV
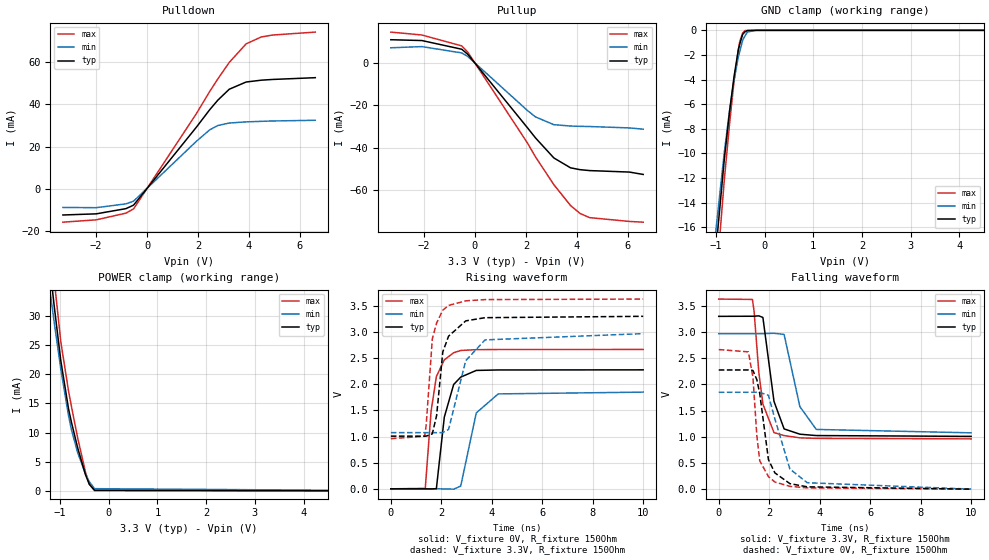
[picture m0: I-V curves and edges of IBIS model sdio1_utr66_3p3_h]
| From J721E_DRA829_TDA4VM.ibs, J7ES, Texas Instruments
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|   utr66_3p3_h
[Model]   sdio1_utr66_3p3_h
Model_type   I/O
Polarity   Non-Inverting
Enable   Active-High
Vinl = 0
Vinh = 0.8
Vmeas = 1.65
Vref = 3.3
Cref = 2pF
Rref = 100000
|   typ   min   max
C_comp   3.072pF   2.849pF   3.217pF
[Voltage Range]   3.3   2.97   3.63
[Temperature Range]   27   150   -40
[Pullup Reference]   3.3   2.97   3.63
[Pulldown Reference]   0   0   0
[Power Clamp Reference]   3.3   2.97   3.63
[GND Clamp Reference]   0   0   0
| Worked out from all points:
|   slope of the pulldown table from 0 to 0.495 V, typ, clamps not added: 65.6 ohm
|   slope of the pullup table from 0 to 0.495 V, typ, clamps not added: 67.1 ohm
|   GND clamp passes 1 mA (typ) near -0.50 V on its own axis
|   POWER clamp passes 1 mA (typ) near -0.39 V on its own axis
|   falling waveform, V_fixture 3.3V, R_fixture 150Ohm: 20-80 % time 422ps typ, 550ps min, 355ps max; typ from 3.3 V to 1.01 V
|   rising waveform, V_fixture 0V, R_fixture 150Ohm: 20-80 % time 400ps typ, 528ps min, 336ps max; typ from 0.001 V to 2.28 V
|   rising waveform, V_fixture 3.3V, R_fixture 150Ohm: 20-80 % time 385ps typ, 644ps min, 335ps max; typ from 1.01 V to 3.3 V
|   falling waveform, V_fixture 0V, R_fixture 150Ohm: 20-80 % time 392ps typ, 680ps min, 272ps max; typ from 2.28 V to 0.001 V
[Pulldown]
|   Voltage   I(typ)   I(min)   I(max)
-3.3V     -12.31mA   -8.754mA   -15.71mA
-1.993V   -11.77mA   -8.858mA   -14.6mA
-825mV    -9.307mA   -7.047mA   -11.43mA
-528mV    -7.654mA   -5.78mA    -9.415mA
1.937V    29.17mA    22.5mA     35.57mA
2.462V    37.45mA    27.93mA    46.08mA
2.779V    41.93mA    29.94mA    51.98mA
3.224V    47.06mA    31.11mA    59.71mA
3.887V    50.48mA    31.65mA    68.49mA
4.481V    51.34mA    31.91mA    71.75mA
4.917V    51.68mA    32.08mA    72.65mA
6.6V      52.52mA    32.41mA    74.05mA
[GND Clamp]
|   Voltage   I(typ)   I(min)   I(max)
-3.3V     -160mA     -119.4mA   -217mA
-1.013V   -18.47mA   -16.75mA   -21.35mA
-825mV    -10.43mA   -9.877mA   -12.11mA
-716.1mV  -6.532mA   -6.437mA   -7.501mA
-627mV    -3.775mA   -4.073mA   -4.152mA
-537.9mV  -1.565mA   -2.148mA   -1.587mA
-508.2mV  -1.103mA   -1.7mA     -880.9uA
-448.8mV  -317.7uA   -803.5uA   -217.3uA
-399.3mV  -111.5uA   -430.8uA   -25.78uA
-349.8mV  -18.89uA   -131.4uA   -5.096uA
-171.6mV  -88.28nA   -2.8uA     -107.4nA
6.6V      0A         0A         0A
[Pullup]
|   Voltage   I(typ)   I(min)   I(max)
-3.3V     11.09mA    7.273mA    14.7mA
-2.082V   10.7mA     7.834mA    13.32mA
-518.1mV  6.593mA    4.847mA    8.166mA
-280.5mV  4.197mA    3.155mA    5.207mA
2.066V    -30.66mA   -22.46mA   -37.89mA
2.373V    -35.33mA   -25.41mA   -44.3mA
3.095V    -44.84mA   -29.11mA   -57.48mA
3.749V    -49.51mA   -29.74mA   -67.35mA
4.125V    -50.39mA   -29.89mA   -71.11mA
4.501V    -50.82mA   -29.98mA   -73.08mA
6.056V    -51.52mA   -30.63mA   -74.87mA
6.6V      -52.64mA   -31.23mA   -75.23mA
[POWER Clamp]
|   Voltage   I(typ)   I(min)   I(max)
-3.3V     224.5mA    191.3mA    262.6mA
-1.211V   38.57mA    34.7mA     44.22mA
-1.191V   37.07mA    33.44mA    42.47mA
-1.122V   31.9mA     29.08mA    36.46mA
-983.4mV  22.31mA    20.87mA    25.55mA
-825mV    14.08mA    12.89mA    17.14mA
-765.6mV  11.79mA    10.49mA    14.5mA
-636.9mV  7.356mA    6.549mA    9.06mA
-478.5mV  2.813mA    2.955mA    3.27mA
-399.3mV  1.162mA    1.587mA    1.159mA
-290.4mV  108.6uA    386.5uA    43.92uA
6.6V      0A         0A         0A
[Ramp]
R_load = 150
|   typ   min   max
dV/dt_r   1.36524/3.98873e-10   1.10938/5.23824e-10   1.59956/3.36172e-10
dV/dt_f   1.37491/4.21688e-10   1.13595/5.45545e-10   1.60155/3.55136e-10
[Falling Waveform]
V_fixture = 3.3V
V_fixture_min = 2.97V
V_fixture_max = 3.63V
R_fixture = 150Ohm
C_fixture = 0F
|   Time   V(typ)   V(min)   V(max)
0s        3.3V       2.969V     3.63V
1.335ns   3.302V     2.969V     3.623V
1.4ns     3.303V     2.969V     3.401V
1.59ns    3.309V     2.969V     2.224V
1.75ns    3.279V     2.97V      1.625V
2.19ns    1.675V     2.977V     1.08V
2.59ns    1.151V     2.955V     1.024V
3.215ns   1.05V      1.576V     980.1mV
3.865ns   1.024V     1.141V     970.3mV
10ns      1.008V     1.076V     960.4mV
[Rising Waveform]
V_fixture = 0V
V_fixture_min = 0V
V_fixture_max = 0V
R_fixture = 150Ohm
C_fixture = 0F
|   Time   V(typ)   V(min)   V(max)
0s        610.1uV    1.526mV    395.7uV
1.365ns   286.4uV    947.5uV    9.089mV
1.595ns   -2.069mV   735.8uV    1.482V
1.805ns   3.817mV    718.7uV    2.148V
2.12ns    1.373V     -778.8uV   2.468V
2.49ns    1.996V     -5.996mV   2.603V
2.77ns    2.137V     52.59mV    2.647V
3.385ns   2.265V     1.452V     2.662V
4.255ns   2.274V     1.816V     2.665V
10ns      2.276V     1.85V      2.666V
[Rising Waveform]
V_fixture = 3.3V
V_fixture_min = 2.97V
V_fixture_max = 3.63V
R_fixture = 150Ohm
C_fixture = 0F
|   Time   V(typ)   V(min)   V(max)
0s        1.008V     1.076V     960.4mV
1.34ns    1.008V     1.075V     1.005V
1.4ns     1.008V     1.075V     1.211V
1.645ns   1.052V     1.075V     2.872V
1.815ns   1.404V     1.075V     3.172V
2.06ns    2.62V      1.077V     3.418V
2.29ns    2.921V     1.138V     3.509V
2.97ns    3.213V     2.453V     3.596V
3.735ns   3.274V     2.849V     3.62V
10ns      3.3V       2.969V     3.63V
[Falling Waveform]
|Gnd
V_fixture = 0V
V_fixture_min = 0V
V_fixture_max = 0V
R_fixture = 150Ohm
C_fixture = 0F
|   Time   V(typ)   V(min)   V(max)
0s        2.276V     1.85V      2.666V
1.175ns   2.276V     1.85V      2.622V
1.355ns   2.267V     1.85V      2.139V
1.51ns    2.091V     1.85V      1.022V
1.625ns   1.824V     1.85V      541.2mV
1.97ns    562.6mV    1.791V     240.1mV
2.225ns   311mV      1.341V     136.7mV
2.82ns    105.4mV    384.3mV    54.22mV
3.51ns    44.83mV    123.2mV    25.35mV
10ns      618.8uV    1.528mV    396uV
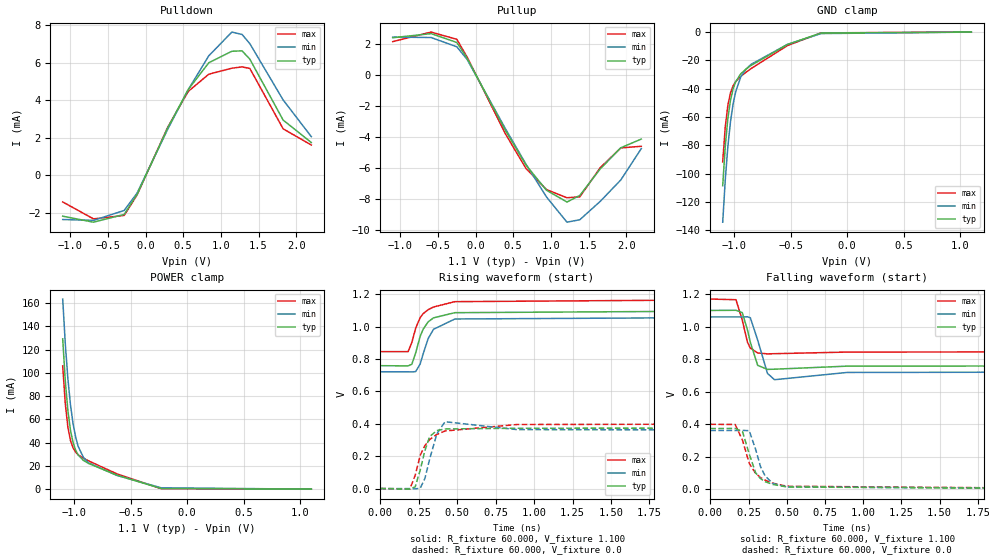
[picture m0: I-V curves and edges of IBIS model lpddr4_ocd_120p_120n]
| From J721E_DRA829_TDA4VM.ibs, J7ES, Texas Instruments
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|   Model lpddr4_ocd_120p_120n
[Model] lpddr4_ocd_120p_120n
Model_type I/O
Polarity   Non-Inverting
Enable   Active-High
Vinl =  0.113V
Vinh =  0.253V
Vmeas =  0.183V
C_comp   2.453pF   2.247pF   2.718pF
[Model Spec]
Vinh   0.253V   0.247V   0.265V
Vinl   0.113V   0.107V   0.125V
Vmeas   0.183V   0.176V   0.195V
[Temperature Range]   25.000   0.125k   -40.000
[Voltage Range]   1.100V   1.060V   1.170V
[Pullup Reference]   1.100V   1.060V   1.170V
[Pulldown Reference]   0.0V   0.0V   0.0V
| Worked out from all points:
|   slope of the pulldown table from 0 to 0.165 V, typ, clamps not added: 114 ohm
|   slope of the pullup table from 0 to 0.165 V, typ, clamps not added: 108 ohm
|   GND clamp passes 1 mA (typ) near -0.25 V on its own axis
|   POWER clamp passes 1 mA (typ) near -0.26 V on its own axis
|   rising waveform, R_fixture 60.000, V_fixture 1.100: 20-80 % time 86.7ps typ, 88.6ps min, 105ps max; typ from 0.759 V to 1.1 V
|   rising waveform, R_fixture 60.000, V_fixture 0.0: 20-80 % time 61.3ps typ, 57.4ps min, 117ps max; typ from 0.001 V to 0.373 V
|   falling waveform, R_fixture 60.000, V_fixture 1.100: 20-80 % time 53.1ps typ, 58ps min, 49.2ps max; typ from 1.1 V to 0.759 V
|   falling waveform, R_fixture 60.000, V_fixture 0.0: 20-80 % time 85.2ps typ, 80.6ps min, 112ps max; typ from 0.373 V to 0.001 V
[Pulldown]
|Voltage   I(typ)   I(min)   I(max)
-1.1V     -2.17mA    -2.347mA   -1.411mA
-692mV    -2.49mA    -2.394mA   -2.312mA
-284mV    -2.076mA   -1.864mA   -2.131mA
-113mV    -1.007mA   -941uA     -1.039mA
295mV     2.536mA    2.469mA    2.579mA
567mV     4.583mA    4.575mA    4.478mA
839mV     6.002mA    6.371mA    5.392mA
1.145V    6.613mA    7.635mA    5.711mA
1.281V    6.636mA    7.507mA    5.781mA
1.384V    6.192mA    7.019mA    5.698mA
1.826V    2.948mA    4.02mA     2.482mA
2.2V      1.753mA    2.066mA    1.621mA
[Pullup]
|Voltage   I(typ)   I(min)   I(max)
-1.1V     2.377mA    2.419mA    2.126mA
-590mV    2.643mA    2.391mA    2.741mA
-249mV    2.071mA    1.793mA    2.275mA
-113mV    1.062mA    984.2uA    1.135mA
397mV     -3.607mA   -3.493mA   -3.825mA
669mV     -5.828mA   -5.774mA   -6.048mA
941mV     -7.453mA   -7.884mA   -7.409mA
1.213V    -8.211mA   -9.512mA   -7.937mA
1.384V    -7.786mA   -9.352mA   -7.876mA
1.656V    -6.07mA    -8.163mA   -5.991mA
1.928V    -4.716mA   -6.787mA   -4.723mA
2.2V      -4.153mA   -4.766mA   -4.62mA
[GND_clamp]
|Voltage   I(typ)   I(min)   I(max)
-1.1V     -108.4mA   -134.2mA   -91.64mA
-1.077V   -80.17mA   -103.9mA   -66.63mA
-1.054V   -60.68mA   -80.47mA   -51.43mA
-1.031V   -48.01mA   -63.16mA   -42.83mA
-1.008V   -40.05mA   -50.75mA   -37.96mA
-985mV    -35.04mA   -42.04mA   -34.98mA
-940mV    -29.42mA   -31.64mA   -31.22mA
-894mV    -26.11mA   -26.16mA   -28.35mA
-848mV    -23.5mA    -22.73mA   -25.7mA
-527mV    -8.739mA   -8.686mA   -9.514mA
-229mV    -630.6uA   -1.042mA   -565.7uA
1.1V      0A         0A         0A
[POWER_clamp]
|Voltage   I(typ)   I(min)   I(max)
-1.1V     129.2mA    163.4mA    105.9mA
-1.077V   92.86mA    124.8mA    73.4mA
-1.054V   67.3mA     94.73mA    53.17mA
-1.031V   50.48mA    72.25mA    41.67mA
-1.008V   39.92mA    56.03mA    35.37mA
-985mV    33.38mA    44.6mA     31.76mA
-963mV    29.31mA    36.69mA    29.53mA
-917mV    24.75mA    27.38mA    26.61mA
-871mV    22.09mA    22.57mA    24.31mA
-619mV    11.98mA    11.76mA    13.12mA
-229mV    602.6uA    1.183mA    400.7uA
1.1V      0A         0A         0A
[Ramp]
| variable   typ   min   max
dV/dt_r   0.224/61.123p   0.216/57.709p   0.239/0.116n
dV/dt_f   0.205/52.506p   0.203/57.226p   0.195/48.592p
R_load = 60.000
[Rising Waveform]
R_fixture= 60.000
V_fixture= 1.100
V_fixture_min= 1.060
V_fixture_max= 1.170
|time   V(typ)   V(min)   V(max)
0s        759mV      721.5mV    845.6mV
181ps     757.7mV    721.3mV    845.7mV
205ps     767.9mV    720.5mV    901.5mV
230ps     837.4mV    722.4mV    989.5mV
259ps     939.3mV    768.7mV    1.055V
279ps     984.4mV    832.4mV    1.08V
311ps     1.029V     925.5mV    1.104V
346ps     1.054V     983.3mV    1.121V
485ps     1.086V     1.047V     1.154V
3ns       1.1V       1.06V      1.17V
[Rising Waveform]
R_fixture= 60.000
V_fixture= 0.0
V_fixture_min= 0.0
V_fixture_max= 0.0
|time   V(typ)   V(min)   V(max)
0s        651.5uV    1.182mV    1.114mV
193ps     -3mV       229.5uV    -1.756mV
227ps     11.36mV    -1.316mV   83.04mV
260ps     116.2mV    3.082mV    206.3mV
290ps     234.4mV    63.08mV    266.3mV
321ps     321.5mV    182.4mV    302.6mV
368ps     358.7mV    338.7mV    334.9mV
421ps     368.4mV    413.1mV    356mV
889ps     373mV      364.4mV    395.9mV
3ns       373.5mV    361.4mV    399.7mV
[Falling Waveform]
R_fixture= 60.000
V_fixture= 1.100
V_fixture_min= 1.060
V_fixture_max= 1.170
|time   V(typ)   V(min)   V(max)
0s        1.1V       1.06V      1.17V
168ps     1.101V     1.06V      1.166V
209ps     1.087V     1.06V      1.041V
243ps     980.5mV    1.061V     905.3mV
262ps     903.8mV    1.055V     868mV
310ps     762.1mV    917.3mV    838.4mV
374ps     737.5mV    712.7mV    832.8mV
420ps     738.6mV    673.9mV    834mV
894ps     757.4mV    718.5mV    843.9mV
3ns       759mV      721.5mV    845.7mV
[Falling Waveform]
R_fixture= 60.000
V_fixture= 0.0
V_fixture_min= 0.0
V_fixture_max= 0.0
|time   V(typ)   V(min)   V(max)
0s        373.5mV    361.4mV    399.7mV
163ps     374.2mV    361.4mV    398.4mV
211ps     354.1mV    362.3mV    300.6mV
255ps     215.5mV    360.2mV    159.1mV
297ps     101mV      243.7mV    96.94mV
329ps     65.19mV    138mV      71.94mV
359ps     46.88mV    81.52mV    55.83mV
409ps     29.76mV    35.68mV    37.49mV
501ps     14.13mV    14.98mV    18.66mV
3ns       650.5uV    1.18mV     1.114mV
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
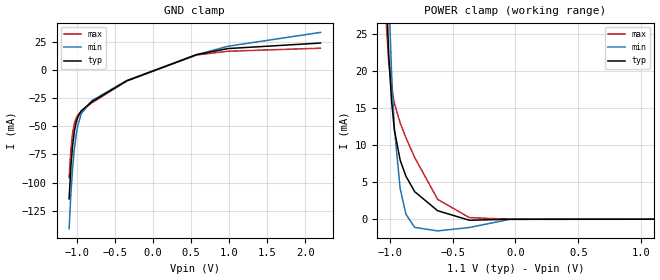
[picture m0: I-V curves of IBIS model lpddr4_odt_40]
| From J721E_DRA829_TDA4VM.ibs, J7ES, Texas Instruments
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|   Model lpddr4_odt_40
[Model] lpddr4_odt_40
Model_type Input
Polarity   Non-Inverting
Enable   Active-High
Vinl =  0.113V
Vinh =  0.253V
C_comp   1.480pF   1.310pF   1.728pF
[Model Spec]
Vinh   0.253V   0.247V   0.265V
Vinl   0.113V   0.107V   0.125V
[Temperature Range]   25.000   0.125k   -40.000
[Voltage Range]   1.100V   1.060V   1.170V
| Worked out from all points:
|   GND clamp passes 1 mA (typ) near -0.04 V on its own axis
|   POWER clamp passes 1 mA (typ) near -0.60 V on its own axis
[GND_clamp]
|Voltage   I(typ)   I(min)   I(max)
-1.1V     -114.4mA   -140.9mA   -95.72mA
-1.077V   -86.39mA   -110.6mA   -70.9mA
-1.054V   -67.05mA   -87.31mA   -55.87mA
-1.031V   -54.51mA   -70.08mA   -47.43mA
-1.008V   -46.66mA   -57.73mA   -42.72mA
-985mV    -41.73mA   -49.06mA   -39.88mA
-940mV    -36.24mA   -38.72mA   -36.41mA
-802mV    -28.17mA   -27.2mA    -29.15mA
-344mV    -9.547mA   -9.28mA    -9.77mA
573mV     13.74mA    13.69mA    13.41mA
985mV     19.13mA    21.17mA    16.73mA
2.2V      24.04mA    33.49mA    19.47mA
[POWER_clamp]
|Voltage   I(typ)   I(min)   I(max)
-1.1V     110.5mA    135.9mA    91.01mA
-1.031V   32.59mA    46.28mA    27.4mA
-1.008V   22.26mA    30.56mA    21.25mA
-985mV    15.94mA    19.66mA    17.77mA
-963mV    12.09mA    12.29mA    15.68mA
-917mV    7.98mA     4.15mA     13.02mA
-871mV    5.813mA    674.9uA    11.01mA
-802mV    3.732mA    -1.099mA   8.361mA
-619mV    1.152mA    -1.579mA   2.69mA
-367mV    -134.8uA   -1.12mA    222.7uA
-45.83mV  -6.589uA   -15.91uA   -1.983uA
1.1V      0A         0A         0A
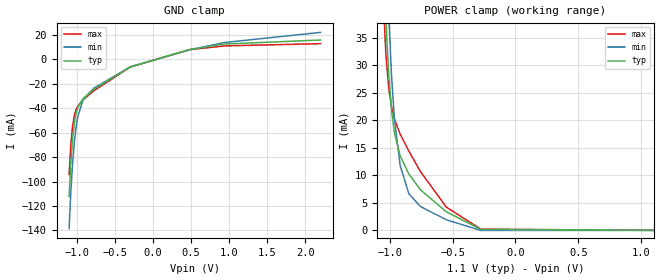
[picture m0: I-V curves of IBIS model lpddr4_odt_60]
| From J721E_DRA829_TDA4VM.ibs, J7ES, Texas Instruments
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|   Model lpddr4_odt_60
[Model] lpddr4_odt_60
Model_type Input
Polarity   Non-Inverting
Enable   Active-High
Vinl =  0.113V
Vinh =  0.253V
C_comp   1.892pF   1.705pF   2.160pF
[Model Spec]
Vinh   0.253V   0.247V   0.265V
Vinl   0.113V   0.107V   0.125V
[Temperature Range]   25.000   0.125k   -40.000
[Voltage Range]   1.100V   1.060V   1.170V
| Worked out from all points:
|   GND clamp passes 1 mA (typ) near -0.05 V on its own axis
|   POWER clamp passes 1 mA (typ) near -0.37 V on its own axis
[GND_clamp]
|Voltage   I(typ)   I(min)   I(max)
-1.1V     -112.2mA   -138.5mA   -94.29mA
-1.077V   -84.14mA   -108.2mA   -69.4mA
-1.054V   -64.75mA   -84.89mA   -54.31mA
-1.031V   -52.17mA   -67.63mA   -45.81mA
-1.008V   -44.28mA   -55.27mA   -41.04mA
-985mV    -39.32mA   -46.59mA   -38.14mA
-917mV    -32.03mA   -33.13mA   -33.16mA
-779mV    -24.54mA   -23.6mA    -25.79mA
-298mV    -6.096mA   -6.063mA   -6.243mA
481mV     8.054mA    7.938mA    7.994mA
940mV     12.64mA    13.88mA    11.09mA
2.2V      15.9mA     22.15mA    12.93mA
[POWER_clamp]
|Voltage   I(typ)   I(min)   I(max)
-1.1V     116.8mA    145.1mA    95.93mA
-1.054V   55.21mA    77.11mA    43.51mA
-1.031V   38.54mA    54.94mA    32.12mA
-1.008V   28.13mA    39.03mA    25.91mA
-985mV    21.73mA    27.93mA    22.39mA
-963mV    17.8mA     20.36mA    20.24mA
-917mV    13.52mA    11.77mA    17.49mA
-848mV    10.27mA    6.664mA    14.41mA
-756mV    7.373mA    4.338mA    10.7mA
-550mV    3.376mA    1.931mA    4.228mA
-275mV    171.2uA    -22.07uA   219.9uA
1.1V      0A         0A         0A
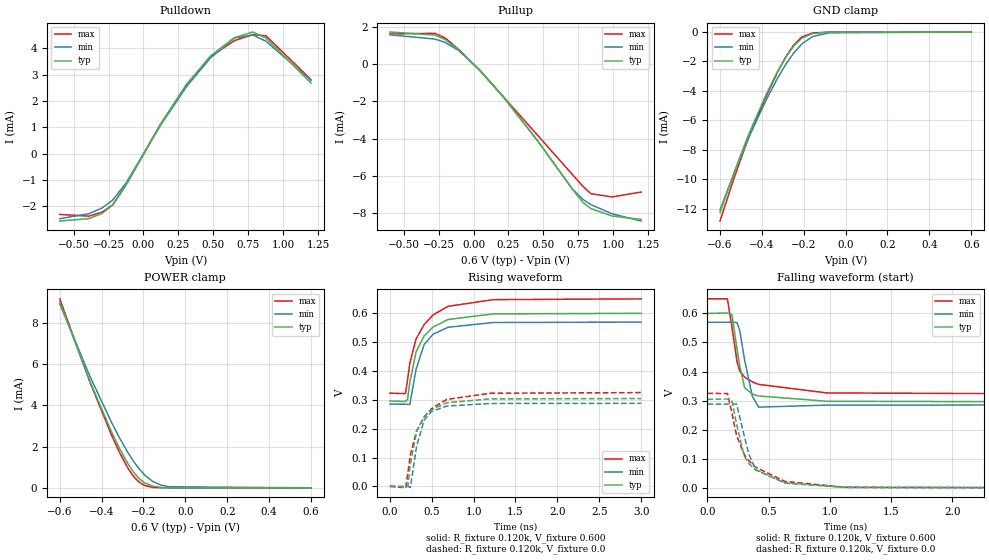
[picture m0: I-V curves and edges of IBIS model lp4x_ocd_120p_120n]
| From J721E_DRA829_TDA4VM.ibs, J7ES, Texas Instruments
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|   Model lp4x_ocd_120p_120n
[Model] lp4x_ocd_120p_120n
Model_type I/O
Polarity   Non-Inverting
Enable   Active-High
Vinl =  0.0V
Vinh =  0.900V
Vmeas =  0.600V
C_comp   2.703pF   2.488pF   2.945pF
[Model Spec]
Vinh   0.900V   0.900V   0.900V
Vinl   0.0V   0.0V   0.0V
Vmeas   0.600V   NA   NA
[Temperature Range]   25.000   0.125k   -40.000
[Voltage Range]   0.600V   0.570V   0.650V
[Pullup Reference]   0.600V   0.570V   0.650V
[Pulldown Reference]   0.0V   0.0V   0.0V
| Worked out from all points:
|   slope of the pulldown table from 0 to 0.09 V, typ, clamps not added: 109 ohm
|   slope of the pullup table from 0 to 0.09 V, typ, clamps not added: 127 ohm
|   GND clamp passes 1 mA (typ) near -0.25 V on its own axis
|   POWER clamp passes 1 mA (typ) near -0.26 V on its own axis
|   rising waveform, R_fixture 0.120k, V_fixture 0.600: 20-80 % time 227ps typ, 186ps min, 260ps max; typ from 0.296 V to 0.6 V
|   rising waveform, R_fixture 0.120k, V_fixture 0.0: 20-80 % time 178ps typ, 137ps min, 242ps max; typ from 0 V to 0.304 V
|   falling waveform, R_fixture 0.120k, V_fixture 0.600: 20-80 % time 71.7ps typ, 73.6ps min, 95ps max; typ from 0.6 V to 0.296 V
|   falling waveform, R_fixture 0.120k, V_fixture 0.0: 20-80 % time 168ps typ, 125ps min, 212ps max; typ from 0.304 V to 0 V
[Pulldown]
|Voltage   I(typ)   I(min)   I(max)
-600mV    -2.567mA   -2.478mA   -2.316mA
-392mV    -2.478mA   -2.29mA    -2.382mA
-297mV    -2.279mA   -2.073mA   -2.233mA
-221mV    -1.959mA   -1.772mA   -1.955mA
-126mV    -1.201mA   -1.126mA   -1.197mA
120mV     1.095mA    1.056mA    1.092mA
309mV     2.63mA     2.551mA    2.625mA
480mV     3.712mA    3.64mA     3.681mA
651mV     4.408mA    4.396mA    4.295mA
783mV     4.624mA    4.511mA    4.525mA
878mV     4.393mA    4.273mA    4.48mA
1.2V      2.687mA    2.788mA    2.814mA
[Pullup]
|Voltage   I(typ)   I(min)   I(max)
-600mV    1.704mA    1.554mA    1.602mA
-278mV    1.546mA    1.328mA    1.636mA
-202mV    1.3mA      1.14mA     1.377mA
-107mV    746uA      709.2uA    775uA
44.21mV   -340.2uA   -337.2uA   -347.7uA
215mV     -1.795mA   -1.78mA    -1.78mA
461mV     -4.139mA   -4.147mA   -3.846mA
707mV     -6.701mA   -6.694mA   -5.921mA
783mV     -7.419mA   -7.257mA   -6.556mA
840mV     -7.752mA   -7.538mA   -6.952mA
992mV     -8.148mA   -8.03mA    -7.126mA
1.2V      -8.333mA   -8.417mA   -6.869mA
[GND_clamp]
|Voltage   I(typ)   I(min)   I(max)
-600mV    -12.26mA   -12.07mA   -12.83mA
-535mV    -9.631mA   -9.657mA   -9.999mA
-483mV    -7.674mA   -7.84mA    -7.926mA
-457mV    -6.749mA   -6.974mA   -6.957mA
-378mV    -4.198mA   -4.571mA   -4.306mA
-326mV    -2.706mA   -3.156mA   -2.747mA
-287mV    -1.735mA   -2.22mA    -1.722mA
-248mV    -949.8uA   -1.424mA   -887.8uA
-209mV    -414uA     -806.6uA   -336.6uA
-157mV    -95.46uA   -302uA     -61.63uA
-78.26mV  -9.109uA   -53.02uA   -8.174uA
600mV     0A         0A         0A
[POWER_clamp]
|Voltage   I(typ)   I(min)   I(max)
-600mV    9.037mA    8.928mA    9.175mA
-457mV    5.197mA    5.441mA    5.165mA
-352mV    2.698mA    3.164mA    2.544mA
-313mV    1.878mA    2.4mA      1.683mA
-274mV    1.164mA    1.707mA    946.7uA
-248mV    770.4uA    1.297mA    560.3uA
-222mV    461.7uA    938.3uA    283.8uA
-196mV    245.9uA    638.8uA    120.5uA
-157mV    79.31uA    316.3uA    23.54uA
-117mV    22.66uA    136.3uA    6.083uA
-78.26mV  6.711uA    54.45uA    1.892uA
600mV     0A         0A         0A
[Ramp]
| variable   typ   min   max
dV/dt_r   0.183/0.177n   0.172/0.137n   0.195/0.245n
dV/dt_f   0.183/71.948p   0.171/73.576p   0.197/93.781p
R_load = 0.120k
[Rising Waveform]
R_fixture= 0.120k
V_fixture= 0.600
V_fixture_min= 0.570
V_fixture_max= 0.650
|time   V(typ)   V(min)   V(max)
0s        296.1mV    285.4mV    323.1mV
186ps     294.2mV    284.8mV    321.6mV
211ps     301.2mV    284.4mV    369.4mV
238ps     360.2mV    283.8mV    426.3mV
312ps     465.7mV    404.7mV    510.8mV
409ps     521.4mV    491.7mV    560.9mV
516ps     552.1mV    527.4mV    594.4mV
695ps     578.5mV    551.6mV    624.2mV
1.235ns   597.9mV    568.1mV    647.3mV
3ns       599.9mV    569.5mV    650mV
[Rising Waveform]
R_fixture= 0.120k
V_fixture= 0.0
V_fixture_min= 0.0
V_fixture_max= 0.0
|time   V(typ)   V(min)   V(max)
0s        169.9uV    895.7uV    158uV
190ps     -2.695mV   157.6uV    -4.968mV
216ps     4.103mV    -237.8uV   49.29mV
245ps     78.47mV    -3.642mV   110.3mV
319ps     190.4mV    139.1mV    192.2mV
410ps     241.7mV    230.2mV    240.7mV
499ps     266.3mV    260.1mV    270mV
679ps     290mV      278.5mV    301.4mV
1.198ns   303.4mV    287.4mV    322.9mV
3ns       304.5mV    288mV      325.2mV
[Falling Waveform]
R_fixture= 0.120k
V_fixture= 0.600
V_fixture_min= 0.570
V_fixture_max= 0.650
|time   V(typ)   V(min)   V(max)
0s        599.9mV    569.5mV    650mV
163ps     601.2mV    569.5mV    650mV
200ps     595mV      570.6mV    552.6mV
242ps     475.8mV    568.1mV    433.2mV
263ps     420.7mV    542mV      402.6mV
303ps     344.9mV    440.6mV    381.2mV
366ps     322.5mV    315.7mV    364.7mV
418ps     316.1mV    277.7mV    355.9mV
977ps     297.8mV    284.7mV    326.5mV
3ns       296.1mV    285.3mV    323.1mV
[Falling Waveform]
R_fixture= 0.120k
V_fixture= 0.0
V_fixture_min= 0.0
V_fixture_max= 0.0
|time   V(typ)   V(min)   V(max)
0s        304.5mV    288mV      325.2mV
163ps     305.7mV    288mV      324.5mV
200ps     298.9mV    289mV      257.2mV
238ps     217.6mV    288.1mV    179.4mV
301ps     109.6mV    178mV      113.7mV
338ps     83.53mV    116.1mV    93.59mV
393ps     61.54mV    63.04mV    71.12mV
634ps     17.7mV     16.08mV    22.09mV
1.128ns   1.579mV    1.979mV    2.163mV
3ns       165.5uV    878.4uV    153.4uV
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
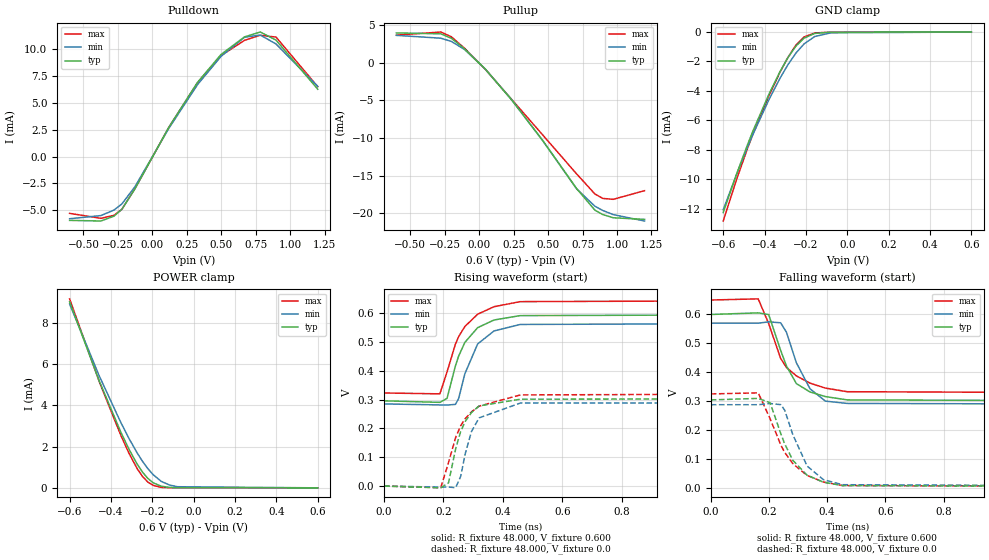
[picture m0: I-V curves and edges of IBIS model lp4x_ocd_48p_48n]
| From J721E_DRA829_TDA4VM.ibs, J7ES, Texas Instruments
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|   Model lp4x_ocd_48p_48n
[Model] lp4x_ocd_48p_48n
Model_type I/O
Polarity   Non-Inverting
Enable   Active-High
Vinl =  0.0V
Vinh =  0.900V
Vmeas =  0.600V
C_comp   1.973pF   1.767pF   2.244pF
[Model Spec]
Vinh   0.900V   0.900V   0.900V
Vinl   0.0V   0.0V   0.0V
Vmeas   0.600V   NA   NA
[Temperature Range]   25.000   0.125k   -40.000
[Voltage Range]   0.600V   0.570V   0.650V
[Pullup Reference]   0.600V   0.570V   0.650V
[Pulldown Reference]   0.0V   0.0V   0.0V
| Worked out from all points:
|   slope of the pulldown table from 0 to 0.09 V, typ, clamps not added: 43.5 ohm
|   slope of the pullup table from 0 to 0.09 V, typ, clamps not added: 50.7 ohm
|   GND clamp passes 1 mA (typ) near -0.25 V on its own axis
|   POWER clamp passes 1 mA (typ) near -0.26 V on its own axis
|   rising waveform, R_fixture 48.000, V_fixture 0.600: 20-80 % time 76.7ps typ, 71.5ps min, 89.3ps max; typ from 0.296 V to 0.6 V
|   rising waveform, R_fixture 48.000, V_fixture 0.0: 20-80 % time 57.4ps typ, 53.1ps min, 83.6ps max; typ from 0 V to 0.304 V
|   falling waveform, R_fixture 48.000, V_fixture 0.600: 20-80 % time 77.2ps typ, 73.2ps min, 98.5ps max; typ from 0.6 V to 0.296 V
|   falling waveform, R_fixture 48.000, V_fixture 0.0: 20-80 % time 86.7ps typ, 79.6ps min, 104ps max; typ from 0.304 V to 0 V
[Pulldown]
|Voltage   I(typ)   I(min)   I(max)
-600mV    -5.949mA   -5.796mA   -5.294mA
-373mV    -6.008mA   -5.5mA     -5.758mA
-278mV    -5.553mA   -4.987mA   -5.475mA
-221mV    -4.916mA   -4.417mA   -4.916mA
-126mV    -3.003mA   -2.809mA   -2.99mA
120mV     2.736mA    2.638mA    2.726mA
328mV     6.916mA    6.708mA    6.893mA
499mV     9.527mA    9.349mA    9.421mA
669mV     11.16mA    11.13mA    10.84mA
783mV     11.61mA    11.33mA    11.31mA
897mV     10.86mA    10.5mA     11.14mA
1.2V      6.276mA    6.54mA     6.514mA
[Pullup]
|Voltage   I(typ)   I(min)   I(max)
-600mV    3.948mA    3.622mA    3.66mA
-278mV    3.827mA    3.247mA    4.065mA
-202mV    3.241mA    2.821mA    3.442mA
-107mV    1.862mA    1.766mA    1.934mA
44.21mV   -849.1uA   -842uA     -867.5uA
234mV     -4.908mA   -4.87mA    -4.843mA
461mV     -10.33mA   -10.35mA   -9.595mA
707mV     -16.72mA   -16.75mA   -14.77mA
840mV     -19.59mA   -19.07mA   -17.44mA
897mV     -20.17mA   -19.63mA   -18.03mA
973mV     -20.6mA    -20.18mA   -18.15mA
1.2V      -20.81mA   -21.03mA   -17mA
[GND_clamp]
|Voltage   I(typ)   I(min)   I(max)
-600mV    -12.26mA   -12.07mA   -12.83mA
-535mV    -9.631mA   -9.657mA   -9.999mA
-483mV    -7.674mA   -7.84mA    -7.926mA
-457mV    -6.749mA   -6.974mA   -6.957mA
-378mV    -4.198mA   -4.571mA   -4.306mA
-326mV    -2.706mA   -3.156mA   -2.747mA
-287mV    -1.735mA   -2.22mA    -1.722mA
-248mV    -949.8uA   -1.424mA   -887.8uA
-209mV    -414uA     -806.6uA   -336.6uA
-157mV    -95.47uA   -302uA     -61.62uA
-78.26mV  -9.126uA   -53.02uA   -8.175uA
600mV     0A         0A         0A
[POWER_clamp]
|Voltage   I(typ)   I(min)   I(max)
-600mV    9.037mA    8.928mA    9.175mA
-457mV    5.197mA    5.441mA    5.165mA
-352mV    2.698mA    3.164mA    2.543mA
-313mV    1.878mA    2.4mA      1.682mA
-274mV    1.164mA    1.707mA    945.3uA
-248mV    770.4uA    1.297mA    559uA
-222mV    461.7uA    938.3uA    283.6uA
-196mV    245.9uA    638.8uA    120.5uA
-157mV    79.31uA    316.3uA    23.54uA
-117mV    22.66uA    136.3uA    6.079uA
-78.26mV  6.71uA     54.45uA    1.893uA
600mV     0A         0A         0A
[Ramp]
| variable   typ   min   max
dV/dt_r   0.183/57.226p   0.172/52.795p   0.195/83.291p
dV/dt_f   0.183/76.895p   0.171/72.842p   0.196/97.641p
R_load = 48.000
[Rising Waveform]
R_fixture= 48.000
V_fixture= 0.600
V_fixture_min= 0.570
V_fixture_max= 0.650
|time   V(typ)   V(min)   V(max)
0s        296mV      285.2mV    323.3mV
188ps     290.7mV    281.8mV    320.2mV
212ps     304.5mV    281.4mV    396.3mV
240ps     416.4mV    283.5mV    492.3mV
251ps     451.3mV    303.7mV    518.8mV
272ps     498.9mV    390.1mV    554.1mV
315ps     550.1mV    493.5mV    596.7mV
370ps     576.6mV    538.6mV    622.8mV
458ps     591.9mV    561.2mV    640.4mV
3ns       600mV      569.8mV    650mV
[Rising Waveform]
R_fixture= 48.000
V_fixture= 0.0
V_fixture_min= 0.0
V_fixture_max= 0.0
|time   V(typ)   V(min)   V(max)
0s        49.37uV    265.6uV    48.48uV
191ps     -6.112mV   -3.674mV   -5.413mV
217ps     11.2mV     -3.217mV   81.64mV
241ps     129.3mV    -5.726mV   168.8mV
258ps     190mV      33.7mV     209.6mV
273ps     224mV      111.1mV    233.8mV
294ps     255.1mV    189mV      257.7mV
320ps     278.4mV    236.9mV    277.7mV
459ps     301.7mV    288.5mV    316.5mV
3ns       304.3mV    287.7mV    325mV
[Falling Waveform]
R_fixture= 48.000
V_fixture= 0.600
V_fixture_min= 0.570
V_fixture_max= 0.650
|time   V(typ)   V(min)   V(max)
0s        600mV      569.8mV    650mV
163ps     605.5mV    569.8mV    654mV
199ps     599.7mV    574.5mV    568.2mV
240ps     475.9mV    571.3mV    448mV
260ps     421.8mV    538.6mV    416.6mV
294ps     360.9mV    433.1mV    387.6mV
341ps     331.8mV    342.8mV    362.3mV
394ps     315.8mV    300.1mV    345.2mV
469ps     304.4mV    292.2mV    332.7mV
3ns       296mV      285.2mV    323.3mV
[Falling Waveform]
R_fixture= 48.000
V_fixture= 0.0
V_fixture_min= 0.0
V_fixture_max= 0.0
|time   V(typ)   V(min)   V(max)
0s        304.3mV    287.7mV    325mV
163ps     309.6mV    287.7mV    328.7mV
204ps     294.5mV    291.9mV    238.9mV
241ps     186.3mV    287.9mV    147.6mV
254ps     152.4mV    268.7mV    122.4mV
282ps     95.2mV     184mV      83.71mV
331ps     43.84mV    75.49mV    42.85mV
387ps     19.55mV    28.38mV    20.13mV
453ps     7.779mV    10.92mV    8.129mV
3ns       48.92uV    263.3uV    47.6uV
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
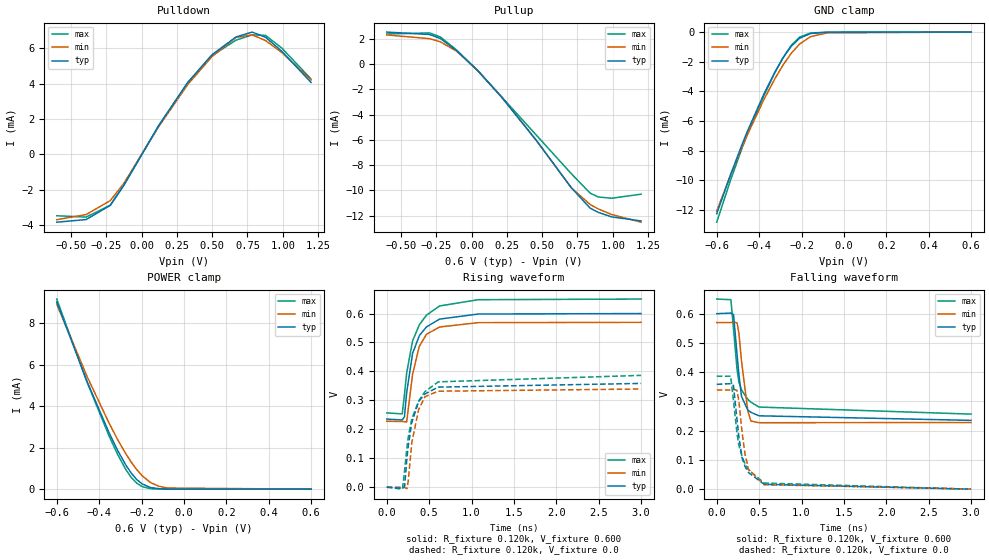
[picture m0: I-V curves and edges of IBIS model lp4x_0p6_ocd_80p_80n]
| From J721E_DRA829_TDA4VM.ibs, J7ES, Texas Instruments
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|   Model lp4x_0p6_ocd_80p_80n
[Model] lp4x_0p6_ocd_80p_80n
Model_type I/O
Polarity   Non-Inverting
Enable   Active-High
Vinl =  0.0V
Vinh =  0.900V
Vmeas =  0.600V
C_comp   2.488pF   2.282pF   2.735pF
[Model Spec]
Vinh   0.900V   0.900V   0.900V
Vinl   0.0V   0.0V   0.0V
Vmeas   0.600V   NA   NA
[Temperature Range]   25.000   0.125k   -40.000
[Voltage Range]   0.600V   0.570V   0.650V
[Pullup Reference]   0.600V   0.570V   0.650V
[Pulldown Reference]   0.0V   0.0V   0.0V
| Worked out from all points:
|   slope of the pulldown table from 0 to 0.09 V, typ, clamps not added: 74 ohm
|   slope of the pullup table from 0 to 0.09 V, typ, clamps not added: 86.1 ohm
|   GND clamp passes 1 mA (typ) near -0.25 V on its own axis
|   POWER clamp passes 1 mA (typ) near -0.26 V on its own axis
|   rising waveform, R_fixture 0.120k, V_fixture 0.600: 20-80 % time 162ps typ, 141ps min, 192ps max; typ from 0.235 V to 0.6 V
|   rising waveform, R_fixture 0.120k, V_fixture 0.0: 20-80 % time 128ps typ, 114ps min, 181ps max; typ from 0 V to 0.359 V
|   falling waveform, R_fixture 0.120k, V_fixture 0.600: 20-80 % time 77.2ps typ, 77.1ps min, 106ps max; typ from 0.6 V to 0.235 V
|   falling waveform, R_fixture 0.120k, V_fixture 0.0: 20-80 % time 121ps typ, 103ps min, 157ps max; typ from 0.359 V to 0 V
[Pulldown]
|Voltage   I(typ)   I(min)   I(max)
-600mV    -3.84mA    -3.699mA   -3.476mA
-392mV    -3.691mA   -3.408mA   -3.551mA
-221mV    -2.888mA   -2.618mA   -2.88mA
-126mV    -1.762mA   -1.654mA   -1.752mA
120mV     1.608mA    1.553mA    1.601mA
328mV     4.08mA     3.962mA    4.066mA
499mV     5.646mA    5.542mA    5.589mA
669mV     6.648mA    6.625mA    6.469mA
783mV     6.925mA    6.768mA    6.766mA
878mV     6.633mA    6.446mA    6.738mA
992mV     5.848mA    5.771mA    6.028mA
1.2V      4.074mA    4.222mA    4.268mA
[Pullup]
|Voltage   I(typ)   I(min)   I(max)
-600mV    2.551mA    2.325mA    2.405mA
-297mV    2.36mA     2.029mA    2.483mA
-221mV    2.046mA    1.782mA    2.169mA
-107mV    1.101mA    1.049mA    1.141mA
44.21mV   -500.6uA   -496.7uA   -510.5uA
215mV     -2.634mA   -2.615mA   -2.609mA
461mV     -6.059mA   -6.075mA   -5.643mA
707mV     -9.795mA   -9.802mA   -8.683mA
840mV     -11.41mA   -11.12mA   -10.22mA
897mV     -11.74mA   -11.47mA   -10.52mA
992mV     -12.1mA    -11.91mA   -10.62mA
1.2V      -12.42mA   -12.52mA   -10.3mA
[GND_clamp]
|Voltage   I(typ)   I(min)   I(max)
-600mV    -12.26mA   -12.07mA   -12.83mA
-535mV    -9.631mA   -9.657mA   -9.998mA
-483mV    -7.674mA   -7.84mA    -7.926mA
-457mV    -6.749mA   -6.974mA   -6.957mA
-378mV    -4.198mA   -4.571mA   -4.306mA
-326mV    -2.706mA   -3.156mA   -2.747mA
-287mV    -1.735mA   -2.22mA    -1.722mA
-248mV    -949.7uA   -1.424mA   -887.8uA
-209mV    -414uA     -806.5uA   -336.6uA
-157mV    -95.45uA   -302uA     -61.63uA
-78.26mV  -9.109uA   -53.02uA   -8.174uA
600mV     0A         0A         0A
[POWER_clamp]
|Voltage   I(typ)   I(min)   I(max)
-600mV    9.037mA    8.928mA    9.175mA
-457mV    5.197mA    5.441mA    5.165mA
-352mV    2.698mA    3.164mA    2.544mA
-313mV    1.878mA    2.4mA      1.683mA
-274mV    1.164mA    1.707mA    946.7uA
-248mV    770.4uA    1.297mA    560.1uA
-222mV    461.7uA    938.4uA    283.8uA
-196mV    245.9uA    638.8uA    120.5uA
-157mV    79.31uA    316.3uA    23.58uA
-117mV    22.66uA    136.3uA    6.081uA
-78.26mV  6.702uA    54.45uA    1.892uA
600mV     0A         0A         0A
[Ramp]
| variable   typ   min   max
dV/dt_r   0.215/0.128n   0.203/0.114n   0.232/0.183n
dV/dt_f   0.219/77.235p   0.206/76.850p   0.237/0.106n
R_load = 0.120k
[Rising Waveform]
R_fixture= 0.120k
V_fixture= 0.600
V_fixture_min= 0.570
V_fixture_max= 0.650
|time   V(typ)   V(min)   V(max)
0s        235.4mV    227.9mV    256.7mV
183ps     232.4mV    227.1mV    253.4mV
209ps     243.9mV    226.3mV    320.2mV
235ps     326.5mV    225.2mV    394.3mV
305ps     462.3mV    391.4mV    505.7mV
385ps     523.9mV    487mV      561.3mV
469ps     553.9mV    528.4mV    594.5mV
624ps     580.8mV    553.5mV    626.2mV
1.079ns   598.3mV    568.5mV    647.8mV
3ns       600mV      569.6mV    650mV
[Rising Waveform]
R_fixture= 0.120k
V_fixture= 0.0
V_fixture_min= 0.0
V_fixture_max= 0.0
|time   V(typ)   V(min)   V(max)
0s        133.9uV    677uV      122.4uV
185ps     -3.253mV   -327.9uV   -6.706mV
211ps     3.257mV    -914.1uV   57.91mV
238ps     99.24mV    -5.186mV   136.4mV
253ps     140.6mV    19.5mV     171.8mV
295ps     222.9mV    152.9mV    234.9mV
376ps     295.9mV    267.9mV    297.5mV
451ps     322.4mV    312.8mV    330.6mV
608ps     345.8mV    331.7mV    364mV
3ns       358.6mV    339.3mV    386.4mV
[Falling Waveform]
R_fixture= 0.120k
V_fixture= 0.600
V_fixture_min= 0.570
V_fixture_max= 0.650
|time   V(typ)   V(min)   V(max)
0s        600mV      569.6mV    650mV
167ps     602.1mV    569.6mV    647.9mV
198ps     597.2mV    571.5mV    547.4mV
240ps     459.2mV    568.4mV    408.2mV
261ps     394.2mV    534.4mV    366.5mV
292ps     317.4mV    438.7mV    339.1mV
366ps     270.5mV    268.7mV    307.4mV
402ps     263mV      233.2mV    297.8mV
498ps     250.9mV    227.3mV    280.8mV
3ns       235.3mV    227.9mV    256.7mV
[Falling Waveform]
R_fixture= 0.120k
V_fixture= 0.0
V_fixture_min= 0.0
V_fixture_max= 0.0
|time   V(typ)   V(min)   V(max)
0s        358.6mV    339.3mV    386.4mV
164ps     360.7mV    339.3mV    386.4mV
198ps     353.9mV    341.2mV    302.2mV
238ps     241mV      338.3mV    193.3mV
261ps     180.2mV    301.6mV    150.2mV
300ps     106.6mV    191.9mV    109.8mV
334ps     77.55mV    119.2mV    87.05mV
375ps     56.78mV    67.59mV    66.6mV
559ps     16.65mV    15.33mV    20.98mV
3ns       130.2uV    664.1uV    119.5uV
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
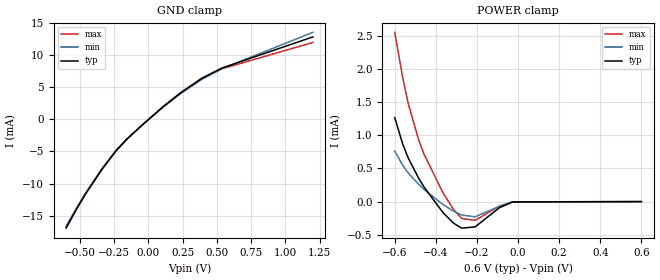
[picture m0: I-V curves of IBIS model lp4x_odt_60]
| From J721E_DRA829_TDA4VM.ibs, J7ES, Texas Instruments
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|   Model lp4x_odt_60
[Model] lp4x_odt_60
Model_type Input
Polarity   Non-Inverting
Enable   Active-High
Vinl =  0.0V
Vinh =  0.900V
C_comp   2.279pF   2.062pF   2.475pF
[Model Spec]
Vinh   0.900V   0.900V   0.900V
Vinl   0.0V   0.0V   0.0V
[Temperature Range]   25.000   0.125k   -40.000
[Voltage Range]   0.600V   0.570V   0.650V
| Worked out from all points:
|   GND clamp passes 1 mA (typ) near -0.05 V on its own axis
|   POWER clamp passes 1 mA (typ) near -0.58 V on its own axis
[GND_clamp]
|Voltage   I(typ)   I(min)   I(max)
-600mV    -16.93mA   -16.64mA   -16.97mA
-522mV    -13.92mA   -13.76mA   -13.83mA
-457mV    -11.59mA   -11.51mA   -11.47mA
-339mV    -7.791mA   -7.785mA   -7.692mA
-235mV    -4.866mA   -4.887mA   -4.786mA
-157mV    -3.092mA   -3.059mA   -3.058mA
-52.17mV  -1.007mA   -983.6uA   -1.002mA
104mV     1.937mA    1.861mA    1.931mA
235mV     4.167mA    4.023mA    4.157mA
391mV     6.444mA    6.271mA    6.417mA
535mV     8.02mA     7.907mA    7.899mA
1.2V      12.89mA    13.6mA     12.02mA
[POWER_clamp]
|Voltage   I(typ)   I(min)   I(max)
-600mV    1.268mA    762.8uA    2.553mA
-561mV    866.2uA    546.2uA    1.87mA
-535mV    661.6uA    434.9uA    1.488mA
-483mV    349.4uA    258uA      924.5uA
-457mV    218.4uA    181.9uA    711.7uA
-365mV    -167.2uA   -45.11uA   131.9uA
-313mV    -327.4uA   -146.2uA   -123.9uA
-274mV    -400.2uA   -201.5uA   -254.6uA
-209mV    -381.6uA   -229.4uA   -283.3uA
-91.3mV   -93.19uA   -72.06uA   -68.09uA
-26.09mV  -4.799uA   -3.635uA   -3.718uA
600mV     0A         0A         0A
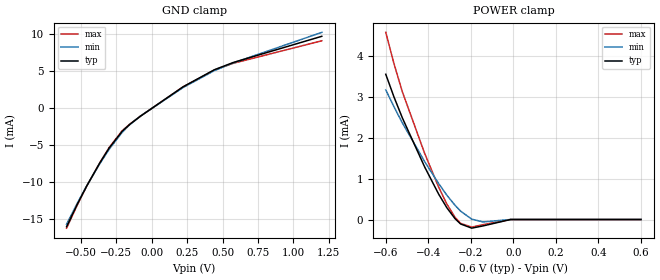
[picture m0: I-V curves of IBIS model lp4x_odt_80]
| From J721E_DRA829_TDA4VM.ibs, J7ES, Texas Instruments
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|   Model lp4x_odt_80
[Model] lp4x_odt_80
Model_type Input
Polarity   Non-Inverting
Enable   Active-High
Vinl =  0.0V
Vinh =  0.900V
C_comp   2.561pF   2.353pF   2.775pF
[Model Spec]
Vinh   0.900V   0.900V   0.900V
Vinl   0.0V   0.0V   0.0V
[Temperature Range]   25.000   0.125k   -40.000
[Voltage Range]   0.600V   0.570V   0.650V
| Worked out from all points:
|   GND clamp passes 1 mA (typ) near -0.07 V on its own axis
|   POWER clamp passes 1 mA (typ) near -0.39 V on its own axis
[GND_clamp]
|Voltage   I(typ)   I(min)   I(max)
-600mV    -16.1mA    -15.77mA   -16.3mA
-522mV    -12.98mA   -12.83mA   -13.06mA
-457mV    -10.55mA   -10.52mA   -10.57mA
-365mV    -7.434mA   -7.535mA   -7.405mA
-300mV    -5.438mA   -5.608mA   -5.373mA
-209mV    -3.187mA   -3.325mA   -3.106mA
-157mV    -2.264mA   -2.311mA   -2.224mA
-78.26mV  -1.1mA     -1.091mA   -1.092mA
222mV     2.877mA    2.781mA    2.867mA
443mV     5.193mA    5.076mA    5.16mA
574mV     6.163mA    6.105mA    6.056mA
1.2V      9.727mA    10.26mA    9.12mA
[POWER_clamp]
|Voltage   I(typ)   I(min)   I(max)
-600mV    3.545mA    3.164mA    4.568mA
-561mV    2.985mA    2.746mA    3.796mA
-522mV    2.48mA     2.358mA    3.117mA
-417mV    1.281mA    1.412mA    1.611mA
-352mV    625.4uA    881.4uA    798uA
-313mV    288.3uA    595uA      379uA
-274mV    18.3uA     344.2uA    50.02uA
-248mV    -109.4uA   203.9uA    -95.43uA
-196mV    -210.8uA   8.405uA    -185.1uA
-143mV    -156.8uA   -58.98uA   -126.1uA
-13.04mV  0A         0A         0A
600mV     0A         0A         0A
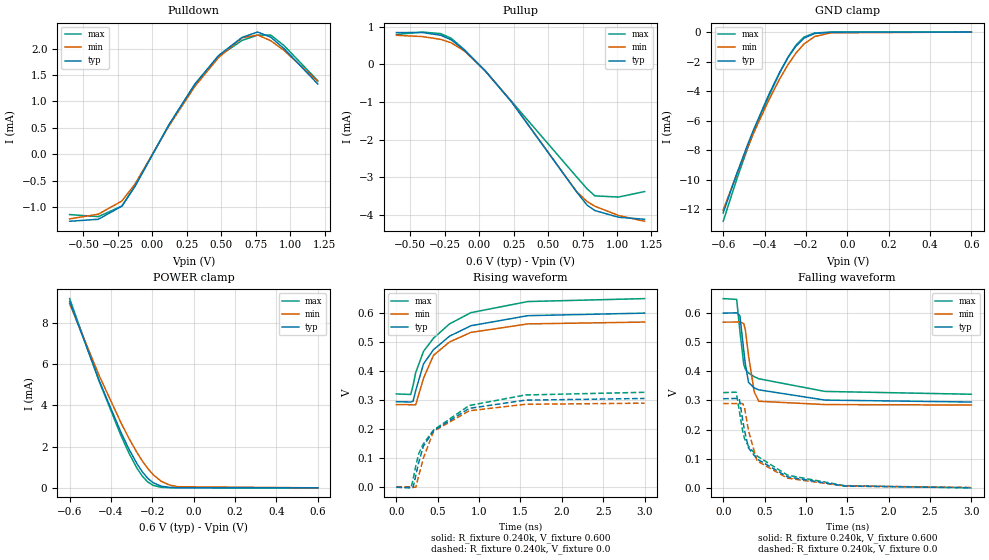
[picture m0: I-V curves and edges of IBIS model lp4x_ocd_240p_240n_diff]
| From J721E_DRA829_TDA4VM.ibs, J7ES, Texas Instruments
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|   Model lp4x_ocd_240p_240n_diff
[Model] lp4x_ocd_240p_240n_diff
Model_type I/O
Polarity   Non-Inverting
Enable   Active-High
Vinl =  0.0V
Vinh =  0.900V
Vmeas =  0.600V
C_comp   2.927pF   2.675pF   3.163pF
[Model Spec]
Vinh   0.900V   0.900V   0.900V
Vinl   0.0V   0.0V   0.0V
Vmeas   0.600V   NA   NA
[Temperature Range]   25.000   0.125k   -40.000
[Voltage Range]   0.600V   0.570V   0.650V
[Pullup Reference]   0.600V   0.570V   0.650V
[Pulldown Reference]   0.0V   0.0V   0.0V
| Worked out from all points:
|   slope of the pulldown table from 0 to 0.09 V, typ, clamps not added: 215 ohm
|   slope of the pullup table from 0 to 0.09 V, typ, clamps not added: 251 ohm
|   GND clamp passes 1 mA (typ) near -0.25 V on its own axis
|   POWER clamp passes 1 mA (typ) near -0.26 V on its own axis
|   rising waveform, R_fixture 0.240k, V_fixture 0.600: 20-80 % time 502ps typ, 425ps min, 540ps max; typ from 0.295 V to 0.599 V
|   rising waveform, R_fixture 0.240k, V_fixture 0.0: 20-80 % time 415ps typ, 324ps min, 503ps max; typ from 0 V to 0.306 V
|   falling waveform, R_fixture 0.240k, V_fixture 0.600: 20-80 % time 95.1ps typ, 85.9ps min, 156ps max; typ from 0.599 V to 0.295 V
|   falling waveform, R_fixture 0.240k, V_fixture 0.0: 20-80 % time 362ps typ, 278ps min, 418ps max; typ from 0.306 V to 0 V
[Pulldown]
|Voltage   I(typ)   I(min)   I(max)
-600mV    -1.271mA   -1.226mA   -1.144mA
-392mV    -1.233mA   -1.137mA   -1.183mA
-221mV    -984.9uA   -887.4uA   -982.9uA
-126mV    -608.1uA   -567.5uA   -606.4uA
120mV     553.9uA    533.1uA    552.7uA
309mV     1.328mA    1.286mA    1.326mA
480mV     1.869mA    1.83mA     1.853mA
651mV     2.213mA    2.204mA    2.155mA
764mV     2.314mA    2.258mA    2.256mA
859mV     2.217mA    2.15mA     2.256mA
954mV     2.004mA    1.969mA    2.061mA
1.2V      1.33mA     1.38mA     1.393mA
[Pullup]
|Voltage   I(typ)   I(min)   I(max)
-600mV    845.1uA    771.9uA    794.5uA
-411mV    846.4uA    738.5uA    858.9uA
-278mV    772.7uA    663.3uA    816.3uA
-202mV    652.7uA    571.6uA    692.4uA
-107mV    376.1uA    357.2uA    390.7uA
44.21mV   -171.8uA   -170.3uA   -175.6uA
234mV     -994.2uA   -986.8uA   -980.8uA
707mV     -3.392mA   -3.382mA   -2.991mA
783mV     -3.744mA   -3.647mA   -3.31mA
840mV     -3.888mA   -3.773mA   -3.498mA
1.011V    -4.066mA   -4.019mA   -3.529mA
1.2V      -4.12mA    -4.173mA   -3.383mA
[GND_clamp]
|Voltage   I(typ)   I(min)   I(max)
-600mV    -12.26mA   -12.07mA   -12.83mA
-535mV    -9.631mA   -9.657mA   -9.999mA
-483mV    -7.674mA   -7.84mA    -7.926mA
-457mV    -6.749mA   -6.974mA   -6.957mA
-378mV    -4.198mA   -4.571mA   -4.306mA
-326mV    -2.706mA   -3.156mA   -2.747mA
-287mV    -1.735mA   -2.22mA    -1.722mA
-248mV    -949.8uA   -1.424mA   -887.8uA
-209mV    -414uA     -806.5uA   -336.6uA
-157mV    -95.46uA   -302uA     -61.62uA
-78.26mV  -9.099uA   -53.02uA   -8.176uA
600mV     0A         0A         0A
[POWER_clamp]
|Voltage   I(typ)   I(min)   I(max)
-600mV    9.037mA    8.928mA    9.175mA
-457mV    5.197mA    5.441mA    5.166mA
-352mV    2.698mA    3.164mA    2.544mA
-313mV    1.878mA    2.4mA      1.683mA
-274mV    1.164mA    1.707mA    946.8uA
-248mV    770.5uA    1.297mA    560.3uA
-222mV    461.8uA    938.4uA    283.8uA
-196mV    246uA      638.9uA    120.5uA
-157mV    79.32uA    316.3uA    23.5uA
-117mV    22.66uA    136.3uA    6.085uA
-78.26mV  6.703uA    54.43uA    1.893uA
600mV     0A         0A         0A
[Ramp]
| variable   typ   min   max
dV/dt_r   0.183/0.416n   0.173/0.324n   0.196/0.501n
dV/dt_f   0.183/94.936p   0.171/85.592p   0.197/0.154n
R_load = 0.240k
[Rising Waveform]
R_fixture= 0.240k
V_fixture= 0.600
V_fixture_min= 0.570
V_fixture_max= 0.650
|time   V(typ)   V(min)   V(max)
0s        294.7mV    284.6mV    321.4mV
173ps     293.8mV    284.5mV    319.6mV
201ps     295.9mV    283.8mV    349.7mV
233ps     332.4mV    283.9mV    394.5mV
328ps     425.1mV    375.5mV    468.1mV
448ps     473.5mV    454.1mV    513.2mV
642ps     520.1mV    500.3mV    562.3mV
901ps     556.1mV    533.1mV    601.1mV
1.589ns   590.7mV    562.4mV    639.3mV
3ns       599.5mV    568.7mV    649.4mV
[Rising Waveform]
R_fixture= 0.240k
V_fixture= 0.0
V_fixture_min= 0.0
V_fixture_max= 0.0
|time   V(typ)   V(min)   V(max)
0s        471.3uV    1.984mV    489.2uV
177ps     -670.2uV   1.833mV    -1.553mV
201ps     -810.9uV   1.195mV    26.31mV
234ps     40.48mV    291.3uV    73.65mV
270ps     85.99mV    39.62mV    116.2mV
327ps     142.3mV    101.3mV    150.2mV
449ps     195mV      192.7mV    197.1mV
880ps     271.8mV    263.5mV    281.6mV
1.559ns   300.1mV    285.8mV    317.9mV
3ns       305.9mV    289.7mV    327.1mV
[Falling Waveform]
R_fixture= 0.240k
V_fixture= 0.600
V_fixture_min= 0.570
V_fixture_max= 0.650
|time   V(typ)   V(min)   V(max)
0s        599.5mV    568.7mV    649.4mV
163ps     600.6mV    568.8mV    646.7mV
202ps     590.7mV    569.6mV    537.5mV
249ps     470mV      563.7mV    422.9mV
268ps     424.8mV    541.7mV    407.4mV
306ps     362.3mV    454.3mV    394.5mV
375ps     343.1mV    330mV      381.7mV
430ps     336.5mV    297.3mV    374.5mV
1.23ns    301.4mV    286mV      331.1mV
3ns       294.7mV    284.4mV    321.4mV
[Falling Waveform]
R_fixture= 0.240k
V_fixture= 0.0
V_fixture_min= 0.0
V_fixture_max= 0.0
|time   V(typ)   V(min)   V(max)
0s        305.9mV    289.6mV    327mV
157ps     307mV      289.6mV    328.5mV
195ps     305mV      290.5mV    265.1mV
237ps     231.1mV    289.1mV    192.9mV
258ps     196.6mV    275.2mV    169.4mV
307ps     136.8mV    195.1mV    142.9mV
409ps     99.32mV    92.74mV    109.7mV
778ps     37.94mV    33.56mV    43.82mV
1.466ns   6.545mV    6.517mV    8.034mV
3ns       456.9uV    1.919mV    475.6uV
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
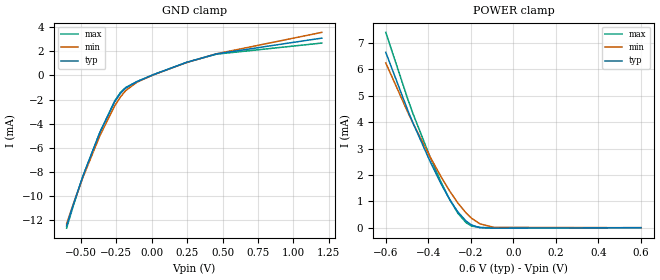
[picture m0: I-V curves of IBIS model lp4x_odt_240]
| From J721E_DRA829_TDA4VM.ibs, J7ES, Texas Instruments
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|   Model lp4x_odt_240
[Model] lp4x_odt_240
Model_type Input
Polarity   Non-Inverting
Enable   Active-High
Vinl =  0.0V
Vinh =  0.900V
C_comp   1.692pF   1.556pF   1.801pF
[Model Spec]
Vinh   0.900V   0.900V   0.900V
Vinl   0.0V   0.0V   0.0V
[Temperature Range]   25.000   0.125k   -40.000
[Voltage Range]   0.600V   0.570V   0.650V
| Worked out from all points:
|   GND clamp passes 1 mA (typ) near -0.18 V on its own axis
|   POWER clamp passes 1 mA (typ) near -0.29 V on its own axis
[GND_clamp]
|Voltage   I(typ)   I(min)   I(max)
-600mV    -12.45mA   -12.28mA   -12.64mA
-548mV    -10.52mA   -10.49mA   -10.61mA
-483mV    -8.276mA   -8.389mA   -8.301mA
-365mV    -4.714mA   -4.99mA    -4.721mA
-261mV    -2.184mA   -2.529mA   -2.13mA
-222mV    -1.513mA   -1.817mA   -1.444mA
-183mV    -1.051mA   -1.261mA   -999.6uA
-104mV    -521.5uA   -568.9uA   -515.1uA
13.04mV   60.78uA    50.64uA    59.86uA
248mV     1.085mA    1.068mA    1.079mA
457mV     1.776mA    1.784mA    1.755mA
1.2V      3.082mA    3.557mA    2.673mA
[POWER_clamp]
|Voltage   I(typ)   I(min)   I(max)
-600mV    6.643mA    6.241mA    7.399mA
-496mV    4.434mA    4.364mA    4.858mA
-470mV    3.928mA    3.925mA    4.275mA
-391mV    2.5mA      2.675mA    2.666mA
-339mV    1.645mA    1.914mA    1.71mA
-300mV    1.075mA    1.395mA    1.074mA
-261mV    597.1uA    934.5uA    548.2uA
-222mV    248.6uA    554.3uA    189.6uA
-196mV    100.8uA    353.5uA    58.59uA
-157mV    -2.47uA    146.1uA    13.43uA
-91.3mV   -16.26uA   13.13uA    -10.82uA
600mV     0A         0A         0A
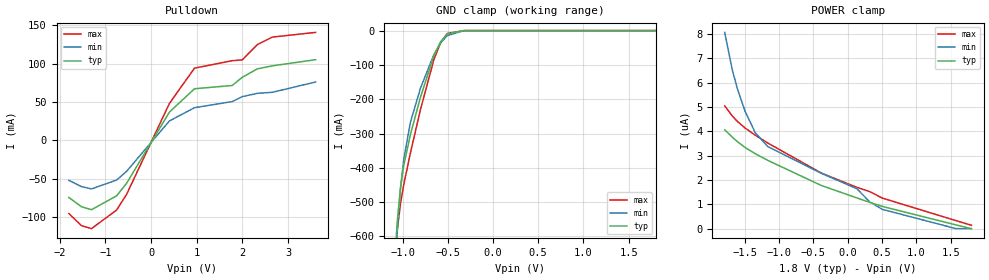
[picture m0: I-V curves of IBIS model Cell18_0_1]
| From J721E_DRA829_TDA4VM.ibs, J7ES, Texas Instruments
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|   Model Cell18_0_1
[Model]  Cell18_0_1
Model_type I/O_open_drain
Polarity   Non-Inverting
Enable   Active-High
Vinl =  0.540V
Vinh =  1.260V
Vmeas =  0.900V
Cref =  50.000pF
Rref =  1.000M
Vref =  0.0V
C_comp   8.808pF   8.664pF   8.912pF
[Model Spec]
Vinh   1.260V   1.134V   1.386V
Vinl   0.540V   0.486V   0.594V
Vmeas   0.900V   NA   NA
Vref   0.0V   NA   NA
Cref   50.000pF   NA   NA
Rref   1.000M   NA   NA
[Temperature Range]   25.000   0.125k   -40.000
[Voltage Range]   1.800V   1.620V   1.980V
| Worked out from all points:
|   slope of the pulldown table from 0 to 0.27 V, typ, clamps not added: 10.5 ohm
|   GND clamp passes 1 mA (typ) near -0.42 V on its own axis
[Pulldown]
|Voltage   I(typ)   I(min)   I(max)
-1.8V     -74.43mA   -52.12mA   -95.36mA
-1.525V   -86.51mA   -60.23mA   -111.1mA
-1.305V   -90.39mA   -63.27mA   -115.1mA
-755mV    -72.29mA   -51.71mA   -90.8mA
-535mV    -55.85mA   -40.22mA   -70.21mA
400mV     36.93mA    25.37mA    48.14mA
950mV     67.4mA     42.7mA     94.32mA
1.775V    71.64mA    50.63mA    104mA
1.995V    82.32mA    57.1mA     105mA
2.325V    93.33mA    61.41mA    124.9mA
2.655V    97.31mA    62.78mA    134.8mA
3.6V      105.3mA    76.2mA     140.9mA
[GND_clamp]
|Voltage   I(typ)   I(min)   I(max)
-1.8V     -12.3A     -11.29A    -13.31A
-1.097V   -731.7mA   -782.5mA   -731.8mA
-1.06V    -561.7mA   -593mA     -586mA
-1.023V   -458.8mA   -462.4mA   -504.6mA
-986mV    -392.6mA   -374mA     -448.2mA
-912mV    -302.1mA   -266.3mA   -355.6mA
-801mV    -193.6mA   -167.4mA   -229.4mA
-653mV    -73.19mA   -69.93mA   -84.18mA
-579mV    -32.5mA    -36.05mA   -34.84mA
-505mV    -9.454mA   -14.3mA    -8.332mA
-320mV    -34.19uA   -280.6uA   -6.588uA
1.8V      0A         0A         0A
[POWER_clamp]
|Voltage   I(typ)   I(min)   I(max)
-1.789V   4.061uA    8.063uA    5.047uA
-1.678V   3.761uA    6.514uA    4.628uA
-1.604V   3.573uA    5.746uA    4.405uA
-1.493V   3.337uA    4.824uA    4.136uA
-1.345V   3.08uA     3.944uA    3.841uA
-1.16V    2.802uA    3.369uA    3.515uA
-383mV    1.773uA    2.274uA    2.283uA
135mV     1.262uA    1.639uA    1.697uA
320mV     1.081uA    1.1uA      1.523uA
505mV     912.8nA    792nA      1.255uA
1.578V    151.7nA    0A         328nA
1.8V      0A         0A         138.8nA
[Ramp]
| variable   typ   min   max
dV/dt_r   0.891/0.445n   0.740/0.441n   1.022/0.473n
dV/dt_f   0.231/21.125n   91.059m/16.097n   0.456/15.704n
R_load = 50.000
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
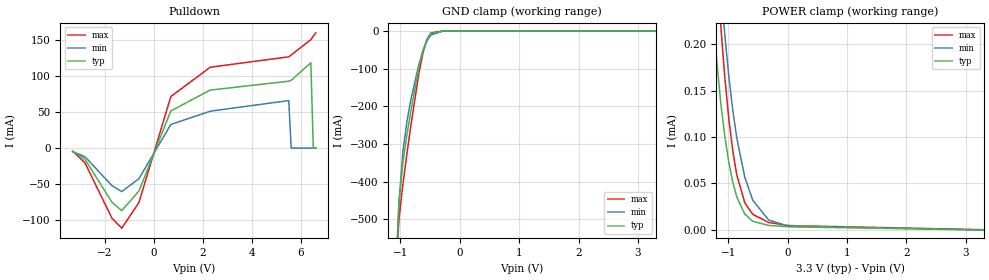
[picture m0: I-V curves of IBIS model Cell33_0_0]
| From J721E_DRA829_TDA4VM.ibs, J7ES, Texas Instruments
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| **************** Start I2C 3.3V ***************************************
|   Model Cell33_0_0
[Model]  Cell33_0_0
Model_type I/O_open_drain
Polarity   Non-Inverting
Enable   Active-High
Vinl =  0.990V
Vinh =  2.310V
Vmeas =  1.650V
Cref =  50.000pF
Rref =  1.000M
Vref =  0.0V
C_comp   6.060pF   6.037pF   6.070pF
[Model Spec]
Vinh   2.310V   2.079V   2.541V
Vinl   0.990V   0.891V   1.089V
Vmeas   1.650V   NA   NA
Vref   0.0V   NA   NA
Cref   50.000pF   NA   NA
Rref   1.000M   NA   NA
[Temperature Range]   25.000   0.125k   -40.000
[Voltage Range]   3.300V   2.970V   3.630V
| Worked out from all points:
|   slope of the pulldown table from 0 to 0.495 V, typ, clamps not added: 12.2 ohm
|   GND clamp passes 1 mA (typ) near -0.42 V on its own axis
|   POWER clamp passes 1 mA (typ) near -1.87 V on its own axis
[Pulldown]
|Voltage   I(typ)   I(min)   I(max)
-3.3V     -4.534mA   -4.862mA   -4.201mA
-2.8V     -15.43mA   -11.77mA   -20.27mA
-1.7V     -74.96mA   -51.98mA   -96.98mA
-1.3V     -86.65mA   -60.26mA   -111mA
-600mV    -59.58mA   -42.4mA    -75.45mA
700mV     51.54mA    32.76mA    71.48mA
2.3V      80.48mA    51.2mA     112.2mA
5.5V      92.79mA    65.93mA    126.6mA
5.6V      94.04mA    -11.2nA    129.2mA
6.4V      118.4mA    -2.9uA     150.4mA
6.5V      -600nA     -3.9uA     155.5mA
6.6V      -700nA     -18.4uA    159.8mA
[GND_clamp]
|Voltage   I(typ)   I(min)   I(max)
-3.3V     -42.11A    -39.21A    -45.03A
-1.089V   -685.9mA   -733.9mA   -690.4mA
-1.022V   -455mA     -457.8mA   -501.3mA
-955mV    -349.5mA   -319.6mA   -406.5mA
-888mV    -276.1mA   -240.2mA   -326.3mA
-821mV    -211.3mA   -182mA     -250.5mA
-687mV    -96.78mA   -88.79mA   -113mA
-620mV    -52.79mA   -53.16mA   -59.38mA
-553mV    -22.32mA   -26.92mA   -22.84mA
-486mV    -6.226mA   -10.63mA   -5.004mA
-285mV    -10.21uA   -113.8uA   -1.604uA
3.3V      0A         0A         0A
[POWER_clamp]
|Voltage   I(typ)   I(min)   I(max)
-3.266V   6.209A     1.842A     17.02A
-1.256V   225.5uA    393.8uA    359.2uA
-1.122V   134.7uA    261.3uA    217.8uA
-1.055V   100.1uA    208.8uA    163.1uA
-988mV    72.34uA    164.6uA    118.8uA
-921mV    50.97uA    128.1uA    84.4uA
-854mV    35.26uA    98.53uA    58.93uA
-720mV    16.98uA    56.64uA    29.27uA
-586mV    9.341uA    31.96uA    16.77uA
-318mV    4.885uA    10.66uA    8.077uA
17mV      3.368uA    4.058uA    4.711uA
3.3V      0A         0A         270nA
[Ramp]
| variable   typ   min   max
dV/dt_r   1.555/0.132n   1.078/0.221n   1.837/0.142n
dV/dt_f   0.277/17.227n   0.127/16.535n   0.546/17.144n
R_load = 50.000
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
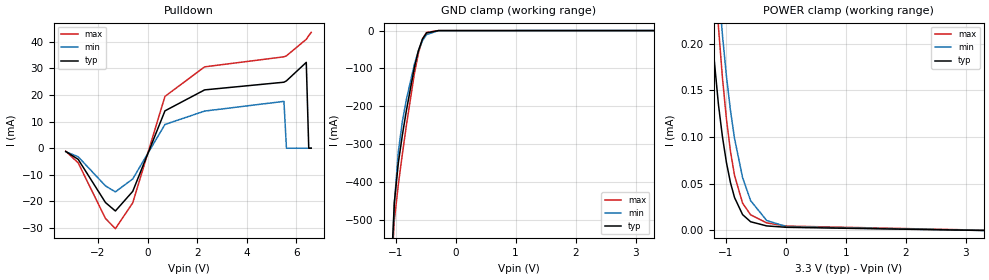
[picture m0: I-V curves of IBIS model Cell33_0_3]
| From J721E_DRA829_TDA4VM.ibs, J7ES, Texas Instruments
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|   Model Cell33_0_3
[Model]  Cell33_0_3
Model_type I/O_open_drain
Polarity   Non-Inverting
Enable   Active-High
Vinl =  0.990V
Vinh =  2.310V
Vmeas =  1.650V
Cref =  50.000pF
Rref =  1.000M
Vref =  0.0V
C_comp   6.060pF   6.037pF   6.070pF
[Model Spec]
Vinh   2.310V   2.079V   2.541V
Vinl   0.990V   0.891V   1.089V
Vmeas   1.650V   NA   NA
Vref   0.0V   NA   NA
Cref   50.000pF   NA   NA
Rref   1.000M   NA   NA
[Temperature Range]   25.000   0.125k   -40.000
[Voltage Range]   3.300V   2.970V   3.630V
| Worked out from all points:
|   slope of the pulldown table from 0 to 0.495 V, typ, clamps not added: 44.6 ohm
|   GND clamp passes 1 mA (typ) near -0.42 V on its own axis
|   POWER clamp passes 1 mA (typ) near -1.87 V on its own axis
[Pulldown]
|Voltage   I(typ)   I(min)   I(max)
-3.3V     -1.237mA   -1.329mA   -1.147mA
-2.8V     -4.212mA   -3.219mA   -5.536mA
-1.7V     -20.45mA   -14.19mA   -26.45mA
-1.3V     -23.64mA   -16.44mA   -30.29mA
-600mV    -16.25mA   -11.57mA   -20.58mA
700mV     14.06mA    8.936mA    19.5mA
2.3V      21.95mA    13.97mA    30.62mA
5.5V      24.84mA    17.63mA    34.4mA
5.6V      25.35mA    -3.1nA     34.77mA
6.4V      32.3mA     -800nA     40.98mA
6.5V      -100nA     -1.1uA     42.39mA
6.6V      -200nA     -5uA       43.59mA
[GND_clamp]
|Voltage   I(typ)   I(min)   I(max)
-3.3V     -42.11A    -39.21A    -45.03A
-1.089V   -685.9mA   -733.9mA   -690.4mA
-1.022V   -455mA     -457.8mA   -501.3mA
-955mV    -349.5mA   -319.6mA   -406.5mA
-888mV    -276.1mA   -240.2mA   -326.3mA
-821mV    -211.3mA   -182mA     -250.5mA
-687mV    -96.78mA   -88.79mA   -113mA
-620mV    -52.79mA   -53.16mA   -59.38mA
-553mV    -22.32mA   -26.92mA   -22.84mA
-486mV    -6.226mA   -10.63mA   -5.004mA
-285mV    -10.21uA   -113.8uA   -1.604uA
3.3V      0A         0A         0A
[POWER_clamp]
|Voltage   I(typ)   I(min)   I(max)
-3.266V   6.209A     1.842A     17.01A
-1.256V   225.5uA    393.8uA    359.2uA
-1.122V   134.7uA    261.3uA    217.8uA
-1.055V   100.1uA    208.8uA    163.1uA
-988mV    72.34uA    164.6uA    118.8uA
-921mV    50.97uA    128.1uA    84.4uA
-854mV    35.26uA    98.53uA    58.93uA
-720mV    16.98uA    56.64uA    29.27uA
-586mV    9.341uA    31.96uA    16.77uA
-318mV    4.885uA    10.66uA    8.077uA
17mV      3.368uA    4.058uA    4.711uA
3.3V      0A         0A         270nA
[Ramp]
| variable   typ   min   max
dV/dt_r   0.651/0.102n   0.418/0.146n   0.881/78.570p
dV/dt_f   0.649/4.676n   0.412/6.584n   0.881/3.014n
R_load = 50.000
|**************** End I2C 3.3V *****************************************
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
